VERSION 5.8 ;
BUSBITCHARS "[]" ;
DIVIDERCHAR "/" ;
UNITS
    DATABASE MICRONS 1000 ;
END UNITS

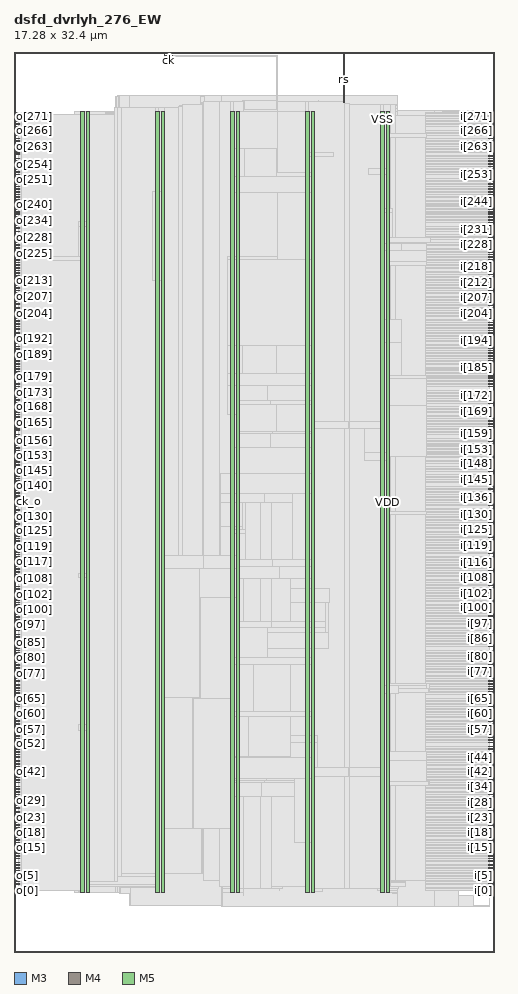
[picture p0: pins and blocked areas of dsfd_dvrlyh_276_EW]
MACRO dsfd_dvrlyh_276_EW
  FOREIGN dsfd_dvrlyh_276_EW 0 0 ;
  CLASS BLOCK ;
  SIZE 17.28 BY 32.4 ;
  PIN ck
    DIRECTION INPUT ;
    USE SIGNAL ;
    PORT
      LAYER M3 ;
        RECT  5.4 32.256 5.418 32.4 ;
    END
    PORT
      LAYER M3 ;
        RECT  5.4 32.155 5.706 32.268 ;
    END
  END ck
  PIN ck_o
    DIRECTION OUTPUT ;
    USE SIGNAL ;
    PORT
      LAYER M4 ;
        RECT  0 16.224 0.192 16.248 ;
    END
  END ck_o
  PIN i[0]
    DIRECTION INPUT ;
    USE SIGNAL ;
    PORT
      LAYER M4 ;
        RECT  17.088 2.208 17.28 2.232 ;
    END
  END i[0]
  PIN i[100]
    DIRECTION INPUT ;
    USE SIGNAL ;
    PORT
      LAYER M4 ;
        RECT  17.088 12.384 17.28 12.408 ;
    END
  END i[100]
  PIN i[101]
    DIRECTION INPUT ;
    USE SIGNAL ;
    PORT
      LAYER M4 ;
        RECT  17.088 12.48 17.28 12.504 ;
    END
  END i[101]
  PIN i[102]
    DIRECTION INPUT ;
    USE SIGNAL ;
    PORT
      LAYER M4 ;
        RECT  17.088 12.624 17.28 12.648 ;
    END
  END i[102]
  PIN i[103]
    DIRECTION INPUT ;
    USE SIGNAL ;
    PORT
      LAYER M4 ;
        RECT  17.088 12.72 17.28 12.744 ;
    END
  END i[103]
  PIN i[104]
    DIRECTION INPUT ;
    USE SIGNAL ;
    PORT
      LAYER M4 ;
        RECT  17.088 12.816 17.28 12.84 ;
    END
  END i[104]
  PIN i[105]
    DIRECTION INPUT ;
    USE SIGNAL ;
    PORT
      LAYER M4 ;
        RECT  17.088 12.912 17.28 12.936 ;
    END
  END i[105]
  PIN i[106]
    DIRECTION INPUT ;
    USE SIGNAL ;
    PORT
      LAYER M4 ;
        RECT  17.088 13.008 17.28 13.032 ;
    END
  END i[106]
  PIN i[107]
    DIRECTION INPUT ;
    USE SIGNAL ;
    PORT
      LAYER M4 ;
        RECT  17.088 13.104 17.28 13.128 ;
    END
  END i[107]
  PIN i[108]
    DIRECTION INPUT ;
    USE SIGNAL ;
    PORT
      LAYER M4 ;
        RECT  17.088 13.2 17.28 13.224 ;
    END
  END i[108]
  PIN i[109]
    DIRECTION INPUT ;
    USE SIGNAL ;
    PORT
      LAYER M4 ;
        RECT  17.088 13.296 17.28 13.32 ;
    END
  END i[109]
  PIN i[10]
    DIRECTION INPUT ;
    USE SIGNAL ;
    PORT
      LAYER M4 ;
        RECT  17.088 3.264 17.28 3.288 ;
    END
  END i[10]
  PIN i[110]
    DIRECTION INPUT ;
    USE SIGNAL ;
    PORT
      LAYER M4 ;
        RECT  17.088 13.392 17.28 13.416 ;
    END
  END i[110]
  PIN i[111]
    DIRECTION INPUT ;
    USE SIGNAL ;
    PORT
      LAYER M4 ;
        RECT  17.088 13.536 17.28 13.56 ;
    END
  END i[111]
  PIN i[112]
    DIRECTION INPUT ;
    USE SIGNAL ;
    PORT
      LAYER M4 ;
        RECT  17.088 13.632 17.28 13.656 ;
    END
  END i[112]
  PIN i[113]
    DIRECTION INPUT ;
    USE SIGNAL ;
    PORT
      LAYER M4 ;
        RECT  17.088 13.728 17.28 13.752 ;
    END
  END i[113]
  PIN i[114]
    DIRECTION INPUT ;
    USE SIGNAL ;
    PORT
      LAYER M4 ;
        RECT  17.088 13.824 17.28 13.848 ;
    END
  END i[114]
  PIN i[115]
    DIRECTION INPUT ;
    USE SIGNAL ;
    PORT
      LAYER M4 ;
        RECT  17.088 13.92 17.28 13.944 ;
    END
  END i[115]
  PIN i[116]
    DIRECTION INPUT ;
    USE SIGNAL ;
    PORT
      LAYER M4 ;
        RECT  17.088 14.016 17.28 14.04 ;
    END
  END i[116]
  PIN i[117]
    DIRECTION INPUT ;
    USE SIGNAL ;
    PORT
      LAYER M4 ;
        RECT  17.088 14.112 17.28 14.136 ;
    END
  END i[117]
  PIN i[118]
    DIRECTION INPUT ;
    USE SIGNAL ;
    PORT
      LAYER M4 ;
        RECT  17.088 14.208 17.28 14.232 ;
    END
  END i[118]
  PIN i[119]
    DIRECTION INPUT ;
    USE SIGNAL ;
    PORT
      LAYER M4 ;
        RECT  17.088 14.352 17.28 14.376 ;
    END
  END i[119]
  PIN i[11]
    DIRECTION INPUT ;
    USE SIGNAL ;
    PORT
      LAYER M4 ;
        RECT  17.088 3.36 17.28 3.384 ;
    END
  END i[11]
  PIN i[120]
    DIRECTION INPUT ;
    USE SIGNAL ;
    PORT
      LAYER M4 ;
        RECT  17.088 14.448 17.28 14.472 ;
    END
  END i[120]
  PIN i[121]
    DIRECTION INPUT ;
    USE SIGNAL ;
    PORT
      LAYER M4 ;
        RECT  17.088 14.544 17.28 14.568 ;
    END
  END i[121]
  PIN i[122]
    DIRECTION INPUT ;
    USE SIGNAL ;
    PORT
      LAYER M4 ;
        RECT  17.088 14.64 17.28 14.664 ;
    END
  END i[122]
  PIN i[123]
    DIRECTION INPUT ;
    USE SIGNAL ;
    PORT
      LAYER M4 ;
        RECT  17.088 14.736 17.28 14.76 ;
    END
  END i[123]
  PIN i[124]
    DIRECTION INPUT ;
    USE SIGNAL ;
    PORT
      LAYER M4 ;
        RECT  17.088 14.832 17.28 14.856 ;
    END
  END i[124]
  PIN i[125]
    DIRECTION INPUT ;
    USE SIGNAL ;
    PORT
      LAYER M4 ;
        RECT  17.088 14.928 17.28 14.952 ;
    END
  END i[125]
  PIN i[126]
    DIRECTION INPUT ;
    USE SIGNAL ;
    PORT
      LAYER M4 ;
        RECT  17.088 15.024 17.28 15.048 ;
    END
  END i[126]
  PIN i[127]
    DIRECTION INPUT ;
    USE SIGNAL ;
    PORT
      LAYER M4 ;
        RECT  17.088 15.12 17.28 15.144 ;
    END
  END i[127]
  PIN i[128]
    DIRECTION INPUT ;
    USE SIGNAL ;
    PORT
      LAYER M4 ;
        RECT  17.088 15.264 17.28 15.288 ;
    END
  END i[128]
  PIN i[129]
    DIRECTION INPUT ;
    USE SIGNAL ;
    PORT
      LAYER M4 ;
        RECT  17.088 15.36 17.28 15.384 ;
    END
  END i[129]
  PIN i[12]
    DIRECTION INPUT ;
    USE SIGNAL ;
    PORT
      LAYER M4 ;
        RECT  17.088 3.456 17.28 3.48 ;
    END
  END i[12]
  PIN i[130]
    DIRECTION INPUT ;
    USE SIGNAL ;
    PORT
      LAYER M4 ;
        RECT  17.088 15.456 17.28 15.48 ;
    END
  END i[130]
  PIN i[131]
    DIRECTION INPUT ;
    USE SIGNAL ;
    PORT
      LAYER M4 ;
        RECT  17.088 15.552 17.28 15.576 ;
    END
  END i[131]
  PIN i[132]
    DIRECTION INPUT ;
    USE SIGNAL ;
    PORT
      LAYER M4 ;
        RECT  17.088 15.648 17.28 15.672 ;
    END
  END i[132]
  PIN i[133]
    DIRECTION INPUT ;
    USE SIGNAL ;
    PORT
      LAYER M4 ;
        RECT  17.088 15.744 17.28 15.768 ;
    END
  END i[133]
  PIN i[134]
    DIRECTION INPUT ;
    USE SIGNAL ;
    PORT
      LAYER M4 ;
        RECT  17.088 15.84 17.28 15.864 ;
    END
  END i[134]
  PIN i[135]
    DIRECTION INPUT ;
    USE SIGNAL ;
    PORT
      LAYER M4 ;
        RECT  17.088 15.936 17.28 15.96 ;
    END
  END i[135]
  PIN i[136]
    DIRECTION INPUT ;
    USE SIGNAL ;
    PORT
      LAYER M4 ;
        RECT  17.088 16.08 17.28 16.104 ;
    END
  END i[136]
  PIN i[137]
    DIRECTION INPUT ;
    USE SIGNAL ;
    PORT
      LAYER M4 ;
        RECT  17.088 16.176 17.28 16.2 ;
    END
  END i[137]
  PIN i[138]
    DIRECTION INPUT ;
    USE SIGNAL ;
    PORT
      LAYER M4 ;
        RECT  17.088 16.272 17.28 16.296 ;
    END
  END i[138]
  PIN i[139]
    DIRECTION INPUT ;
    USE SIGNAL ;
    PORT
      LAYER M4 ;
        RECT  17.088 16.368 17.28 16.392 ;
    END
  END i[139]
  PIN i[13]
    DIRECTION INPUT ;
    USE SIGNAL ;
    PORT
      LAYER M4 ;
        RECT  17.088 3.552 17.28 3.576 ;
    END
  END i[13]
  PIN i[140]
    DIRECTION INPUT ;
    USE SIGNAL ;
    PORT
      LAYER M4 ;
        RECT  17.088 16.464 17.28 16.488 ;
    END
  END i[140]
  PIN i[141]
    DIRECTION INPUT ;
    USE SIGNAL ;
    PORT
      LAYER M4 ;
        RECT  17.088 16.56 17.28 16.584 ;
    END
  END i[141]
  PIN i[142]
    DIRECTION INPUT ;
    USE SIGNAL ;
    PORT
      LAYER M4 ;
        RECT  17.088 16.656 17.28 16.68 ;
    END
  END i[142]
  PIN i[143]
    DIRECTION INPUT ;
    USE SIGNAL ;
    PORT
      LAYER M4 ;
        RECT  17.088 16.752 17.28 16.776 ;
    END
  END i[143]
  PIN i[144]
    DIRECTION INPUT ;
    USE SIGNAL ;
    PORT
      LAYER M4 ;
        RECT  17.088 16.896 17.28 16.92 ;
    END
  END i[144]
  PIN i[145]
    DIRECTION INPUT ;
    USE SIGNAL ;
    PORT
      LAYER M4 ;
        RECT  17.088 16.992 17.28 17.016 ;
    END
  END i[145]
  PIN i[146]
    DIRECTION INPUT ;
    USE SIGNAL ;
    PORT
      LAYER M4 ;
        RECT  17.088 17.088 17.28 17.112 ;
    END
  END i[146]
  PIN i[147]
    DIRECTION INPUT ;
    USE SIGNAL ;
    PORT
      LAYER M4 ;
        RECT  17.088 17.184 17.28 17.208 ;
    END
  END i[147]
  PIN i[148]
    DIRECTION INPUT ;
    USE SIGNAL ;
    PORT
      LAYER M4 ;
        RECT  17.088 17.28 17.28 17.304 ;
    END
  END i[148]
  PIN i[149]
    DIRECTION INPUT ;
    USE SIGNAL ;
    PORT
      LAYER M4 ;
        RECT  17.088 17.376 17.28 17.4 ;
    END
  END i[149]
  PIN i[14]
    DIRECTION INPUT ;
    USE SIGNAL ;
    PORT
      LAYER M4 ;
        RECT  17.088 3.648 17.28 3.672 ;
    END
  END i[14]
  PIN i[150]
    DIRECTION INPUT ;
    USE SIGNAL ;
    PORT
      LAYER M4 ;
        RECT  17.088 17.472 17.28 17.496 ;
    END
  END i[150]
  PIN i[151]
    DIRECTION INPUT ;
    USE SIGNAL ;
    PORT
      LAYER M4 ;
        RECT  17.088 17.568 17.28 17.592 ;
    END
  END i[151]
  PIN i[152]
    DIRECTION INPUT ;
    USE SIGNAL ;
    PORT
      LAYER M4 ;
        RECT  17.088 17.664 17.28 17.688 ;
    END
  END i[152]
  PIN i[153]
    DIRECTION INPUT ;
    USE SIGNAL ;
    PORT
      LAYER M4 ;
        RECT  17.088 17.808 17.28 17.832 ;
    END
  END i[153]
  PIN i[154]
    DIRECTION INPUT ;
    USE SIGNAL ;
    PORT
      LAYER M4 ;
        RECT  17.088 17.904 17.28 17.928 ;
    END
  END i[154]
  PIN i[155]
    DIRECTION INPUT ;
    USE SIGNAL ;
    PORT
      LAYER M4 ;
        RECT  17.088 18 17.28 18.024 ;
    END
  END i[155]
  PIN i[156]
    DIRECTION INPUT ;
    USE SIGNAL ;
    PORT
      LAYER M4 ;
        RECT  17.088 18.096 17.28 18.12 ;
    END
  END i[156]
  PIN i[157]
    DIRECTION INPUT ;
    USE SIGNAL ;
    PORT
      LAYER M4 ;
        RECT  17.088 18.192 17.28 18.216 ;
    END
  END i[157]
  PIN i[158]
    DIRECTION INPUT ;
    USE SIGNAL ;
    PORT
      LAYER M4 ;
        RECT  17.088 18.288 17.28 18.312 ;
    END
  END i[158]
  PIN i[159]
    DIRECTION INPUT ;
    USE SIGNAL ;
    PORT
      LAYER M4 ;
        RECT  17.088 18.384 17.28 18.408 ;
    END
  END i[159]
  PIN i[15]
    DIRECTION INPUT ;
    USE SIGNAL ;
    PORT
      LAYER M4 ;
        RECT  17.088 3.744 17.28 3.768 ;
    END
  END i[15]
  PIN i[160]
    DIRECTION INPUT ;
    USE SIGNAL ;
    PORT
      LAYER M4 ;
        RECT  17.088 18.48 17.28 18.504 ;
    END
  END i[160]
  PIN i[161]
    DIRECTION INPUT ;
    USE SIGNAL ;
    PORT
      LAYER M4 ;
        RECT  17.088 18.624 17.28 18.648 ;
    END
  END i[161]
  PIN i[162]
    DIRECTION INPUT ;
    USE SIGNAL ;
    PORT
      LAYER M4 ;
        RECT  17.088 18.72 17.28 18.744 ;
    END
  END i[162]
  PIN i[163]
    DIRECTION INPUT ;
    USE SIGNAL ;
    PORT
      LAYER M4 ;
        RECT  17.088 18.816 17.28 18.84 ;
    END
  END i[163]
  PIN i[164]
    DIRECTION INPUT ;
    USE SIGNAL ;
    PORT
      LAYER M4 ;
        RECT  17.088 18.912 17.28 18.936 ;
    END
  END i[164]
  PIN i[165]
    DIRECTION INPUT ;
    USE SIGNAL ;
    PORT
      LAYER M4 ;
        RECT  17.088 19.008 17.28 19.032 ;
    END
  END i[165]
  PIN i[166]
    DIRECTION INPUT ;
    USE SIGNAL ;
    PORT
      LAYER M4 ;
        RECT  17.088 19.104 17.28 19.128 ;
    END
  END i[166]
  PIN i[167]
    DIRECTION INPUT ;
    USE SIGNAL ;
    PORT
      LAYER M4 ;
        RECT  17.088 19.2 17.28 19.224 ;
    END
  END i[167]
  PIN i[168]
    DIRECTION INPUT ;
    USE SIGNAL ;
    PORT
      LAYER M4 ;
        RECT  17.088 19.296 17.28 19.32 ;
    END
  END i[168]
  PIN i[169]
    DIRECTION INPUT ;
    USE SIGNAL ;
    PORT
      LAYER M4 ;
        RECT  17.088 19.44 17.28 19.464 ;
    END
  END i[169]
  PIN i[16]
    DIRECTION INPUT ;
    USE SIGNAL ;
    PORT
      LAYER M4 ;
        RECT  17.088 3.84 17.28 3.864 ;
    END
  END i[16]
  PIN i[170]
    DIRECTION INPUT ;
    USE SIGNAL ;
    PORT
      LAYER M4 ;
        RECT  17.088 19.536 17.28 19.56 ;
    END
  END i[170]
  PIN i[171]
    DIRECTION INPUT ;
    USE SIGNAL ;
    PORT
      LAYER M4 ;
        RECT  17.088 19.632 17.28 19.656 ;
    END
  END i[171]
  PIN i[172]
    DIRECTION INPUT ;
    USE SIGNAL ;
    PORT
      LAYER M4 ;
        RECT  17.088 19.728 17.28 19.752 ;
    END
  END i[172]
  PIN i[173]
    DIRECTION INPUT ;
    USE SIGNAL ;
    PORT
      LAYER M4 ;
        RECT  17.088 19.824 17.28 19.848 ;
    END
  END i[173]
  PIN i[174]
    DIRECTION INPUT ;
    USE SIGNAL ;
    PORT
      LAYER M4 ;
        RECT  17.088 19.92 17.28 19.944 ;
    END
  END i[174]
  PIN i[175]
    DIRECTION INPUT ;
    USE SIGNAL ;
    PORT
      LAYER M4 ;
        RECT  17.088 20.016 17.28 20.04 ;
    END
  END i[175]
  PIN i[176]
    DIRECTION INPUT ;
    USE SIGNAL ;
    PORT
      LAYER M4 ;
        RECT  17.088 20.112 17.28 20.136 ;
    END
  END i[176]
  PIN i[177]
    DIRECTION INPUT ;
    USE SIGNAL ;
    PORT
      LAYER M4 ;
        RECT  17.088 20.208 17.28 20.232 ;
    END
  END i[177]
  PIN i[178]
    DIRECTION INPUT ;
    USE SIGNAL ;
    PORT
      LAYER M4 ;
        RECT  17.088 20.352 17.28 20.376 ;
    END
  END i[178]
  PIN i[179]
    DIRECTION INPUT ;
    USE SIGNAL ;
    PORT
      LAYER M4 ;
        RECT  17.088 20.448 17.28 20.472 ;
    END
  END i[179]
  PIN i[17]
    DIRECTION INPUT ;
    USE SIGNAL ;
    PORT
      LAYER M4 ;
        RECT  17.088 3.936 17.28 3.96 ;
    END
  END i[17]
  PIN i[180]
    DIRECTION INPUT ;
    USE SIGNAL ;
    PORT
      LAYER M4 ;
        RECT  17.088 20.544 17.28 20.568 ;
    END
  END i[180]
  PIN i[181]
    DIRECTION INPUT ;
    USE SIGNAL ;
    PORT
      LAYER M4 ;
        RECT  17.088 20.64 17.28 20.664 ;
    END
  END i[181]
  PIN i[182]
    DIRECTION INPUT ;
    USE SIGNAL ;
    PORT
      LAYER M4 ;
        RECT  17.088 20.736 17.28 20.76 ;
    END
  END i[182]
  PIN i[183]
    DIRECTION INPUT ;
    USE SIGNAL ;
    PORT
      LAYER M4 ;
        RECT  17.088 20.832 17.28 20.856 ;
    END
  END i[183]
  PIN i[184]
    DIRECTION INPUT ;
    USE SIGNAL ;
    PORT
      LAYER M4 ;
        RECT  17.088 20.928 17.28 20.952 ;
    END
  END i[184]
  PIN i[185]
    DIRECTION INPUT ;
    USE SIGNAL ;
    PORT
      LAYER M4 ;
        RECT  17.088 21.024 17.28 21.048 ;
    END
  END i[185]
  PIN i[186]
    DIRECTION INPUT ;
    USE SIGNAL ;
    PORT
      LAYER M4 ;
        RECT  17.088 21.168 17.28 21.192 ;
    END
  END i[186]
  PIN i[187]
    DIRECTION INPUT ;
    USE SIGNAL ;
    PORT
      LAYER M4 ;
        RECT  17.088 21.264 17.28 21.288 ;
    END
  END i[187]
  PIN i[188]
    DIRECTION INPUT ;
    USE SIGNAL ;
    PORT
      LAYER M4 ;
        RECT  17.088 21.36 17.28 21.384 ;
    END
  END i[188]
  PIN i[189]
    DIRECTION INPUT ;
    USE SIGNAL ;
    PORT
      LAYER M4 ;
        RECT  17.088 21.456 17.28 21.48 ;
    END
  END i[189]
  PIN i[18]
    DIRECTION INPUT ;
    USE SIGNAL ;
    PORT
      LAYER M4 ;
        RECT  17.088 4.032 17.28 4.056 ;
    END
  END i[18]
  PIN i[190]
    DIRECTION INPUT ;
    USE SIGNAL ;
    PORT
      LAYER M4 ;
        RECT  17.088 21.552 17.28 21.576 ;
    END
  END i[190]
  PIN i[191]
    DIRECTION INPUT ;
    USE SIGNAL ;
    PORT
      LAYER M4 ;
        RECT  17.088 21.648 17.28 21.672 ;
    END
  END i[191]
  PIN i[192]
    DIRECTION INPUT ;
    USE SIGNAL ;
    PORT
      LAYER M4 ;
        RECT  17.088 21.744 17.28 21.768 ;
    END
  END i[192]
  PIN i[193]
    DIRECTION INPUT ;
    USE SIGNAL ;
    PORT
      LAYER M4 ;
        RECT  17.088 21.84 17.28 21.864 ;
    END
  END i[193]
  PIN i[194]
    DIRECTION INPUT ;
    USE SIGNAL ;
    PORT
      LAYER M4 ;
        RECT  17.088 21.984 17.28 22.008 ;
    END
  END i[194]
  PIN i[195]
    DIRECTION INPUT ;
    USE SIGNAL ;
    PORT
      LAYER M4 ;
        RECT  17.088 22.08 17.28 22.104 ;
    END
  END i[195]
  PIN i[196]
    DIRECTION INPUT ;
    USE SIGNAL ;
    PORT
      LAYER M4 ;
        RECT  17.088 22.176 17.28 22.2 ;
    END
  END i[196]
  PIN i[197]
    DIRECTION INPUT ;
    USE SIGNAL ;
    PORT
      LAYER M4 ;
        RECT  17.088 22.272 17.28 22.296 ;
    END
  END i[197]
  PIN i[198]
    DIRECTION INPUT ;
    USE SIGNAL ;
    PORT
      LAYER M4 ;
        RECT  17.088 22.368 17.28 22.392 ;
    END
  END i[198]
  PIN i[199]
    DIRECTION INPUT ;
    USE SIGNAL ;
    PORT
      LAYER M4 ;
        RECT  17.088 22.464 17.28 22.488 ;
    END
  END i[199]
  PIN i[19]
    DIRECTION INPUT ;
    USE SIGNAL ;
    PORT
      LAYER M4 ;
        RECT  17.088 4.176 17.28 4.2 ;
    END
  END i[19]
  PIN i[1]
    DIRECTION INPUT ;
    USE SIGNAL ;
    PORT
      LAYER M4 ;
        RECT  17.088 2.304 17.28 2.328 ;
    END
  END i[1]
  PIN i[200]
    DIRECTION INPUT ;
    USE SIGNAL ;
    PORT
      LAYER M4 ;
        RECT  17.088 22.56 17.28 22.584 ;
    END
  END i[200]
  PIN i[201]
    DIRECTION INPUT ;
    USE SIGNAL ;
    PORT
      LAYER M4 ;
        RECT  17.088 22.656 17.28 22.68 ;
    END
  END i[201]
  PIN i[202]
    DIRECTION INPUT ;
    USE SIGNAL ;
    PORT
      LAYER M4 ;
        RECT  17.088 22.752 17.28 22.776 ;
    END
  END i[202]
  PIN i[203]
    DIRECTION INPUT ;
    USE SIGNAL ;
    PORT
      LAYER M4 ;
        RECT  17.088 22.896 17.28 22.92 ;
    END
  END i[203]
  PIN i[204]
    DIRECTION INPUT ;
    USE SIGNAL ;
    PORT
      LAYER M4 ;
        RECT  17.088 22.992 17.28 23.016 ;
    END
  END i[204]
  PIN i[205]
    DIRECTION INPUT ;
    USE SIGNAL ;
    PORT
      LAYER M4 ;
        RECT  17.088 23.088 17.28 23.112 ;
    END
  END i[205]
  PIN i[206]
    DIRECTION INPUT ;
    USE SIGNAL ;
    PORT
      LAYER M4 ;
        RECT  17.088 23.184 17.28 23.208 ;
    END
  END i[206]
  PIN i[207]
    DIRECTION INPUT ;
    USE SIGNAL ;
    PORT
      LAYER M4 ;
        RECT  17.088 23.28 17.28 23.304 ;
    END
  END i[207]
  PIN i[208]
    DIRECTION INPUT ;
    USE SIGNAL ;
    PORT
      LAYER M4 ;
        RECT  17.088 23.376 17.28 23.4 ;
    END
  END i[208]
  PIN i[209]
    DIRECTION INPUT ;
    USE SIGNAL ;
    PORT
      LAYER M4 ;
        RECT  17.088 23.472 17.28 23.496 ;
    END
  END i[209]
  PIN i[20]
    DIRECTION INPUT ;
    USE SIGNAL ;
    PORT
      LAYER M4 ;
        RECT  17.088 4.272 17.28 4.296 ;
    END
  END i[20]
  PIN i[210]
    DIRECTION INPUT ;
    USE SIGNAL ;
    PORT
      LAYER M4 ;
        RECT  17.088 23.568 17.28 23.592 ;
    END
  END i[210]
  PIN i[211]
    DIRECTION INPUT ;
    USE SIGNAL ;
    PORT
      LAYER M4 ;
        RECT  17.088 23.712 17.28 23.736 ;
    END
  END i[211]
  PIN i[212]
    DIRECTION INPUT ;
    USE SIGNAL ;
    PORT
      LAYER M4 ;
        RECT  17.088 23.808 17.28 23.832 ;
    END
  END i[212]
  PIN i[213]
    DIRECTION INPUT ;
    USE SIGNAL ;
    PORT
      LAYER M4 ;
        RECT  17.088 23.904 17.28 23.928 ;
    END
  END i[213]
  PIN i[214]
    DIRECTION INPUT ;
    USE SIGNAL ;
    PORT
      LAYER M4 ;
        RECT  17.088 24 17.28 24.024 ;
    END
  END i[214]
  PIN i[215]
    DIRECTION INPUT ;
    USE SIGNAL ;
    PORT
      LAYER M4 ;
        RECT  17.088 24.096 17.28 24.12 ;
    END
  END i[215]
  PIN i[216]
    DIRECTION INPUT ;
    USE SIGNAL ;
    PORT
      LAYER M4 ;
        RECT  17.088 24.192 17.28 24.216 ;
    END
  END i[216]
  PIN i[217]
    DIRECTION INPUT ;
    USE SIGNAL ;
    PORT
      LAYER M4 ;
        RECT  17.088 24.288 17.28 24.312 ;
    END
  END i[217]
  PIN i[218]
    DIRECTION INPUT ;
    USE SIGNAL ;
    PORT
      LAYER M4 ;
        RECT  17.088 24.384 17.28 24.408 ;
    END
  END i[218]
  PIN i[219]
    DIRECTION INPUT ;
    USE SIGNAL ;
    PORT
      LAYER M4 ;
        RECT  17.088 24.48 17.28 24.504 ;
    END
  END i[219]
  PIN i[21]
    DIRECTION INPUT ;
    USE SIGNAL ;
    PORT
      LAYER M4 ;
        RECT  17.088 4.368 17.28 4.392 ;
    END
  END i[21]
  PIN i[220]
    DIRECTION INPUT ;
    USE SIGNAL ;
    PORT
      LAYER M4 ;
        RECT  17.088 24.624 17.28 24.648 ;
    END
  END i[220]
  PIN i[221]
    DIRECTION INPUT ;
    USE SIGNAL ;
    PORT
      LAYER M4 ;
        RECT  17.088 24.72 17.28 24.744 ;
    END
  END i[221]
  PIN i[222]
    DIRECTION INPUT ;
    USE SIGNAL ;
    PORT
      LAYER M4 ;
        RECT  17.088 24.816 17.28 24.84 ;
    END
  END i[222]
  PIN i[223]
    DIRECTION INPUT ;
    USE SIGNAL ;
    PORT
      LAYER M4 ;
        RECT  17.088 24.912 17.28 24.936 ;
    END
  END i[223]
  PIN i[224]
    DIRECTION INPUT ;
    USE SIGNAL ;
    PORT
      LAYER M4 ;
        RECT  17.088 25.008 17.28 25.032 ;
    END
  END i[224]
  PIN i[225]
    DIRECTION INPUT ;
    USE SIGNAL ;
    PORT
      LAYER M4 ;
        RECT  17.088 25.104 17.28 25.128 ;
    END
  END i[225]
  PIN i[226]
    DIRECTION INPUT ;
    USE SIGNAL ;
    PORT
      LAYER M4 ;
        RECT  17.088 25.2 17.28 25.224 ;
    END
  END i[226]
  PIN i[227]
    DIRECTION INPUT ;
    USE SIGNAL ;
    PORT
      LAYER M4 ;
        RECT  17.088 25.296 17.28 25.32 ;
    END
  END i[227]
  PIN i[228]
    DIRECTION INPUT ;
    USE SIGNAL ;
    PORT
      LAYER M4 ;
        RECT  17.088 25.44 17.28 25.464 ;
    END
  END i[228]
  PIN i[229]
    DIRECTION INPUT ;
    USE SIGNAL ;
    PORT
      LAYER M4 ;
        RECT  17.088 25.536 17.28 25.56 ;
    END
  END i[229]
  PIN i[22]
    DIRECTION INPUT ;
    USE SIGNAL ;
    PORT
      LAYER M4 ;
        RECT  17.088 4.464 17.28 4.488 ;
    END
  END i[22]
  PIN i[230]
    DIRECTION INPUT ;
    USE SIGNAL ;
    PORT
      LAYER M4 ;
        RECT  17.088 25.632 17.28 25.656 ;
    END
  END i[230]
  PIN i[231]
    DIRECTION INPUT ;
    USE SIGNAL ;
    PORT
      LAYER M4 ;
        RECT  17.088 25.728 17.28 25.752 ;
    END
  END i[231]
  PIN i[232]
    DIRECTION INPUT ;
    USE SIGNAL ;
    PORT
      LAYER M4 ;
        RECT  17.088 25.824 17.28 25.848 ;
    END
  END i[232]
  PIN i[233]
    DIRECTION INPUT ;
    USE SIGNAL ;
    PORT
      LAYER M4 ;
        RECT  17.088 25.92 17.28 25.944 ;
    END
  END i[233]
  PIN i[234]
    DIRECTION INPUT ;
    USE SIGNAL ;
    PORT
      LAYER M4 ;
        RECT  17.088 26.016 17.28 26.04 ;
    END
  END i[234]
  PIN i[235]
    DIRECTION INPUT ;
    USE SIGNAL ;
    PORT
      LAYER M4 ;
        RECT  17.088 26.112 17.28 26.136 ;
    END
  END i[235]
  PIN i[236]
    DIRECTION INPUT ;
    USE SIGNAL ;
    PORT
      LAYER M4 ;
        RECT  17.088 26.256 17.28 26.28 ;
    END
  END i[236]
  PIN i[237]
    DIRECTION INPUT ;
    USE SIGNAL ;
    PORT
      LAYER M4 ;
        RECT  17.088 26.352 17.28 26.376 ;
    END
  END i[237]
  PIN i[238]
    DIRECTION INPUT ;
    USE SIGNAL ;
    PORT
      LAYER M4 ;
        RECT  17.088 26.448 17.28 26.472 ;
    END
  END i[238]
  PIN i[239]
    DIRECTION INPUT ;
    USE SIGNAL ;
    PORT
      LAYER M4 ;
        RECT  17.088 26.544 17.28 26.568 ;
    END
  END i[239]
  PIN i[23]
    DIRECTION INPUT ;
    USE SIGNAL ;
    PORT
      LAYER M4 ;
        RECT  17.088 4.56 17.28 4.584 ;
    END
  END i[23]
  PIN i[240]
    DIRECTION INPUT ;
    USE SIGNAL ;
    PORT
      LAYER M4 ;
        RECT  17.088 26.64 17.28 26.664 ;
    END
  END i[240]
  PIN i[241]
    DIRECTION INPUT ;
    USE SIGNAL ;
    PORT
      LAYER M4 ;
        RECT  17.088 26.736 17.28 26.76 ;
    END
  END i[241]
  PIN i[242]
    DIRECTION INPUT ;
    USE SIGNAL ;
    PORT
      LAYER M4 ;
        RECT  17.088 26.832 17.28 26.856 ;
    END
  END i[242]
  PIN i[243]
    DIRECTION INPUT ;
    USE SIGNAL ;
    PORT
      LAYER M4 ;
        RECT  17.088 26.928 17.28 26.952 ;
    END
  END i[243]
  PIN i[244]
    DIRECTION INPUT ;
    USE SIGNAL ;
    PORT
      LAYER M4 ;
        RECT  17.088 27.024 17.28 27.048 ;
    END
  END i[244]
  PIN i[245]
    DIRECTION INPUT ;
    USE SIGNAL ;
    PORT
      LAYER M4 ;
        RECT  17.088 27.168 17.28 27.192 ;
    END
  END i[245]
  PIN i[246]
    DIRECTION INPUT ;
    USE SIGNAL ;
    PORT
      LAYER M4 ;
        RECT  17.088 27.264 17.28 27.288 ;
    END
  END i[246]
  PIN i[247]
    DIRECTION INPUT ;
    USE SIGNAL ;
    PORT
      LAYER M4 ;
        RECT  17.088 27.36 17.28 27.384 ;
    END
  END i[247]
  PIN i[248]
    DIRECTION INPUT ;
    USE SIGNAL ;
    PORT
      LAYER M4 ;
        RECT  17.088 27.456 17.28 27.48 ;
    END
  END i[248]
  PIN i[249]
    DIRECTION INPUT ;
    USE SIGNAL ;
    PORT
      LAYER M4 ;
        RECT  17.088 27.552 17.28 27.576 ;
    END
  END i[249]
  PIN i[24]
    DIRECTION INPUT ;
    USE SIGNAL ;
    PORT
      LAYER M4 ;
        RECT  17.088 4.656 17.28 4.68 ;
    END
  END i[24]
  PIN i[250]
    DIRECTION INPUT ;
    USE SIGNAL ;
    PORT
      LAYER M4 ;
        RECT  17.088 27.648 17.28 27.672 ;
    END
  END i[250]
  PIN i[251]
    DIRECTION INPUT ;
    USE SIGNAL ;
    PORT
      LAYER M4 ;
        RECT  17.088 27.744 17.28 27.768 ;
    END
  END i[251]
  PIN i[252]
    DIRECTION INPUT ;
    USE SIGNAL ;
    PORT
      LAYER M4 ;
        RECT  17.088 27.84 17.28 27.864 ;
    END
  END i[252]
  PIN i[253]
    DIRECTION INPUT ;
    USE SIGNAL ;
    PORT
      LAYER M4 ;
        RECT  17.088 27.984 17.28 28.008 ;
    END
  END i[253]
  PIN i[254]
    DIRECTION INPUT ;
    USE SIGNAL ;
    PORT
      LAYER M4 ;
        RECT  17.088 28.08 17.28 28.104 ;
    END
  END i[254]
  PIN i[255]
    DIRECTION INPUT ;
    USE SIGNAL ;
    PORT
      LAYER M4 ;
        RECT  17.088 28.176 17.28 28.2 ;
    END
  END i[255]
  PIN i[256]
    DIRECTION INPUT ;
    USE SIGNAL ;
    PORT
      LAYER M4 ;
        RECT  17.088 28.272 17.28 28.296 ;
    END
  END i[256]
  PIN i[257]
    DIRECTION INPUT ;
    USE SIGNAL ;
    PORT
      LAYER M4 ;
        RECT  17.088 28.368 17.28 28.392 ;
    END
  END i[257]
  PIN i[258]
    DIRECTION INPUT ;
    USE SIGNAL ;
    PORT
      LAYER M4 ;
        RECT  17.088 28.464 17.28 28.488 ;
    END
  END i[258]
  PIN i[259]
    DIRECTION INPUT ;
    USE SIGNAL ;
    PORT
      LAYER M4 ;
        RECT  17.088 28.56 17.28 28.584 ;
    END
  END i[259]
  PIN i[25]
    DIRECTION INPUT ;
    USE SIGNAL ;
    PORT
      LAYER M4 ;
        RECT  17.088 4.752 17.28 4.776 ;
    END
  END i[25]
  PIN i[260]
    DIRECTION INPUT ;
    USE SIGNAL ;
    PORT
      LAYER M4 ;
        RECT  17.088 28.656 17.28 28.68 ;
    END
  END i[260]
  PIN i[261]
    DIRECTION INPUT ;
    USE SIGNAL ;
    PORT
      LAYER M4 ;
        RECT  17.088 28.8 17.28 28.824 ;
    END
  END i[261]
  PIN i[262]
    DIRECTION INPUT ;
    USE SIGNAL ;
    PORT
      LAYER M4 ;
        RECT  17.088 28.896 17.28 28.92 ;
    END
  END i[262]
  PIN i[263]
    DIRECTION INPUT ;
    USE SIGNAL ;
    PORT
      LAYER M4 ;
        RECT  17.088 28.992 17.28 29.016 ;
    END
  END i[263]
  PIN i[264]
    DIRECTION INPUT ;
    USE SIGNAL ;
    PORT
      LAYER M4 ;
        RECT  17.088 29.088 17.28 29.112 ;
    END
  END i[264]
  PIN i[265]
    DIRECTION INPUT ;
    USE SIGNAL ;
    PORT
      LAYER M4 ;
        RECT  17.088 29.184 17.28 29.208 ;
    END
  END i[265]
  PIN i[266]
    DIRECTION INPUT ;
    USE SIGNAL ;
    PORT
      LAYER M4 ;
        RECT  17.088 29.28 17.28 29.304 ;
    END
  END i[266]
  PIN i[267]
    DIRECTION INPUT ;
    USE SIGNAL ;
    PORT
      LAYER M4 ;
        RECT  17.088 29.376 17.28 29.4 ;
    END
  END i[267]
  PIN i[268]
    DIRECTION INPUT ;
    USE SIGNAL ;
    PORT
      LAYER M4 ;
        RECT  17.088 29.472 17.28 29.496 ;
    END
  END i[268]
  PIN i[269]
    DIRECTION INPUT ;
    USE SIGNAL ;
    PORT
      LAYER M4 ;
        RECT  17.088 29.568 17.28 29.592 ;
    END
  END i[269]
  PIN i[26]
    DIRECTION INPUT ;
    USE SIGNAL ;
    PORT
      LAYER M4 ;
        RECT  17.088 4.848 17.28 4.872 ;
    END
  END i[26]
  PIN i[270]
    DIRECTION INPUT ;
    USE SIGNAL ;
    PORT
      LAYER M4 ;
        RECT  17.088 29.712 17.28 29.736 ;
    END
  END i[270]
  PIN i[271]
    DIRECTION INPUT ;
    USE SIGNAL ;
    PORT
      LAYER M4 ;
        RECT  17.088 29.808 17.28 29.832 ;
    END
  END i[271]
  PIN i[272]
    DIRECTION INPUT ;
    USE SIGNAL ;
    PORT
      LAYER M4 ;
        RECT  17.088 29.904 17.28 29.928 ;
    END
  END i[272]
  PIN i[273]
    DIRECTION INPUT ;
    USE SIGNAL ;
    PORT
      LAYER M4 ;
        RECT  17.088 30 17.28 30.024 ;
    END
  END i[273]
  PIN i[274]
    DIRECTION INPUT ;
    USE SIGNAL ;
    PORT
      LAYER M4 ;
        RECT  17.088 30.096 17.28 30.12 ;
    END
  END i[274]
  PIN i[275]
    DIRECTION INPUT ;
    USE SIGNAL ;
    PORT
      LAYER M4 ;
        RECT  17.088 30.192 17.28 30.216 ;
    END
  END i[275]
  PIN i[27]
    DIRECTION INPUT ;
    USE SIGNAL ;
    PORT
      LAYER M4 ;
        RECT  17.088 4.992 17.28 5.016 ;
    END
  END i[27]
  PIN i[28]
    DIRECTION INPUT ;
    USE SIGNAL ;
    PORT
      LAYER M4 ;
        RECT  17.088 5.088 17.28 5.112 ;
    END
  END i[28]
  PIN i[29]
    DIRECTION INPUT ;
    USE SIGNAL ;
    PORT
      LAYER M4 ;
        RECT  17.088 5.184 17.28 5.208 ;
    END
  END i[29]
  PIN i[2]
    DIRECTION INPUT ;
    USE SIGNAL ;
    PORT
      LAYER M4 ;
        RECT  17.088 2.448 17.28 2.472 ;
    END
  END i[2]
  PIN i[30]
    DIRECTION INPUT ;
    USE SIGNAL ;
    PORT
      LAYER M4 ;
        RECT  17.088 5.28 17.28 5.304 ;
    END
  END i[30]
  PIN i[31]
    DIRECTION INPUT ;
    USE SIGNAL ;
    PORT
      LAYER M4 ;
        RECT  17.088 5.376 17.28 5.4 ;
    END
  END i[31]
  PIN i[32]
    DIRECTION INPUT ;
    USE SIGNAL ;
    PORT
      LAYER M4 ;
        RECT  17.088 5.472 17.28 5.496 ;
    END
  END i[32]
  PIN i[33]
    DIRECTION INPUT ;
    USE SIGNAL ;
    PORT
      LAYER M4 ;
        RECT  17.088 5.568 17.28 5.592 ;
    END
  END i[33]
  PIN i[34]
    DIRECTION INPUT ;
    USE SIGNAL ;
    PORT
      LAYER M4 ;
        RECT  17.088 5.664 17.28 5.688 ;
    END
  END i[34]
  PIN i[35]
    DIRECTION INPUT ;
    USE SIGNAL ;
    PORT
      LAYER M4 ;
        RECT  17.088 5.76 17.28 5.784 ;
    END
  END i[35]
  PIN i[36]
    DIRECTION INPUT ;
    USE SIGNAL ;
    PORT
      LAYER M4 ;
        RECT  17.088 5.904 17.28 5.928 ;
    END
  END i[36]
  PIN i[37]
    DIRECTION INPUT ;
    USE SIGNAL ;
    PORT
      LAYER M4 ;
        RECT  17.088 6 17.28 6.024 ;
    END
  END i[37]
  PIN i[38]
    DIRECTION INPUT ;
    USE SIGNAL ;
    PORT
      LAYER M4 ;
        RECT  17.088 6.096 17.28 6.12 ;
    END
  END i[38]
  PIN i[39]
    DIRECTION INPUT ;
    USE SIGNAL ;
    PORT
      LAYER M4 ;
        RECT  17.088 6.192 17.28 6.216 ;
    END
  END i[39]
  PIN i[3]
    DIRECTION INPUT ;
    USE SIGNAL ;
    PORT
      LAYER M4 ;
        RECT  17.088 2.544 17.28 2.568 ;
    END
  END i[3]
  PIN i[40]
    DIRECTION INPUT ;
    USE SIGNAL ;
    PORT
      LAYER M4 ;
        RECT  17.088 6.288 17.28 6.312 ;
    END
  END i[40]
  PIN i[41]
    DIRECTION INPUT ;
    USE SIGNAL ;
    PORT
      LAYER M4 ;
        RECT  17.088 6.384 17.28 6.408 ;
    END
  END i[41]
  PIN i[42]
    DIRECTION INPUT ;
    USE SIGNAL ;
    PORT
      LAYER M4 ;
        RECT  17.088 6.48 17.28 6.504 ;
    END
  END i[42]
  PIN i[43]
    DIRECTION INPUT ;
    USE SIGNAL ;
    PORT
      LAYER M4 ;
        RECT  17.088 6.576 17.28 6.6 ;
    END
  END i[43]
  PIN i[44]
    DIRECTION INPUT ;
    USE SIGNAL ;
    PORT
      LAYER M4 ;
        RECT  17.088 6.72 17.28 6.744 ;
    END
  END i[44]
  PIN i[45]
    DIRECTION INPUT ;
    USE SIGNAL ;
    PORT
      LAYER M4 ;
        RECT  17.088 6.816 17.28 6.84 ;
    END
  END i[45]
  PIN i[46]
    DIRECTION INPUT ;
    USE SIGNAL ;
    PORT
      LAYER M4 ;
        RECT  17.088 6.912 17.28 6.936 ;
    END
  END i[46]
  PIN i[47]
    DIRECTION INPUT ;
    USE SIGNAL ;
    PORT
      LAYER M4 ;
        RECT  17.088 7.008 17.28 7.032 ;
    END
  END i[47]
  PIN i[48]
    DIRECTION INPUT ;
    USE SIGNAL ;
    PORT
      LAYER M4 ;
        RECT  17.088 7.104 17.28 7.128 ;
    END
  END i[48]
  PIN i[49]
    DIRECTION INPUT ;
    USE SIGNAL ;
    PORT
      LAYER M4 ;
        RECT  17.088 7.2 17.28 7.224 ;
    END
  END i[49]
  PIN i[4]
    DIRECTION INPUT ;
    USE SIGNAL ;
    PORT
      LAYER M4 ;
        RECT  17.088 2.64 17.28 2.664 ;
    END
  END i[4]
  PIN i[50]
    DIRECTION INPUT ;
    USE SIGNAL ;
    PORT
      LAYER M4 ;
        RECT  17.088 7.296 17.28 7.32 ;
    END
  END i[50]
  PIN i[51]
    DIRECTION INPUT ;
    USE SIGNAL ;
    PORT
      LAYER M4 ;
        RECT  17.088 7.392 17.28 7.416 ;
    END
  END i[51]
  PIN i[52]
    DIRECTION INPUT ;
    USE SIGNAL ;
    PORT
      LAYER M4 ;
        RECT  17.088 7.536 17.28 7.56 ;
    END
  END i[52]
  PIN i[53]
    DIRECTION INPUT ;
    USE SIGNAL ;
    PORT
      LAYER M4 ;
        RECT  17.088 7.632 17.28 7.656 ;
    END
  END i[53]
  PIN i[54]
    DIRECTION INPUT ;
    USE SIGNAL ;
    PORT
      LAYER M4 ;
        RECT  17.088 7.728 17.28 7.752 ;
    END
  END i[54]
  PIN i[55]
    DIRECTION INPUT ;
    USE SIGNAL ;
    PORT
      LAYER M4 ;
        RECT  17.088 7.824 17.28 7.848 ;
    END
  END i[55]
  PIN i[56]
    DIRECTION INPUT ;
    USE SIGNAL ;
    PORT
      LAYER M4 ;
        RECT  17.088 7.92 17.28 7.944 ;
    END
  END i[56]
  PIN i[57]
    DIRECTION INPUT ;
    USE SIGNAL ;
    PORT
      LAYER M4 ;
        RECT  17.088 8.016 17.28 8.04 ;
    END
  END i[57]
  PIN i[58]
    DIRECTION INPUT ;
    USE SIGNAL ;
    PORT
      LAYER M4 ;
        RECT  17.088 8.112 17.28 8.136 ;
    END
  END i[58]
  PIN i[59]
    DIRECTION INPUT ;
    USE SIGNAL ;
    PORT
      LAYER M4 ;
        RECT  17.088 8.208 17.28 8.232 ;
    END
  END i[59]
  PIN i[5]
    DIRECTION INPUT ;
    USE SIGNAL ;
    PORT
      LAYER M4 ;
        RECT  17.088 2.736 17.28 2.76 ;
    END
  END i[5]
  PIN i[60]
    DIRECTION INPUT ;
    USE SIGNAL ;
    PORT
      LAYER M4 ;
        RECT  17.088 8.304 17.28 8.328 ;
    END
  END i[60]
  PIN i[61]
    DIRECTION INPUT ;
    USE SIGNAL ;
    PORT
      LAYER M4 ;
        RECT  17.088 8.448 17.28 8.472 ;
    END
  END i[61]
  PIN i[62]
    DIRECTION INPUT ;
    USE SIGNAL ;
    PORT
      LAYER M4 ;
        RECT  17.088 8.544 17.28 8.568 ;
    END
  END i[62]
  PIN i[63]
    DIRECTION INPUT ;
    USE SIGNAL ;
    PORT
      LAYER M4 ;
        RECT  17.088 8.64 17.28 8.664 ;
    END
  END i[63]
  PIN i[64]
    DIRECTION INPUT ;
    USE SIGNAL ;
    PORT
      LAYER M4 ;
        RECT  17.088 8.736 17.28 8.76 ;
    END
  END i[64]
  PIN i[65]
    DIRECTION INPUT ;
    USE SIGNAL ;
    PORT
      LAYER M4 ;
        RECT  17.088 8.832 17.28 8.856 ;
    END
  END i[65]
  PIN i[66]
    DIRECTION INPUT ;
    USE SIGNAL ;
    PORT
      LAYER M4 ;
        RECT  17.088 8.928 17.28 8.952 ;
    END
  END i[66]
  PIN i[67]
    DIRECTION INPUT ;
    USE SIGNAL ;
    PORT
      LAYER M4 ;
        RECT  17.088 9.024 17.28 9.048 ;
    END
  END i[67]
  PIN i[68]
    DIRECTION INPUT ;
    USE SIGNAL ;
    PORT
      LAYER M4 ;
        RECT  17.088 9.12 17.28 9.144 ;
    END
  END i[68]
  PIN i[69]
    DIRECTION INPUT ;
    USE SIGNAL ;
    PORT
      LAYER M4 ;
        RECT  17.088 9.264 17.28 9.288 ;
    END
  END i[69]
  PIN i[6]
    DIRECTION INPUT ;
    USE SIGNAL ;
    PORT
      LAYER M4 ;
        RECT  17.088 2.832 17.28 2.856 ;
    END
  END i[6]
  PIN i[70]
    DIRECTION INPUT ;
    USE SIGNAL ;
    PORT
      LAYER M4 ;
        RECT  17.088 9.36 17.28 9.384 ;
    END
  END i[70]
  PIN i[71]
    DIRECTION INPUT ;
    USE SIGNAL ;
    PORT
      LAYER M4 ;
        RECT  17.088 9.456 17.28 9.48 ;
    END
  END i[71]
  PIN i[72]
    DIRECTION INPUT ;
    USE SIGNAL ;
    PORT
      LAYER M4 ;
        RECT  17.088 9.552 17.28 9.576 ;
    END
  END i[72]
  PIN i[73]
    DIRECTION INPUT ;
    USE SIGNAL ;
    PORT
      LAYER M4 ;
        RECT  17.088 9.648 17.28 9.672 ;
    END
  END i[73]
  PIN i[74]
    DIRECTION INPUT ;
    USE SIGNAL ;
    PORT
      LAYER M4 ;
        RECT  17.088 9.744 17.28 9.768 ;
    END
  END i[74]
  PIN i[75]
    DIRECTION INPUT ;
    USE SIGNAL ;
    PORT
      LAYER M4 ;
        RECT  17.088 9.84 17.28 9.864 ;
    END
  END i[75]
  PIN i[76]
    DIRECTION INPUT ;
    USE SIGNAL ;
    PORT
      LAYER M4 ;
        RECT  17.088 9.936 17.28 9.96 ;
    END
  END i[76]
  PIN i[77]
    DIRECTION INPUT ;
    USE SIGNAL ;
    PORT
      LAYER M4 ;
        RECT  17.088 10.08 17.28 10.104 ;
    END
  END i[77]
  PIN i[78]
    DIRECTION INPUT ;
    USE SIGNAL ;
    PORT
      LAYER M4 ;
        RECT  17.088 10.176 17.28 10.2 ;
    END
  END i[78]
  PIN i[79]
    DIRECTION INPUT ;
    USE SIGNAL ;
    PORT
      LAYER M4 ;
        RECT  17.088 10.272 17.28 10.296 ;
    END
  END i[79]
  PIN i[7]
    DIRECTION INPUT ;
    USE SIGNAL ;
    PORT
      LAYER M4 ;
        RECT  17.088 2.928 17.28 2.952 ;
    END
  END i[7]
  PIN i[80]
    DIRECTION INPUT ;
    USE SIGNAL ;
    PORT
      LAYER M4 ;
        RECT  17.088 10.368 17.28 10.392 ;
    END
  END i[80]
  PIN i[81]
    DIRECTION INPUT ;
    USE SIGNAL ;
    PORT
      LAYER M4 ;
        RECT  17.088 10.464 17.28 10.488 ;
    END
  END i[81]
  PIN i[82]
    DIRECTION INPUT ;
    USE SIGNAL ;
    PORT
      LAYER M4 ;
        RECT  17.088 10.56 17.28 10.584 ;
    END
  END i[82]
  PIN i[83]
    DIRECTION INPUT ;
    USE SIGNAL ;
    PORT
      LAYER M4 ;
        RECT  17.088 10.656 17.28 10.68 ;
    END
  END i[83]
  PIN i[84]
    DIRECTION INPUT ;
    USE SIGNAL ;
    PORT
      LAYER M4 ;
        RECT  17.088 10.752 17.28 10.776 ;
    END
  END i[84]
  PIN i[85]
    DIRECTION INPUT ;
    USE SIGNAL ;
    PORT
      LAYER M4 ;
        RECT  17.088 10.848 17.28 10.872 ;
    END
  END i[85]
  PIN i[86]
    DIRECTION INPUT ;
    USE SIGNAL ;
    PORT
      LAYER M4 ;
        RECT  17.088 10.992 17.28 11.016 ;
    END
  END i[86]
  PIN i[87]
    DIRECTION INPUT ;
    USE SIGNAL ;
    PORT
      LAYER M4 ;
        RECT  17.088 11.088 17.28 11.112 ;
    END
  END i[87]
  PIN i[88]
    DIRECTION INPUT ;
    USE SIGNAL ;
    PORT
      LAYER M4 ;
        RECT  17.088 11.184 17.28 11.208 ;
    END
  END i[88]
  PIN i[89]
    DIRECTION INPUT ;
    USE SIGNAL ;
    PORT
      LAYER M4 ;
        RECT  17.088 11.28 17.28 11.304 ;
    END
  END i[89]
  PIN i[8]
    DIRECTION INPUT ;
    USE SIGNAL ;
    PORT
      LAYER M4 ;
        RECT  17.088 3.024 17.28 3.048 ;
    END
  END i[8]
  PIN i[90]
    DIRECTION INPUT ;
    USE SIGNAL ;
    PORT
      LAYER M4 ;
        RECT  17.088 11.376 17.28 11.4 ;
    END
  END i[90]
  PIN i[91]
    DIRECTION INPUT ;
    USE SIGNAL ;
    PORT
      LAYER M4 ;
        RECT  17.088 11.472 17.28 11.496 ;
    END
  END i[91]
  PIN i[92]
    DIRECTION INPUT ;
    USE SIGNAL ;
    PORT
      LAYER M4 ;
        RECT  17.088 11.568 17.28 11.592 ;
    END
  END i[92]
  PIN i[93]
    DIRECTION INPUT ;
    USE SIGNAL ;
    PORT
      LAYER M4 ;
        RECT  17.088 11.664 17.28 11.688 ;
    END
  END i[93]
  PIN i[94]
    DIRECTION INPUT ;
    USE SIGNAL ;
    PORT
      LAYER M4 ;
        RECT  17.088 11.808 17.28 11.832 ;
    END
  END i[94]
  PIN i[95]
    DIRECTION INPUT ;
    USE SIGNAL ;
    PORT
      LAYER M4 ;
        RECT  17.088 11.904 17.28 11.928 ;
    END
  END i[95]
  PIN i[96]
    DIRECTION INPUT ;
    USE SIGNAL ;
    PORT
      LAYER M4 ;
        RECT  17.088 12 17.28 12.024 ;
    END
  END i[96]
  PIN i[97]
    DIRECTION INPUT ;
    USE SIGNAL ;
    PORT
      LAYER M4 ;
        RECT  17.088 12.096 17.28 12.12 ;
    END
  END i[97]
  PIN i[98]
    DIRECTION INPUT ;
    USE SIGNAL ;
    PORT
      LAYER M4 ;
        RECT  17.088 12.192 17.28 12.216 ;
    END
  END i[98]
  PIN i[99]
    DIRECTION INPUT ;
    USE SIGNAL ;
    PORT
      LAYER M4 ;
        RECT  17.088 12.288 17.28 12.312 ;
    END
  END i[99]
  PIN i[9]
    DIRECTION INPUT ;
    USE SIGNAL ;
    PORT
      LAYER M4 ;
        RECT  17.088 3.12 17.28 3.144 ;
    END
  END i[9]
  PIN o[0]
    DIRECTION OUTPUT ;
    USE SIGNAL ;
    PORT
      LAYER M4 ;
        RECT  0 2.208 0.192 2.232 ;
    END
  END o[0]
  PIN o[100]
    DIRECTION OUTPUT ;
    USE SIGNAL ;
    PORT
      LAYER M4 ;
        RECT  0 12.336 0.192 12.36 ;
    END
  END o[100]
  PIN o[101]
    DIRECTION OUTPUT ;
    USE SIGNAL ;
    PORT
      LAYER M4 ;
        RECT  0 12.48 0.192 12.504 ;
    END
  END o[101]
  PIN o[102]
    DIRECTION OUTPUT ;
    USE SIGNAL ;
    PORT
      LAYER M4 ;
        RECT  0 12.576 0.192 12.6 ;
    END
  END o[102]
  PIN o[103]
    DIRECTION OUTPUT ;
    USE SIGNAL ;
    PORT
      LAYER M4 ;
        RECT  0 12.672 0.192 12.696 ;
    END
  END o[103]
  PIN o[104]
    DIRECTION OUTPUT ;
    USE SIGNAL ;
    PORT
      LAYER M4 ;
        RECT  0 12.768 0.192 12.792 ;
    END
  END o[104]
  PIN o[105]
    DIRECTION OUTPUT ;
    USE SIGNAL ;
    PORT
      LAYER M4 ;
        RECT  0 12.864 0.192 12.888 ;
    END
  END o[105]
  PIN o[106]
    DIRECTION OUTPUT ;
    USE SIGNAL ;
    PORT
      LAYER M4 ;
        RECT  0 12.96 0.192 12.984 ;
    END
  END o[106]
  PIN o[107]
    DIRECTION OUTPUT ;
    USE SIGNAL ;
    PORT
      LAYER M4 ;
        RECT  0 13.056 0.192 13.08 ;
    END
  END o[107]
  PIN o[108]
    DIRECTION OUTPUT ;
    USE SIGNAL ;
    PORT
      LAYER M4 ;
        RECT  0 13.152 0.192 13.176 ;
    END
  END o[108]
  PIN o[109]
    DIRECTION OUTPUT ;
    USE SIGNAL ;
    PORT
      LAYER M4 ;
        RECT  0 13.296 0.192 13.32 ;
    END
  END o[109]
  PIN o[10]
    DIRECTION OUTPUT ;
    USE SIGNAL ;
    PORT
      LAYER M4 ;
        RECT  0 3.216 0.192 3.24 ;
    END
  END o[10]
  PIN o[110]
    DIRECTION OUTPUT ;
    USE SIGNAL ;
    PORT
      LAYER M4 ;
        RECT  0 13.392 0.192 13.416 ;
    END
  END o[110]
  PIN o[111]
    DIRECTION OUTPUT ;
    USE SIGNAL ;
    PORT
      LAYER M4 ;
        RECT  0 13.488 0.192 13.512 ;
    END
  END o[111]
  PIN o[112]
    DIRECTION OUTPUT ;
    USE SIGNAL ;
    PORT
      LAYER M4 ;
        RECT  0 13.584 0.192 13.608 ;
    END
  END o[112]
  PIN o[113]
    DIRECTION OUTPUT ;
    USE SIGNAL ;
    PORT
      LAYER M4 ;
        RECT  0 13.68 0.192 13.704 ;
    END
  END o[113]
  PIN o[114]
    DIRECTION OUTPUT ;
    USE SIGNAL ;
    PORT
      LAYER M4 ;
        RECT  0 13.776 0.192 13.8 ;
    END
  END o[114]
  PIN o[115]
    DIRECTION OUTPUT ;
    USE SIGNAL ;
    PORT
      LAYER M4 ;
        RECT  0 13.872 0.192 13.896 ;
    END
  END o[115]
  PIN o[116]
    DIRECTION OUTPUT ;
    USE SIGNAL ;
    PORT
      LAYER M4 ;
        RECT  0 13.968 0.192 13.992 ;
    END
  END o[116]
  PIN o[117]
    DIRECTION OUTPUT ;
    USE SIGNAL ;
    PORT
      LAYER M4 ;
        RECT  0 14.064 0.192 14.088 ;
    END
  END o[117]
  PIN o[118]
    DIRECTION OUTPUT ;
    USE SIGNAL ;
    PORT
      LAYER M4 ;
        RECT  0 14.208 0.192 14.232 ;
    END
  END o[118]
  PIN o[119]
    DIRECTION OUTPUT ;
    USE SIGNAL ;
    PORT
      LAYER M4 ;
        RECT  0 14.304 0.192 14.328 ;
    END
  END o[119]
  PIN o[11]
    DIRECTION OUTPUT ;
    USE SIGNAL ;
    PORT
      LAYER M4 ;
        RECT  0 3.36 0.192 3.384 ;
    END
  END o[11]
  PIN o[120]
    DIRECTION OUTPUT ;
    USE SIGNAL ;
    PORT
      LAYER M4 ;
        RECT  0 14.4 0.192 14.424 ;
    END
  END o[120]
  PIN o[121]
    DIRECTION OUTPUT ;
    USE SIGNAL ;
    PORT
      LAYER M4 ;
        RECT  0 14.496 0.192 14.52 ;
    END
  END o[121]
  PIN o[122]
    DIRECTION OUTPUT ;
    USE SIGNAL ;
    PORT
      LAYER M4 ;
        RECT  0 14.592 0.192 14.616 ;
    END
  END o[122]
  PIN o[123]
    DIRECTION OUTPUT ;
    USE SIGNAL ;
    PORT
      LAYER M4 ;
        RECT  0 14.688 0.192 14.712 ;
    END
  END o[123]
  PIN o[124]
    DIRECTION OUTPUT ;
    USE SIGNAL ;
    PORT
      LAYER M4 ;
        RECT  0 14.784 0.192 14.808 ;
    END
  END o[124]
  PIN o[125]
    DIRECTION OUTPUT ;
    USE SIGNAL ;
    PORT
      LAYER M4 ;
        RECT  0 14.88 0.192 14.904 ;
    END
  END o[125]
  PIN o[126]
    DIRECTION OUTPUT ;
    USE SIGNAL ;
    PORT
      LAYER M4 ;
        RECT  0 14.976 0.192 15 ;
    END
  END o[126]
  PIN o[127]
    DIRECTION OUTPUT ;
    USE SIGNAL ;
    PORT
      LAYER M4 ;
        RECT  0 15.12 0.192 15.144 ;
    END
  END o[127]
  PIN o[128]
    DIRECTION OUTPUT ;
    USE SIGNAL ;
    PORT
      LAYER M4 ;
        RECT  0 15.216 0.192 15.24 ;
    END
  END o[128]
  PIN o[129]
    DIRECTION OUTPUT ;
    USE SIGNAL ;
    PORT
      LAYER M4 ;
        RECT  0 15.312 0.192 15.336 ;
    END
  END o[129]
  PIN o[12]
    DIRECTION OUTPUT ;
    USE SIGNAL ;
    PORT
      LAYER M4 ;
        RECT  0 3.456 0.192 3.48 ;
    END
  END o[12]
  PIN o[130]
    DIRECTION OUTPUT ;
    USE SIGNAL ;
    PORT
      LAYER M4 ;
        RECT  0 15.408 0.192 15.432 ;
    END
  END o[130]
  PIN o[131]
    DIRECTION OUTPUT ;
    USE SIGNAL ;
    PORT
      LAYER M4 ;
        RECT  0 15.504 0.192 15.528 ;
    END
  END o[131]
  PIN o[132]
    DIRECTION OUTPUT ;
    USE SIGNAL ;
    PORT
      LAYER M4 ;
        RECT  0 15.6 0.192 15.624 ;
    END
  END o[132]
  PIN o[133]
    DIRECTION OUTPUT ;
    USE SIGNAL ;
    PORT
      LAYER M4 ;
        RECT  0 15.696 0.192 15.72 ;
    END
  END o[133]
  PIN o[134]
    DIRECTION OUTPUT ;
    USE SIGNAL ;
    PORT
      LAYER M4 ;
        RECT  0 15.792 0.192 15.816 ;
    END
  END o[134]
  PIN o[135]
    DIRECTION OUTPUT ;
    USE SIGNAL ;
    PORT
      LAYER M4 ;
        RECT  0 15.888 0.192 15.912 ;
    END
  END o[135]
  PIN o[136]
    DIRECTION OUTPUT ;
    USE SIGNAL ;
    PORT
      LAYER M4 ;
        RECT  0 16.032 0.192 16.056 ;
    END
  END o[136]
  PIN o[137]
    DIRECTION OUTPUT ;
    USE SIGNAL ;
    PORT
      LAYER M4 ;
        RECT  0 16.128 0.192 16.152 ;
    END
  END o[137]
  PIN o[138]
    DIRECTION OUTPUT ;
    USE SIGNAL ;
    PORT
      LAYER M4 ;
        RECT  0 16.32 0.192 16.344 ;
    END
  END o[138]
  PIN o[139]
    DIRECTION OUTPUT ;
    USE SIGNAL ;
    PORT
      LAYER M4 ;
        RECT  0 16.416 0.192 16.44 ;
    END
  END o[139]
  PIN o[13]
    DIRECTION OUTPUT ;
    USE SIGNAL ;
    PORT
      LAYER M4 ;
        RECT  0 3.552 0.192 3.576 ;
    END
  END o[13]
  PIN o[140]
    DIRECTION OUTPUT ;
    USE SIGNAL ;
    PORT
      LAYER M4 ;
        RECT  0 16.512 0.192 16.536 ;
    END
  END o[140]
  PIN o[141]
    DIRECTION OUTPUT ;
    USE SIGNAL ;
    PORT
      LAYER M4 ;
        RECT  0 16.608 0.192 16.632 ;
    END
  END o[141]
  PIN o[142]
    DIRECTION OUTPUT ;
    USE SIGNAL ;
    PORT
      LAYER M4 ;
        RECT  0 16.704 0.192 16.728 ;
    END
  END o[142]
  PIN o[143]
    DIRECTION OUTPUT ;
    USE SIGNAL ;
    PORT
      LAYER M4 ;
        RECT  0 16.8 0.192 16.824 ;
    END
  END o[143]
  PIN o[144]
    DIRECTION OUTPUT ;
    USE SIGNAL ;
    PORT
      LAYER M4 ;
        RECT  0 16.944 0.192 16.968 ;
    END
  END o[144]
  PIN o[145]
    DIRECTION OUTPUT ;
    USE SIGNAL ;
    PORT
      LAYER M4 ;
        RECT  0 17.04 0.192 17.064 ;
    END
  END o[145]
  PIN o[146]
    DIRECTION OUTPUT ;
    USE SIGNAL ;
    PORT
      LAYER M4 ;
        RECT  0 17.136 0.192 17.16 ;
    END
  END o[146]
  PIN o[147]
    DIRECTION OUTPUT ;
    USE SIGNAL ;
    PORT
      LAYER M4 ;
        RECT  0 17.232 0.192 17.256 ;
    END
  END o[147]
  PIN o[148]
    DIRECTION OUTPUT ;
    USE SIGNAL ;
    PORT
      LAYER M4 ;
        RECT  0 17.328 0.192 17.352 ;
    END
  END o[148]
  PIN o[149]
    DIRECTION OUTPUT ;
    USE SIGNAL ;
    PORT
      LAYER M4 ;
        RECT  0 17.424 0.192 17.448 ;
    END
  END o[149]
  PIN o[14]
    DIRECTION OUTPUT ;
    USE SIGNAL ;
    PORT
      LAYER M4 ;
        RECT  0 3.648 0.192 3.672 ;
    END
  END o[14]
  PIN o[150]
    DIRECTION OUTPUT ;
    USE SIGNAL ;
    PORT
      LAYER M4 ;
        RECT  0 17.52 0.192 17.544 ;
    END
  END o[150]
  PIN o[151]
    DIRECTION OUTPUT ;
    USE SIGNAL ;
    PORT
      LAYER M4 ;
        RECT  0 17.616 0.192 17.64 ;
    END
  END o[151]
  PIN o[152]
    DIRECTION OUTPUT ;
    USE SIGNAL ;
    PORT
      LAYER M4 ;
        RECT  0 17.712 0.192 17.736 ;
    END
  END o[152]
  PIN o[153]
    DIRECTION OUTPUT ;
    USE SIGNAL ;
    PORT
      LAYER M4 ;
        RECT  0 17.856 0.192 17.88 ;
    END
  END o[153]
  PIN o[154]
    DIRECTION OUTPUT ;
    USE SIGNAL ;
    PORT
      LAYER M4 ;
        RECT  0 17.952 0.192 17.976 ;
    END
  END o[154]
  PIN o[155]
    DIRECTION OUTPUT ;
    USE SIGNAL ;
    PORT
      LAYER M4 ;
        RECT  0 18.048 0.192 18.072 ;
    END
  END o[155]
  PIN o[156]
    DIRECTION OUTPUT ;
    USE SIGNAL ;
    PORT
      LAYER M4 ;
        RECT  0 18.144 0.192 18.168 ;
    END
  END o[156]
  PIN o[157]
    DIRECTION OUTPUT ;
    USE SIGNAL ;
    PORT
      LAYER M4 ;
        RECT  0 18.24 0.192 18.264 ;
    END
  END o[157]
  PIN o[158]
    DIRECTION OUTPUT ;
    USE SIGNAL ;
    PORT
      LAYER M4 ;
        RECT  0 18.336 0.192 18.36 ;
    END
  END o[158]
  PIN o[159]
    DIRECTION OUTPUT ;
    USE SIGNAL ;
    PORT
      LAYER M4 ;
        RECT  0 18.432 0.192 18.456 ;
    END
  END o[159]
  PIN o[15]
    DIRECTION OUTPUT ;
    USE SIGNAL ;
    PORT
      LAYER M4 ;
        RECT  0 3.744 0.192 3.768 ;
    END
  END o[15]
  PIN o[160]
    DIRECTION OUTPUT ;
    USE SIGNAL ;
    PORT
      LAYER M4 ;
        RECT  0 18.528 0.192 18.552 ;
    END
  END o[160]
  PIN o[161]
    DIRECTION OUTPUT ;
    USE SIGNAL ;
    PORT
      LAYER M4 ;
        RECT  0 18.624 0.192 18.648 ;
    END
  END o[161]
  PIN o[162]
    DIRECTION OUTPUT ;
    USE SIGNAL ;
    PORT
      LAYER M4 ;
        RECT  0 18.768 0.192 18.792 ;
    END
  END o[162]
  PIN o[163]
    DIRECTION OUTPUT ;
    USE SIGNAL ;
    PORT
      LAYER M4 ;
        RECT  0 18.864 0.192 18.888 ;
    END
  END o[163]
  PIN o[164]
    DIRECTION OUTPUT ;
    USE SIGNAL ;
    PORT
      LAYER M4 ;
        RECT  0 18.96 0.192 18.984 ;
    END
  END o[164]
  PIN o[165]
    DIRECTION OUTPUT ;
    USE SIGNAL ;
    PORT
      LAYER M4 ;
        RECT  0 19.056 0.192 19.08 ;
    END
  END o[165]
  PIN o[166]
    DIRECTION OUTPUT ;
    USE SIGNAL ;
    PORT
      LAYER M4 ;
        RECT  0 19.152 0.192 19.176 ;
    END
  END o[166]
  PIN o[167]
    DIRECTION OUTPUT ;
    USE SIGNAL ;
    PORT
      LAYER M4 ;
        RECT  0 19.248 0.192 19.272 ;
    END
  END o[167]
  PIN o[168]
    DIRECTION OUTPUT ;
    USE SIGNAL ;
    PORT
      LAYER M4 ;
        RECT  0 19.344 0.192 19.368 ;
    END
  END o[168]
  PIN o[169]
    DIRECTION OUTPUT ;
    USE SIGNAL ;
    PORT
      LAYER M4 ;
        RECT  0 19.44 0.192 19.464 ;
    END
  END o[169]
  PIN o[16]
    DIRECTION OUTPUT ;
    USE SIGNAL ;
    PORT
      LAYER M4 ;
        RECT  0 3.84 0.192 3.864 ;
    END
  END o[16]
  PIN o[170]
    DIRECTION OUTPUT ;
    USE SIGNAL ;
    PORT
      LAYER M4 ;
        RECT  0 19.536 0.192 19.56 ;
    END
  END o[170]
  PIN o[171]
    DIRECTION OUTPUT ;
    USE SIGNAL ;
    PORT
      LAYER M4 ;
        RECT  0 19.68 0.192 19.704 ;
    END
  END o[171]
  PIN o[172]
    DIRECTION OUTPUT ;
    USE SIGNAL ;
    PORT
      LAYER M4 ;
        RECT  0 19.776 0.192 19.8 ;
    END
  END o[172]
  PIN o[173]
    DIRECTION OUTPUT ;
    USE SIGNAL ;
    PORT
      LAYER M4 ;
        RECT  0 19.872 0.192 19.896 ;
    END
  END o[173]
  PIN o[174]
    DIRECTION OUTPUT ;
    USE SIGNAL ;
    PORT
      LAYER M4 ;
        RECT  0 19.968 0.192 19.992 ;
    END
  END o[174]
  PIN o[175]
    DIRECTION OUTPUT ;
    USE SIGNAL ;
    PORT
      LAYER M4 ;
        RECT  0 20.064 0.192 20.088 ;
    END
  END o[175]
  PIN o[176]
    DIRECTION OUTPUT ;
    USE SIGNAL ;
    PORT
      LAYER M4 ;
        RECT  0 20.16 0.192 20.184 ;
    END
  END o[176]
  PIN o[177]
    DIRECTION OUTPUT ;
    USE SIGNAL ;
    PORT
      LAYER M4 ;
        RECT  0 20.256 0.192 20.28 ;
    END
  END o[177]
  PIN o[178]
    DIRECTION OUTPUT ;
    USE SIGNAL ;
    PORT
      LAYER M4 ;
        RECT  0 20.352 0.192 20.376 ;
    END
  END o[178]
  PIN o[179]
    DIRECTION OUTPUT ;
    USE SIGNAL ;
    PORT
      LAYER M4 ;
        RECT  0 20.448 0.192 20.472 ;
    END
  END o[179]
  PIN o[17]
    DIRECTION OUTPUT ;
    USE SIGNAL ;
    PORT
      LAYER M4 ;
        RECT  0 3.936 0.192 3.96 ;
    END
  END o[17]
  PIN o[180]
    DIRECTION OUTPUT ;
    USE SIGNAL ;
    PORT
      LAYER M4 ;
        RECT  0 20.592 0.192 20.616 ;
    END
  END o[180]
  PIN o[181]
    DIRECTION OUTPUT ;
    USE SIGNAL ;
    PORT
      LAYER M4 ;
        RECT  0 20.688 0.192 20.712 ;
    END
  END o[181]
  PIN o[182]
    DIRECTION OUTPUT ;
    USE SIGNAL ;
    PORT
      LAYER M4 ;
        RECT  0 20.784 0.192 20.808 ;
    END
  END o[182]
  PIN o[183]
    DIRECTION OUTPUT ;
    USE SIGNAL ;
    PORT
      LAYER M4 ;
        RECT  0 20.88 0.192 20.904 ;
    END
  END o[183]
  PIN o[184]
    DIRECTION OUTPUT ;
    USE SIGNAL ;
    PORT
      LAYER M4 ;
        RECT  0 20.976 0.192 21 ;
    END
  END o[184]
  PIN o[185]
    DIRECTION OUTPUT ;
    USE SIGNAL ;
    PORT
      LAYER M4 ;
        RECT  0 21.072 0.192 21.096 ;
    END
  END o[185]
  PIN o[186]
    DIRECTION OUTPUT ;
    USE SIGNAL ;
    PORT
      LAYER M4 ;
        RECT  0 21.168 0.192 21.192 ;
    END
  END o[186]
  PIN o[187]
    DIRECTION OUTPUT ;
    USE SIGNAL ;
    PORT
      LAYER M4 ;
        RECT  0 21.264 0.192 21.288 ;
    END
  END o[187]
  PIN o[188]
    DIRECTION OUTPUT ;
    USE SIGNAL ;
    PORT
      LAYER M4 ;
        RECT  0 21.36 0.192 21.384 ;
    END
  END o[188]
  PIN o[189]
    DIRECTION OUTPUT ;
    USE SIGNAL ;
    PORT
      LAYER M4 ;
        RECT  0 21.504 0.192 21.528 ;
    END
  END o[189]
  PIN o[18]
    DIRECTION OUTPUT ;
    USE SIGNAL ;
    PORT
      LAYER M4 ;
        RECT  0 4.032 0.192 4.056 ;
    END
  END o[18]
  PIN o[190]
    DIRECTION OUTPUT ;
    USE SIGNAL ;
    PORT
      LAYER M4 ;
        RECT  0 21.6 0.192 21.624 ;
    END
  END o[190]
  PIN o[191]
    DIRECTION OUTPUT ;
    USE SIGNAL ;
    PORT
      LAYER M4 ;
        RECT  0 21.696 0.192 21.72 ;
    END
  END o[191]
  PIN o[192]
    DIRECTION OUTPUT ;
    USE SIGNAL ;
    PORT
      LAYER M4 ;
        RECT  0 21.792 0.192 21.816 ;
    END
  END o[192]
  PIN o[193]
    DIRECTION OUTPUT ;
    USE SIGNAL ;
    PORT
      LAYER M4 ;
        RECT  0 21.888 0.192 21.912 ;
    END
  END o[193]
  PIN o[194]
    DIRECTION OUTPUT ;
    USE SIGNAL ;
    PORT
      LAYER M4 ;
        RECT  0 21.984 0.192 22.008 ;
    END
  END o[194]
  PIN o[195]
    DIRECTION OUTPUT ;
    USE SIGNAL ;
    PORT
      LAYER M4 ;
        RECT  0 22.08 0.192 22.104 ;
    END
  END o[195]
  PIN o[196]
    DIRECTION OUTPUT ;
    USE SIGNAL ;
    PORT
      LAYER M4 ;
        RECT  0 22.176 0.192 22.2 ;
    END
  END o[196]
  PIN o[197]
    DIRECTION OUTPUT ;
    USE SIGNAL ;
    PORT
      LAYER M4 ;
        RECT  0 22.272 0.192 22.296 ;
    END
  END o[197]
  PIN o[198]
    DIRECTION OUTPUT ;
    USE SIGNAL ;
    PORT
      LAYER M4 ;
        RECT  0 22.416 0.192 22.44 ;
    END
  END o[198]
  PIN o[199]
    DIRECTION OUTPUT ;
    USE SIGNAL ;
    PORT
      LAYER M4 ;
        RECT  0 22.512 0.192 22.536 ;
    END
  END o[199]
  PIN o[19]
    DIRECTION OUTPUT ;
    USE SIGNAL ;
    PORT
      LAYER M4 ;
        RECT  0 4.128 0.192 4.152 ;
    END
  END o[19]
  PIN o[1]
    DIRECTION OUTPUT ;
    USE SIGNAL ;
    PORT
      LAYER M4 ;
        RECT  0 2.304 0.192 2.328 ;
    END
  END o[1]
  PIN o[200]
    DIRECTION OUTPUT ;
    USE SIGNAL ;
    PORT
      LAYER M4 ;
        RECT  0 22.608 0.192 22.632 ;
    END
  END o[200]
  PIN o[201]
    DIRECTION OUTPUT ;
    USE SIGNAL ;
    PORT
      LAYER M4 ;
        RECT  0 22.704 0.192 22.728 ;
    END
  END o[201]
  PIN o[202]
    DIRECTION OUTPUT ;
    USE SIGNAL ;
    PORT
      LAYER M4 ;
        RECT  0 22.8 0.192 22.824 ;
    END
  END o[202]
  PIN o[203]
    DIRECTION OUTPUT ;
    USE SIGNAL ;
    PORT
      LAYER M4 ;
        RECT  0 22.896 0.192 22.92 ;
    END
  END o[203]
  PIN o[204]
    DIRECTION OUTPUT ;
    USE SIGNAL ;
    PORT
      LAYER M4 ;
        RECT  0 22.992 0.192 23.016 ;
    END
  END o[204]
  PIN o[205]
    DIRECTION OUTPUT ;
    USE SIGNAL ;
    PORT
      LAYER M4 ;
        RECT  0 23.088 0.192 23.112 ;
    END
  END o[205]
  PIN o[206]
    DIRECTION OUTPUT ;
    USE SIGNAL ;
    PORT
      LAYER M4 ;
        RECT  0 23.184 0.192 23.208 ;
    END
  END o[206]
  PIN o[207]
    DIRECTION OUTPUT ;
    USE SIGNAL ;
    PORT
      LAYER M4 ;
        RECT  0 23.328 0.192 23.352 ;
    END
  END o[207]
  PIN o[208]
    DIRECTION OUTPUT ;
    USE SIGNAL ;
    PORT
      LAYER M4 ;
        RECT  0 23.424 0.192 23.448 ;
    END
  END o[208]
  PIN o[209]
    DIRECTION OUTPUT ;
    USE SIGNAL ;
    PORT
      LAYER M4 ;
        RECT  0 23.52 0.192 23.544 ;
    END
  END o[209]
  PIN o[20]
    DIRECTION OUTPUT ;
    USE SIGNAL ;
    PORT
      LAYER M4 ;
        RECT  0 4.272 0.192 4.296 ;
    END
  END o[20]
  PIN o[210]
    DIRECTION OUTPUT ;
    USE SIGNAL ;
    PORT
      LAYER M4 ;
        RECT  0 23.616 0.192 23.64 ;
    END
  END o[210]
  PIN o[211]
    DIRECTION OUTPUT ;
    USE SIGNAL ;
    PORT
      LAYER M4 ;
        RECT  0 23.712 0.192 23.736 ;
    END
  END o[211]
  PIN o[212]
    DIRECTION OUTPUT ;
    USE SIGNAL ;
    PORT
      LAYER M4 ;
        RECT  0 23.808 0.192 23.832 ;
    END
  END o[212]
  PIN o[213]
    DIRECTION OUTPUT ;
    USE SIGNAL ;
    PORT
      LAYER M4 ;
        RECT  0 23.904 0.192 23.928 ;
    END
  END o[213]
  PIN o[214]
    DIRECTION OUTPUT ;
    USE SIGNAL ;
    PORT
      LAYER M4 ;
        RECT  0 24 0.192 24.024 ;
    END
  END o[214]
  PIN o[215]
    DIRECTION OUTPUT ;
    USE SIGNAL ;
    PORT
      LAYER M4 ;
        RECT  0 24.096 0.192 24.12 ;
    END
  END o[215]
  PIN o[216]
    DIRECTION OUTPUT ;
    USE SIGNAL ;
    PORT
      LAYER M4 ;
        RECT  0 24.24 0.192 24.264 ;
    END
  END o[216]
  PIN o[217]
    DIRECTION OUTPUT ;
    USE SIGNAL ;
    PORT
      LAYER M4 ;
        RECT  0 24.336 0.192 24.36 ;
    END
  END o[217]
  PIN o[218]
    DIRECTION OUTPUT ;
    USE SIGNAL ;
    PORT
      LAYER M4 ;
        RECT  0 24.432 0.192 24.456 ;
    END
  END o[218]
  PIN o[219]
    DIRECTION OUTPUT ;
    USE SIGNAL ;
    PORT
      LAYER M4 ;
        RECT  0 24.528 0.192 24.552 ;
    END
  END o[219]
  PIN o[21]
    DIRECTION OUTPUT ;
    USE SIGNAL ;
    PORT
      LAYER M4 ;
        RECT  0 4.368 0.192 4.392 ;
    END
  END o[21]
  PIN o[220]
    DIRECTION OUTPUT ;
    USE SIGNAL ;
    PORT
      LAYER M4 ;
        RECT  0 24.624 0.192 24.648 ;
    END
  END o[220]
  PIN o[221]
    DIRECTION OUTPUT ;
    USE SIGNAL ;
    PORT
      LAYER M4 ;
        RECT  0 24.72 0.192 24.744 ;
    END
  END o[221]
  PIN o[222]
    DIRECTION OUTPUT ;
    USE SIGNAL ;
    PORT
      LAYER M4 ;
        RECT  0 24.816 0.192 24.84 ;
    END
  END o[222]
  PIN o[223]
    DIRECTION OUTPUT ;
    USE SIGNAL ;
    PORT
      LAYER M4 ;
        RECT  0 24.912 0.192 24.936 ;
    END
  END o[223]
  PIN o[224]
    DIRECTION OUTPUT ;
    USE SIGNAL ;
    PORT
      LAYER M4 ;
        RECT  0 25.008 0.192 25.032 ;
    END
  END o[224]
  PIN o[225]
    DIRECTION OUTPUT ;
    USE SIGNAL ;
    PORT
      LAYER M4 ;
        RECT  0 25.152 0.192 25.176 ;
    END
  END o[225]
  PIN o[226]
    DIRECTION OUTPUT ;
    USE SIGNAL ;
    PORT
      LAYER M4 ;
        RECT  0 25.248 0.192 25.272 ;
    END
  END o[226]
  PIN o[227]
    DIRECTION OUTPUT ;
    USE SIGNAL ;
    PORT
      LAYER M4 ;
        RECT  0 25.344 0.192 25.368 ;
    END
  END o[227]
  PIN o[228]
    DIRECTION OUTPUT ;
    USE SIGNAL ;
    PORT
      LAYER M4 ;
        RECT  0 25.44 0.192 25.464 ;
    END
  END o[228]
  PIN o[229]
    DIRECTION OUTPUT ;
    USE SIGNAL ;
    PORT
      LAYER M4 ;
        RECT  0 25.536 0.192 25.56 ;
    END
  END o[229]
  PIN o[22]
    DIRECTION OUTPUT ;
    USE SIGNAL ;
    PORT
      LAYER M4 ;
        RECT  0 4.464 0.192 4.488 ;
    END
  END o[22]
  PIN o[230]
    DIRECTION OUTPUT ;
    USE SIGNAL ;
    PORT
      LAYER M4 ;
        RECT  0 25.632 0.192 25.656 ;
    END
  END o[230]
  PIN o[231]
    DIRECTION OUTPUT ;
    USE SIGNAL ;
    PORT
      LAYER M4 ;
        RECT  0 25.728 0.192 25.752 ;
    END
  END o[231]
  PIN o[232]
    DIRECTION OUTPUT ;
    USE SIGNAL ;
    PORT
      LAYER M4 ;
        RECT  0 25.824 0.192 25.848 ;
    END
  END o[232]
  PIN o[233]
    DIRECTION OUTPUT ;
    USE SIGNAL ;
    PORT
      LAYER M4 ;
        RECT  0 25.92 0.192 25.944 ;
    END
  END o[233]
  PIN o[234]
    DIRECTION OUTPUT ;
    USE SIGNAL ;
    PORT
      LAYER M4 ;
        RECT  0 26.064 0.192 26.088 ;
    END
  END o[234]
  PIN o[235]
    DIRECTION OUTPUT ;
    USE SIGNAL ;
    PORT
      LAYER M4 ;
        RECT  0 26.16 0.192 26.184 ;
    END
  END o[235]
  PIN o[236]
    DIRECTION OUTPUT ;
    USE SIGNAL ;
    PORT
      LAYER M4 ;
        RECT  0 26.256 0.192 26.28 ;
    END
  END o[236]
  PIN o[237]
    DIRECTION OUTPUT ;
    USE SIGNAL ;
    PORT
      LAYER M4 ;
        RECT  0 26.352 0.192 26.376 ;
    END
  END o[237]
  PIN o[238]
    DIRECTION OUTPUT ;
    USE SIGNAL ;
    PORT
      LAYER M4 ;
        RECT  0 26.448 0.192 26.472 ;
    END
  END o[238]
  PIN o[239]
    DIRECTION OUTPUT ;
    USE SIGNAL ;
    PORT
      LAYER M4 ;
        RECT  0 26.544 0.192 26.568 ;
    END
  END o[239]
  PIN o[23]
    DIRECTION OUTPUT ;
    USE SIGNAL ;
    PORT
      LAYER M4 ;
        RECT  0 4.56 0.192 4.584 ;
    END
  END o[23]
  PIN o[240]
    DIRECTION OUTPUT ;
    USE SIGNAL ;
    PORT
      LAYER M4 ;
        RECT  0 26.64 0.192 26.664 ;
    END
  END o[240]
  PIN o[241]
    DIRECTION OUTPUT ;
    USE SIGNAL ;
    PORT
      LAYER M4 ;
        RECT  0 26.736 0.192 26.76 ;
    END
  END o[241]
  PIN o[242]
    DIRECTION OUTPUT ;
    USE SIGNAL ;
    PORT
      LAYER M4 ;
        RECT  0 26.88 0.192 26.904 ;
    END
  END o[242]
  PIN o[243]
    DIRECTION OUTPUT ;
    USE SIGNAL ;
    PORT
      LAYER M4 ;
        RECT  0 26.976 0.192 27 ;
    END
  END o[243]
  PIN o[244]
    DIRECTION OUTPUT ;
    USE SIGNAL ;
    PORT
      LAYER M4 ;
        RECT  0 27.072 0.192 27.096 ;
    END
  END o[244]
  PIN o[245]
    DIRECTION OUTPUT ;
    USE SIGNAL ;
    PORT
      LAYER M4 ;
        RECT  0 27.168 0.192 27.192 ;
    END
  END o[245]
  PIN o[246]
    DIRECTION OUTPUT ;
    USE SIGNAL ;
    PORT
      LAYER M4 ;
        RECT  0 27.264 0.192 27.288 ;
    END
  END o[246]
  PIN o[247]
    DIRECTION OUTPUT ;
    USE SIGNAL ;
    PORT
      LAYER M4 ;
        RECT  0 27.36 0.192 27.384 ;
    END
  END o[247]
  PIN o[248]
    DIRECTION OUTPUT ;
    USE SIGNAL ;
    PORT
      LAYER M4 ;
        RECT  0 27.456 0.192 27.48 ;
    END
  END o[248]
  PIN o[249]
    DIRECTION OUTPUT ;
    USE SIGNAL ;
    PORT
      LAYER M4 ;
        RECT  0 27.552 0.192 27.576 ;
    END
  END o[249]
  PIN o[24]
    DIRECTION OUTPUT ;
    USE SIGNAL ;
    PORT
      LAYER M4 ;
        RECT  0 4.656 0.192 4.68 ;
    END
  END o[24]
  PIN o[250]
    DIRECTION OUTPUT ;
    USE SIGNAL ;
    PORT
      LAYER M4 ;
        RECT  0 27.648 0.192 27.672 ;
    END
  END o[250]
  PIN o[251]
    DIRECTION OUTPUT ;
    USE SIGNAL ;
    PORT
      LAYER M4 ;
        RECT  0 27.792 0.192 27.816 ;
    END
  END o[251]
  PIN o[252]
    DIRECTION OUTPUT ;
    USE SIGNAL ;
    PORT
      LAYER M4 ;
        RECT  0 27.888 0.192 27.912 ;
    END
  END o[252]
  PIN o[253]
    DIRECTION OUTPUT ;
    USE SIGNAL ;
    PORT
      LAYER M4 ;
        RECT  0 27.984 0.192 28.008 ;
    END
  END o[253]
  PIN o[254]
    DIRECTION OUTPUT ;
    USE SIGNAL ;
    PORT
      LAYER M4 ;
        RECT  0 28.08 0.192 28.104 ;
    END
  END o[254]
  PIN o[255]
    DIRECTION OUTPUT ;
    USE SIGNAL ;
    PORT
      LAYER M4 ;
        RECT  0 28.176 0.192 28.2 ;
    END
  END o[255]
  PIN o[256]
    DIRECTION OUTPUT ;
    USE SIGNAL ;
    PORT
      LAYER M4 ;
        RECT  0 28.272 0.192 28.296 ;
    END
  END o[256]
  PIN o[257]
    DIRECTION OUTPUT ;
    USE SIGNAL ;
    PORT
      LAYER M4 ;
        RECT  0 28.368 0.192 28.392 ;
    END
  END o[257]
  PIN o[258]
    DIRECTION OUTPUT ;
    USE SIGNAL ;
    PORT
      LAYER M4 ;
        RECT  0 28.464 0.192 28.488 ;
    END
  END o[258]
  PIN o[259]
    DIRECTION OUTPUT ;
    USE SIGNAL ;
    PORT
      LAYER M4 ;
        RECT  0 28.56 0.192 28.584 ;
    END
  END o[259]
  PIN o[25]
    DIRECTION OUTPUT ;
    USE SIGNAL ;
    PORT
      LAYER M4 ;
        RECT  0 4.752 0.192 4.776 ;
    END
  END o[25]
  PIN o[260]
    DIRECTION OUTPUT ;
    USE SIGNAL ;
    PORT
      LAYER M4 ;
        RECT  0 28.704 0.192 28.728 ;
    END
  END o[260]
  PIN o[261]
    DIRECTION OUTPUT ;
    USE SIGNAL ;
    PORT
      LAYER M4 ;
        RECT  0 28.8 0.192 28.824 ;
    END
  END o[261]
  PIN o[262]
    DIRECTION OUTPUT ;
    USE SIGNAL ;
    PORT
      LAYER M4 ;
        RECT  0 28.896 0.192 28.92 ;
    END
  END o[262]
  PIN o[263]
    DIRECTION OUTPUT ;
    USE SIGNAL ;
    PORT
      LAYER M4 ;
        RECT  0 28.992 0.192 29.016 ;
    END
  END o[263]
  PIN o[264]
    DIRECTION OUTPUT ;
    USE SIGNAL ;
    PORT
      LAYER M4 ;
        RECT  0 29.088 0.192 29.112 ;
    END
  END o[264]
  PIN o[265]
    DIRECTION OUTPUT ;
    USE SIGNAL ;
    PORT
      LAYER M4 ;
        RECT  0 29.184 0.192 29.208 ;
    END
  END o[265]
  PIN o[266]
    DIRECTION OUTPUT ;
    USE SIGNAL ;
    PORT
      LAYER M4 ;
        RECT  0 29.28 0.192 29.304 ;
    END
  END o[266]
  PIN o[267]
    DIRECTION OUTPUT ;
    USE SIGNAL ;
    PORT
      LAYER M4 ;
        RECT  0 29.376 0.192 29.4 ;
    END
  END o[267]
  PIN o[268]
    DIRECTION OUTPUT ;
    USE SIGNAL ;
    PORT
      LAYER M4 ;
        RECT  0 29.472 0.192 29.496 ;
    END
  END o[268]
  PIN o[269]
    DIRECTION OUTPUT ;
    USE SIGNAL ;
    PORT
      LAYER M4 ;
        RECT  0 29.616 0.192 29.64 ;
    END
  END o[269]
  PIN o[26]
    DIRECTION OUTPUT ;
    USE SIGNAL ;
    PORT
      LAYER M4 ;
        RECT  0 4.848 0.192 4.872 ;
    END
  END o[26]
  PIN o[270]
    DIRECTION OUTPUT ;
    USE SIGNAL ;
    PORT
      LAYER M4 ;
        RECT  0 29.712 0.192 29.736 ;
    END
  END o[270]
  PIN o[271]
    DIRECTION OUTPUT ;
    USE SIGNAL ;
    PORT
      LAYER M4 ;
        RECT  0 29.808 0.192 29.832 ;
    END
  END o[271]
  PIN o[272]
    DIRECTION OUTPUT ;
    USE SIGNAL ;
    PORT
      LAYER M4 ;
        RECT  0 29.904 0.192 29.928 ;
    END
  END o[272]
  PIN o[273]
    DIRECTION OUTPUT ;
    USE SIGNAL ;
    PORT
      LAYER M4 ;
        RECT  0 30 0.192 30.024 ;
    END
  END o[273]
  PIN o[274]
    DIRECTION OUTPUT ;
    USE SIGNAL ;
    PORT
      LAYER M4 ;
        RECT  0 30.096 0.192 30.12 ;
    END
  END o[274]
  PIN o[275]
    DIRECTION OUTPUT ;
    USE SIGNAL ;
    PORT
      LAYER M4 ;
        RECT  0 30.192 0.192 30.216 ;
    END
  END o[275]
  PIN o[27]
    DIRECTION OUTPUT ;
    USE SIGNAL ;
    PORT
      LAYER M4 ;
        RECT  0 4.944 0.192 4.968 ;
    END
  END o[27]
  PIN o[28]
    DIRECTION OUTPUT ;
    USE SIGNAL ;
    PORT
      LAYER M4 ;
        RECT  0 5.04 0.192 5.064 ;
    END
  END o[28]
  PIN o[29]
    DIRECTION OUTPUT ;
    USE SIGNAL ;
    PORT
      LAYER M4 ;
        RECT  0 5.184 0.192 5.208 ;
    END
  END o[29]
  PIN o[2]
    DIRECTION OUTPUT ;
    USE SIGNAL ;
    PORT
      LAYER M4 ;
        RECT  0 2.448 0.192 2.472 ;
    END
  END o[2]
  PIN o[30]
    DIRECTION OUTPUT ;
    USE SIGNAL ;
    PORT
      LAYER M4 ;
        RECT  0 5.28 0.192 5.304 ;
    END
  END o[30]
  PIN o[31]
    DIRECTION OUTPUT ;
    USE SIGNAL ;
    PORT
      LAYER M4 ;
        RECT  0 5.376 0.192 5.4 ;
    END
  END o[31]
  PIN o[32]
    DIRECTION OUTPUT ;
    USE SIGNAL ;
    PORT
      LAYER M4 ;
        RECT  0 5.472 0.192 5.496 ;
    END
  END o[32]
  PIN o[33]
    DIRECTION OUTPUT ;
    USE SIGNAL ;
    PORT
      LAYER M4 ;
        RECT  0 5.568 0.192 5.592 ;
    END
  END o[33]
  PIN o[34]
    DIRECTION OUTPUT ;
    USE SIGNAL ;
    PORT
      LAYER M4 ;
        RECT  0 5.664 0.192 5.688 ;
    END
  END o[34]
  PIN o[35]
    DIRECTION OUTPUT ;
    USE SIGNAL ;
    PORT
      LAYER M4 ;
        RECT  0 5.76 0.192 5.784 ;
    END
  END o[35]
  PIN o[36]
    DIRECTION OUTPUT ;
    USE SIGNAL ;
    PORT
      LAYER M4 ;
        RECT  0 5.856 0.192 5.88 ;
    END
  END o[36]
  PIN o[37]
    DIRECTION OUTPUT ;
    USE SIGNAL ;
    PORT
      LAYER M4 ;
        RECT  0 5.952 0.192 5.976 ;
    END
  END o[37]
  PIN o[38]
    DIRECTION OUTPUT ;
    USE SIGNAL ;
    PORT
      LAYER M4 ;
        RECT  0 6.096 0.192 6.12 ;
    END
  END o[38]
  PIN o[39]
    DIRECTION OUTPUT ;
    USE SIGNAL ;
    PORT
      LAYER M4 ;
        RECT  0 6.192 0.192 6.216 ;
    END
  END o[39]
  PIN o[3]
    DIRECTION OUTPUT ;
    USE SIGNAL ;
    PORT
      LAYER M4 ;
        RECT  0 2.544 0.192 2.568 ;
    END
  END o[3]
  PIN o[40]
    DIRECTION OUTPUT ;
    USE SIGNAL ;
    PORT
      LAYER M4 ;
        RECT  0 6.288 0.192 6.312 ;
    END
  END o[40]
  PIN o[41]
    DIRECTION OUTPUT ;
    USE SIGNAL ;
    PORT
      LAYER M4 ;
        RECT  0 6.384 0.192 6.408 ;
    END
  END o[41]
  PIN o[42]
    DIRECTION OUTPUT ;
    USE SIGNAL ;
    PORT
      LAYER M4 ;
        RECT  0 6.48 0.192 6.504 ;
    END
  END o[42]
  PIN o[43]
    DIRECTION OUTPUT ;
    USE SIGNAL ;
    PORT
      LAYER M4 ;
        RECT  0 6.576 0.192 6.6 ;
    END
  END o[43]
  PIN o[44]
    DIRECTION OUTPUT ;
    USE SIGNAL ;
    PORT
      LAYER M4 ;
        RECT  0 6.672 0.192 6.696 ;
    END
  END o[44]
  PIN o[45]
    DIRECTION OUTPUT ;
    USE SIGNAL ;
    PORT
      LAYER M4 ;
        RECT  0 6.768 0.192 6.792 ;
    END
  END o[45]
  PIN o[46]
    DIRECTION OUTPUT ;
    USE SIGNAL ;
    PORT
      LAYER M4 ;
        RECT  0 6.864 0.192 6.888 ;
    END
  END o[46]
  PIN o[47]
    DIRECTION OUTPUT ;
    USE SIGNAL ;
    PORT
      LAYER M4 ;
        RECT  0 7.008 0.192 7.032 ;
    END
  END o[47]
  PIN o[48]
    DIRECTION OUTPUT ;
    USE SIGNAL ;
    PORT
      LAYER M4 ;
        RECT  0 7.104 0.192 7.128 ;
    END
  END o[48]
  PIN o[49]
    DIRECTION OUTPUT ;
    USE SIGNAL ;
    PORT
      LAYER M4 ;
        RECT  0 7.2 0.192 7.224 ;
    END
  END o[49]
  PIN o[4]
    DIRECTION OUTPUT ;
    USE SIGNAL ;
    PORT
      LAYER M4 ;
        RECT  0 2.64 0.192 2.664 ;
    END
  END o[4]
  PIN o[50]
    DIRECTION OUTPUT ;
    USE SIGNAL ;
    PORT
      LAYER M4 ;
        RECT  0 7.296 0.192 7.32 ;
    END
  END o[50]
  PIN o[51]
    DIRECTION OUTPUT ;
    USE SIGNAL ;
    PORT
      LAYER M4 ;
        RECT  0 7.392 0.192 7.416 ;
    END
  END o[51]
  PIN o[52]
    DIRECTION OUTPUT ;
    USE SIGNAL ;
    PORT
      LAYER M4 ;
        RECT  0 7.488 0.192 7.512 ;
    END
  END o[52]
  PIN o[53]
    DIRECTION OUTPUT ;
    USE SIGNAL ;
    PORT
      LAYER M4 ;
        RECT  0 7.584 0.192 7.608 ;
    END
  END o[53]
  PIN o[54]
    DIRECTION OUTPUT ;
    USE SIGNAL ;
    PORT
      LAYER M4 ;
        RECT  0 7.68 0.192 7.704 ;
    END
  END o[54]
  PIN o[55]
    DIRECTION OUTPUT ;
    USE SIGNAL ;
    PORT
      LAYER M4 ;
        RECT  0 7.776 0.192 7.8 ;
    END
  END o[55]
  PIN o[56]
    DIRECTION OUTPUT ;
    USE SIGNAL ;
    PORT
      LAYER M4 ;
        RECT  0 7.92 0.192 7.944 ;
    END
  END o[56]
  PIN o[57]
    DIRECTION OUTPUT ;
    USE SIGNAL ;
    PORT
      LAYER M4 ;
        RECT  0 8.016 0.192 8.04 ;
    END
  END o[57]
  PIN o[58]
    DIRECTION OUTPUT ;
    USE SIGNAL ;
    PORT
      LAYER M4 ;
        RECT  0 8.112 0.192 8.136 ;
    END
  END o[58]
  PIN o[59]
    DIRECTION OUTPUT ;
    USE SIGNAL ;
    PORT
      LAYER M4 ;
        RECT  0 8.208 0.192 8.232 ;
    END
  END o[59]
  PIN o[5]
    DIRECTION OUTPUT ;
    USE SIGNAL ;
    PORT
      LAYER M4 ;
        RECT  0 2.736 0.192 2.76 ;
    END
  END o[5]
  PIN o[60]
    DIRECTION OUTPUT ;
    USE SIGNAL ;
    PORT
      LAYER M4 ;
        RECT  0 8.304 0.192 8.328 ;
    END
  END o[60]
  PIN o[61]
    DIRECTION OUTPUT ;
    USE SIGNAL ;
    PORT
      LAYER M4 ;
        RECT  0 8.4 0.192 8.424 ;
    END
  END o[61]
  PIN o[62]
    DIRECTION OUTPUT ;
    USE SIGNAL ;
    PORT
      LAYER M4 ;
        RECT  0 8.496 0.192 8.52 ;
    END
  END o[62]
  PIN o[63]
    DIRECTION OUTPUT ;
    USE SIGNAL ;
    PORT
      LAYER M4 ;
        RECT  0 8.592 0.192 8.616 ;
    END
  END o[63]
  PIN o[64]
    DIRECTION OUTPUT ;
    USE SIGNAL ;
    PORT
      LAYER M4 ;
        RECT  0 8.688 0.192 8.712 ;
    END
  END o[64]
  PIN o[65]
    DIRECTION OUTPUT ;
    USE SIGNAL ;
    PORT
      LAYER M4 ;
        RECT  0 8.832 0.192 8.856 ;
    END
  END o[65]
  PIN o[66]
    DIRECTION OUTPUT ;
    USE SIGNAL ;
    PORT
      LAYER M4 ;
        RECT  0 8.928 0.192 8.952 ;
    END
  END o[66]
  PIN o[67]
    DIRECTION OUTPUT ;
    USE SIGNAL ;
    PORT
      LAYER M4 ;
        RECT  0 9.024 0.192 9.048 ;
    END
  END o[67]
  PIN o[68]
    DIRECTION OUTPUT ;
    USE SIGNAL ;
    PORT
      LAYER M4 ;
        RECT  0 9.12 0.192 9.144 ;
    END
  END o[68]
  PIN o[69]
    DIRECTION OUTPUT ;
    USE SIGNAL ;
    PORT
      LAYER M4 ;
        RECT  0 9.216 0.192 9.24 ;
    END
  END o[69]
  PIN o[6]
    DIRECTION OUTPUT ;
    USE SIGNAL ;
    PORT
      LAYER M4 ;
        RECT  0 2.832 0.192 2.856 ;
    END
  END o[6]
  PIN o[70]
    DIRECTION OUTPUT ;
    USE SIGNAL ;
    PORT
      LAYER M4 ;
        RECT  0 9.312 0.192 9.336 ;
    END
  END o[70]
  PIN o[71]
    DIRECTION OUTPUT ;
    USE SIGNAL ;
    PORT
      LAYER M4 ;
        RECT  0 9.408 0.192 9.432 ;
    END
  END o[71]
  PIN o[72]
    DIRECTION OUTPUT ;
    USE SIGNAL ;
    PORT
      LAYER M4 ;
        RECT  0 9.504 0.192 9.528 ;
    END
  END o[72]
  PIN o[73]
    DIRECTION OUTPUT ;
    USE SIGNAL ;
    PORT
      LAYER M4 ;
        RECT  0 9.6 0.192 9.624 ;
    END
  END o[73]
  PIN o[74]
    DIRECTION OUTPUT ;
    USE SIGNAL ;
    PORT
      LAYER M4 ;
        RECT  0 9.744 0.192 9.768 ;
    END
  END o[74]
  PIN o[75]
    DIRECTION OUTPUT ;
    USE SIGNAL ;
    PORT
      LAYER M4 ;
        RECT  0 9.84 0.192 9.864 ;
    END
  END o[75]
  PIN o[76]
    DIRECTION OUTPUT ;
    USE SIGNAL ;
    PORT
      LAYER M4 ;
        RECT  0 9.936 0.192 9.96 ;
    END
  END o[76]
  PIN o[77]
    DIRECTION OUTPUT ;
    USE SIGNAL ;
    PORT
      LAYER M4 ;
        RECT  0 10.032 0.192 10.056 ;
    END
  END o[77]
  PIN o[78]
    DIRECTION OUTPUT ;
    USE SIGNAL ;
    PORT
      LAYER M4 ;
        RECT  0 10.128 0.192 10.152 ;
    END
  END o[78]
  PIN o[79]
    DIRECTION OUTPUT ;
    USE SIGNAL ;
    PORT
      LAYER M4 ;
        RECT  0 10.224 0.192 10.248 ;
    END
  END o[79]
  PIN o[7]
    DIRECTION OUTPUT ;
    USE SIGNAL ;
    PORT
      LAYER M4 ;
        RECT  0 2.928 0.192 2.952 ;
    END
  END o[7]
  PIN o[80]
    DIRECTION OUTPUT ;
    USE SIGNAL ;
    PORT
      LAYER M4 ;
        RECT  0 10.32 0.192 10.344 ;
    END
  END o[80]
  PIN o[81]
    DIRECTION OUTPUT ;
    USE SIGNAL ;
    PORT
      LAYER M4 ;
        RECT  0 10.416 0.192 10.44 ;
    END
  END o[81]
  PIN o[82]
    DIRECTION OUTPUT ;
    USE SIGNAL ;
    PORT
      LAYER M4 ;
        RECT  0 10.512 0.192 10.536 ;
    END
  END o[82]
  PIN o[83]
    DIRECTION OUTPUT ;
    USE SIGNAL ;
    PORT
      LAYER M4 ;
        RECT  0 10.656 0.192 10.68 ;
    END
  END o[83]
  PIN o[84]
    DIRECTION OUTPUT ;
    USE SIGNAL ;
    PORT
      LAYER M4 ;
        RECT  0 10.752 0.192 10.776 ;
    END
  END o[84]
  PIN o[85]
    DIRECTION OUTPUT ;
    USE SIGNAL ;
    PORT
      LAYER M4 ;
        RECT  0 10.848 0.192 10.872 ;
    END
  END o[85]
  PIN o[86]
    DIRECTION OUTPUT ;
    USE SIGNAL ;
    PORT
      LAYER M4 ;
        RECT  0 10.944 0.192 10.968 ;
    END
  END o[86]
  PIN o[87]
    DIRECTION OUTPUT ;
    USE SIGNAL ;
    PORT
      LAYER M4 ;
        RECT  0 11.04 0.192 11.064 ;
    END
  END o[87]
  PIN o[88]
    DIRECTION OUTPUT ;
    USE SIGNAL ;
    PORT
      LAYER M4 ;
        RECT  0 11.136 0.192 11.16 ;
    END
  END o[88]
  PIN o[89]
    DIRECTION OUTPUT ;
    USE SIGNAL ;
    PORT
      LAYER M4 ;
        RECT  0 11.232 0.192 11.256 ;
    END
  END o[89]
  PIN o[8]
    DIRECTION OUTPUT ;
    USE SIGNAL ;
    PORT
      LAYER M4 ;
        RECT  0 3.024 0.192 3.048 ;
    END
  END o[8]
  PIN o[90]
    DIRECTION OUTPUT ;
    USE SIGNAL ;
    PORT
      LAYER M4 ;
        RECT  0 11.328 0.192 11.352 ;
    END
  END o[90]
  PIN o[91]
    DIRECTION OUTPUT ;
    USE SIGNAL ;
    PORT
      LAYER M4 ;
        RECT  0 11.424 0.192 11.448 ;
    END
  END o[91]
  PIN o[92]
    DIRECTION OUTPUT ;
    USE SIGNAL ;
    PORT
      LAYER M4 ;
        RECT  0 11.568 0.192 11.592 ;
    END
  END o[92]
  PIN o[93]
    DIRECTION OUTPUT ;
    USE SIGNAL ;
    PORT
      LAYER M4 ;
        RECT  0 11.664 0.192 11.688 ;
    END
  END o[93]
  PIN o[94]
    DIRECTION OUTPUT ;
    USE SIGNAL ;
    PORT
      LAYER M4 ;
        RECT  0 11.76 0.192 11.784 ;
    END
  END o[94]
  PIN o[95]
    DIRECTION OUTPUT ;
    USE SIGNAL ;
    PORT
      LAYER M4 ;
        RECT  0 11.856 0.192 11.88 ;
    END
  END o[95]
  PIN o[96]
    DIRECTION OUTPUT ;
    USE SIGNAL ;
    PORT
      LAYER M4 ;
        RECT  0 11.952 0.192 11.976 ;
    END
  END o[96]
  PIN o[97]
    DIRECTION OUTPUT ;
    USE SIGNAL ;
    PORT
      LAYER M4 ;
        RECT  0 12.048 0.192 12.072 ;
    END
  END o[97]
  PIN o[98]
    DIRECTION OUTPUT ;
    USE SIGNAL ;
    PORT
      LAYER M4 ;
        RECT  0 12.144 0.192 12.168 ;
    END
  END o[98]
  PIN o[99]
    DIRECTION OUTPUT ;
    USE SIGNAL ;
    PORT
      LAYER M4 ;
        RECT  0 12.24 0.192 12.264 ;
    END
  END o[99]
  PIN o[9]
    DIRECTION OUTPUT ;
    USE SIGNAL ;
    PORT
      LAYER M4 ;
        RECT  0 3.12 0.192 3.144 ;
    END
  END o[9]
  PIN rs
    DIRECTION INPUT ;
    USE SIGNAL ;
    PORT
      LAYER M5 ;
        RECT  11.856 32.208 11.88 32.4 ;
    END
    PORT
      LAYER M5 ;
        RECT  11.856 30.565 11.88 32.272 ;
    END
  END rs
  PIN VDD
    DIRECTION INOUT ;
    USE POWER ;
    PORT
      LAYER M5 ;
        RECT  13.392 2.151 13.512 30.249 ;
        RECT  10.692 2.151 10.812 30.249 ;
        RECT  7.992 2.151 8.112 30.249 ;
        RECT  5.292 2.151 5.412 30.249 ;
        RECT  2.592 2.151 2.712 30.249 ;
    END
  END VDD
  PIN VSS
    DIRECTION INOUT ;
    USE GROUND ;
    PORT
      LAYER M5 ;
        RECT  13.2 2.137 13.32 30.263 ;
        RECT  10.5 2.137 10.62 30.263 ;
        RECT  7.8 2.137 7.92 30.263 ;
        RECT  5.1 2.137 5.22 30.263 ;
        RECT  2.4 2.137 2.52 30.263 ;
    END
  END VSS
  # OT_OBS_CLOSED layer=M5 d_um=1.536 added=56
  OBS
    LAYER RVTN ;
     RECT  2.16 2.16 15.12 2.295 ;
     RECT  2.16 2.565 15.12 2.835 ;
     RECT  2.16 3.105 15.12 3.375 ;
     RECT  2.16 3.645 15.12 3.915 ;
     RECT  2.16 4.185 15.12 4.455 ;
     RECT  2.16 4.725 15.12 4.995 ;
     RECT  2.16 5.265 15.12 5.535 ;
     RECT  2.16 5.805 15.12 6.075 ;
     RECT  2.16 6.345 15.12 6.615 ;
     RECT  2.16 6.885 15.12 7.155 ;
     RECT  2.16 7.425 15.12 7.695 ;
     RECT  2.16 7.965 15.12 8.235 ;
     RECT  2.16 8.505 15.12 8.775 ;
     RECT  2.16 9.045 15.12 9.315 ;
     RECT  2.16 9.585 15.12 9.855 ;
     RECT  2.16 10.125 15.12 10.395 ;
     RECT  2.16 10.665 15.12 10.935 ;
     RECT  2.16 11.205 15.12 11.475 ;
     RECT  2.16 11.745 15.12 12.015 ;
     RECT  2.16 12.285 15.12 12.555 ;
     RECT  2.16 12.825 15.12 13.095 ;
     RECT  2.16 13.365 15.12 13.635 ;
     RECT  2.16 13.905 15.12 14.175 ;
     RECT  2.16 14.445 15.12 14.715 ;
     RECT  2.16 14.985 15.12 15.255 ;
     RECT  2.16 15.525 15.12 15.795 ;
     RECT  2.16 16.065 15.12 16.335 ;
     RECT  2.16 16.605 15.12 16.875 ;
     RECT  2.16 17.145 15.12 17.415 ;
     RECT  2.16 17.685 15.12 17.955 ;
     RECT  2.16 18.225 15.12 18.495 ;
     RECT  2.16 18.765 15.12 19.035 ;
     RECT  2.16 19.305 15.12 19.575 ;
     RECT  2.16 19.845 15.12 20.115 ;
     RECT  2.16 20.385 15.12 20.655 ;
     RECT  2.16 20.925 15.12 21.195 ;
     RECT  2.16 21.465 15.12 21.735 ;
     RECT  2.16 22.005 15.12 22.275 ;
     RECT  2.16 22.545 15.12 22.815 ;
     RECT  2.16 23.085 15.12 23.355 ;
     RECT  2.16 23.625 15.12 23.895 ;
     RECT  2.16 24.165 15.12 24.435 ;
     RECT  2.16 24.705 15.12 24.975 ;
     RECT  2.16 25.245 15.12 25.515 ;
     RECT  2.16 25.785 15.12 26.055 ;
     RECT  2.16 26.325 15.12 26.595 ;
     RECT  2.16 26.865 15.12 27.135 ;
     RECT  2.16 27.405 15.12 27.675 ;
     RECT  2.16 27.945 15.12 28.215 ;
     RECT  2.16 28.485 15.12 28.755 ;
     RECT  2.16 29.025 15.12 29.295 ;
     RECT  2.16 29.565 15.12 29.835 ;
     RECT  2.16 30.105 15.12 30.24 ;
    LAYER RVTP ;
     RECT  2.16 2.295 15.12 2.565 ;
     RECT  2.16 2.835 15.12 3.105 ;
     RECT  2.16 3.375 15.12 3.645 ;
     RECT  2.16 3.915 15.12 4.185 ;
     RECT  2.16 4.455 15.12 4.725 ;
     RECT  2.16 4.995 15.12 5.265 ;
     RECT  2.16 5.535 15.12 5.805 ;
     RECT  2.16 6.075 15.12 6.345 ;
     RECT  2.16 6.615 15.12 6.885 ;
     RECT  2.16 7.155 15.12 7.425 ;
     RECT  2.16 7.695 15.12 7.965 ;
     RECT  2.16 8.235 15.12 8.505 ;
     RECT  2.16 8.775 15.12 9.045 ;
     RECT  2.16 9.315 15.12 9.585 ;
     RECT  2.16 9.855 15.12 10.125 ;
     RECT  2.16 10.395 15.12 10.665 ;
     RECT  2.16 10.935 15.12 11.205 ;
     RECT  2.16 11.475 15.12 11.745 ;
     RECT  2.16 12.015 15.12 12.285 ;
     RECT  2.16 12.555 15.12 12.825 ;
     RECT  2.16 13.095 15.12 13.365 ;
     RECT  2.16 13.635 15.12 13.905 ;
     RECT  2.16 14.175 15.12 14.445 ;
     RECT  2.16 14.715 15.12 14.985 ;
     RECT  2.16 15.255 15.12 15.525 ;
     RECT  2.16 15.795 15.12 16.065 ;
     RECT  2.16 16.335 15.12 16.605 ;
     RECT  2.16 16.875 15.12 17.145 ;
     RECT  2.16 17.415 15.12 17.685 ;
     RECT  2.16 17.955 15.12 18.225 ;
     RECT  2.16 18.495 15.12 18.765 ;
     RECT  2.16 19.035 15.12 19.305 ;
     RECT  2.16 19.575 15.12 19.845 ;
     RECT  2.16 20.115 15.12 20.385 ;
     RECT  2.16 20.655 15.12 20.925 ;
     RECT  2.16 21.195 15.12 21.465 ;
     RECT  2.16 21.735 15.12 22.005 ;
     RECT  2.16 22.275 15.12 22.545 ;
     RECT  2.16 22.815 15.12 23.085 ;
     RECT  2.16 23.355 15.12 23.625 ;
     RECT  2.16 23.895 15.12 24.165 ;
     RECT  2.16 24.435 15.12 24.705 ;
     RECT  2.16 24.975 15.12 25.245 ;
     RECT  2.16 25.515 15.12 25.785 ;
     RECT  2.16 26.055 15.12 26.325 ;
     RECT  2.16 26.595 15.12 26.865 ;
     RECT  2.16 27.135 15.12 27.405 ;
     RECT  2.16 27.675 15.12 27.945 ;
     RECT  2.16 28.215 15.12 28.485 ;
     RECT  2.16 28.755 15.12 29.025 ;
     RECT  2.16 29.295 15.12 29.565 ;
     RECT  2.16 29.835 15.12 30.105 ;
    LAYER M1 ;
     RECT  2.16 2.151 15.12 30.249 ;
    LAYER M2 ;
     RECT  0.211 30.078 0.283 30.096 ;
     RECT  0.283 29.808 0.311 30.096 ;
     RECT  0.311 29.808 0.491 29.826 ;
     RECT  0.463 6.156 0.499 6.174 ;
     RECT  0.463 12.294 0.499 12.312 ;
     RECT  0.463 13.068 0.499 13.086 ;
     RECT  0.499 6.156 0.535 6.264 ;
     RECT  0.211 8.586 0.535 8.604 ;
     RECT  0.499 12.294 0.535 13.086 ;
     RECT  0.211 18.846 0.535 18.864 ;
     RECT  0.499 21.78 0.535 21.798 ;
     RECT  0.211 23.976 0.535 23.994 ;
     RECT  0.499 25.956 0.535 25.974 ;
     RECT  0.535 11.376 0.563 13.086 ;
     RECT  0.535 16.38 0.635 17.244 ;
     RECT  0.535 21.636 0.635 24.354 ;
     RECT  0.535 3.078 1.975 3.096 ;
     RECT  0.535 14.076 1.975 14.094 ;
     RECT  1.975 3.078 2.16 3.834 ;
     RECT  0.535 6.12 2.16 6.264 ;
     RECT  0.535 8.586 2.16 9.036 ;
     RECT  0.563 11.376 2.16 12.852 ;
     RECT  1.975 13.644 2.16 14.094 ;
     RECT  0.635 16.38 2.16 16.938 ;
     RECT  0.535 18.126 2.16 18.864 ;
     RECT  0.635 21.636 2.16 22.5 ;
     RECT  0.635 23.256 2.16 24.354 ;
     RECT  0.535 25.488 2.16 27.864 ;
     RECT  2.16 2.151 3.667 30.249 ;
     RECT  3.667 2.151 3.739 30.789 ;
     RECT  3.739 2.151 3.811 30.834 ;
     RECT  3.811 2.106 4.171 30.834 ;
     RECT  4.171 1.692 7.483 30.834 ;
     RECT  7.483 1.656 13.811 30.834 ;
     RECT  13.811 1.656 15.12 30.294 ;
     RECT  15.12 23.868 15.395 27.936 ;
     RECT  15.12 3.15 15.431 4.518 ;
     RECT  15.12 5.274 15.431 7.956 ;
     RECT  15.12 8.748 15.431 22.806 ;
     RECT  15.395 23.904 15.431 27.936 ;
     RECT  15.12 28.728 15.431 28.746 ;
     RECT  15.12 29.61 15.431 30.294 ;
     RECT  15.431 3.42 15.467 3.438 ;
     RECT  15.431 5.31 15.467 7.38 ;
     RECT  15.431 11.682 15.467 14.742 ;
     RECT  15.431 17.388 15.467 17.64 ;
     RECT  15.431 18.468 15.467 18.486 ;
     RECT  15.467 5.31 15.503 5.76 ;
     RECT  15.12 1.656 16.007 2.286 ;
     RECT  16.007 1.656 16.547 2.052 ;
     RECT  15.503 5.616 16.547 5.76 ;
     RECT  15.467 6.624 16.547 7.38 ;
     RECT  15.431 9.054 16.547 9.072 ;
     RECT  15.431 9.828 16.547 9.846 ;
     RECT  15.431 10.836 16.547 10.926 ;
     RECT  15.467 12.798 16.547 14.742 ;
     RECT  15.431 15.57 16.547 16.128 ;
     RECT  15.431 20.16 16.547 21.186 ;
     RECT  15.431 25.02 16.547 27.36 ;
     RECT  15.431 30.276 16.547 30.294 ;
     RECT  16.547 10.836 16.583 10.854 ;
     RECT  15.467 11.682 16.583 11.7 ;
     RECT  16.547 14.724 16.583 14.742 ;
     RECT  15.467 17.496 16.583 17.64 ;
     RECT  16.547 25.29 16.583 26.118 ;
     RECT  16.583 25.758 16.619 25.776 ;
     RECT  16.547 21.006 17.059 21.186 ;
     RECT  16.547 27.306 17.059 27.36 ;
     RECT  16.547 1.656 17.123 1.674 ;
     RECT  16.547 6.858 17.123 6.876 ;
     RECT  17.059 3.924 17.159 3.942 ;
     RECT  17.059 8.136 17.159 8.964 ;
     RECT  17.059 10.098 17.159 10.116 ;
     RECT  17.059 14.958 17.159 14.976 ;
     RECT  17.059 16.578 17.159 16.974 ;
     RECT  17.059 18.162 17.159 18.18 ;
     RECT  17.059 21.006 17.159 22.032 ;
     RECT  17.059 27.306 17.159 28.404 ;
     RECT  17.059 29.538 17.159 30.06 ;
    LAYER M3 ;
     RECT  17.1 1.651 17.118 2.029 ;
     RECT  4.176 1.687 4.194 2.101 ;
     RECT  13.788 1.687 13.806 2.101 ;
     RECT  7.488 1.651 7.506 2.143 ;
     RECT  8.244 2.029 8.262 2.143 ;
     RECT  13.608 2.101 13.806 2.143 ;
     RECT  2.415 2.143 2.505 2.191 ;
     RECT  10.515 2.143 10.605 2.191 ;
     RECT  13.215 2.143 13.806 2.227 ;
     RECT  16.524 2.029 17.118 2.263 ;
     RECT  5.115 2.143 5.205 2.299 ;
     RECT  7.488 2.143 8.262 2.299 ;
     RECT  9.54 2.227 9.558 2.299 ;
     RECT  12.276 2.293 12.294 2.299 ;
     RECT  13.068 2.227 13.806 2.299 ;
     RECT  15.984 2.263 17.118 2.333 ;
     RECT  3.816 2.101 4.194 2.335 ;
     RECT  5.115 2.299 5.238 2.335 ;
     RECT  10.515 2.191 11.106 2.335 ;
     RECT  12.204 2.299 12.294 2.335 ;
     RECT  7.488 2.299 9.666 2.347 ;
     RECT  2.304 2.191 2.505 2.371 ;
     RECT  3.816 2.335 5.238 2.371 ;
     RECT  10.515 2.335 12.294 2.371 ;
     RECT  13.068 2.299 13.842 2.371 ;
     RECT  2.304 2.371 5.238 2.413 ;
     RECT  15.984 2.333 16.002 2.477 ;
     RECT  7.416 2.347 9.666 2.497 ;
     RECT  10.515 2.371 14.094 2.497 ;
     RECT  7.416 2.497 14.094 2.531 ;
     RECT  14.832 2.203 14.85 2.533 ;
     RECT  7.416 2.531 11.79 2.587 ;
     RECT  2.304 2.413 5.397 2.731 ;
     RECT  6.84 2.587 11.79 2.759 ;
     RECT  2.196 2.731 5.397 2.861 ;
     RECT  6.84 2.759 11.43 2.875 ;
     RECT  2.304 2.861 5.397 2.957 ;
     RECT  14.832 2.533 14.886 3.019 ;
     RECT  6.12 2.875 11.43 3.029 ;
     RECT  0.252 2.635 0.27 3.073 ;
     RECT  12.564 2.531 14.094 3.181 ;
     RECT  14.832 3.019 15.426 3.181 ;
     RECT  0.252 3.073 0.558 3.245 ;
     RECT  6.192 3.029 11.43 3.341 ;
     RECT  12.564 3.181 15.426 3.371 ;
     RECT  14.832 3.371 15.426 3.415 ;
     RECT  0.54 3.245 0.558 3.485 ;
     RECT  6.516 3.341 11.43 3.577 ;
     RECT  12.564 3.371 13.914 3.577 ;
     RECT  14.832 3.415 15.462 3.581 ;
     RECT  6.516 3.577 13.914 3.725 ;
     RECT  2.415 2.957 5.397 3.739 ;
     RECT  1.98 3.739 5.397 3.839 ;
     RECT  17.1 2.333 17.118 3.883 ;
     RECT  17.1 3.883 17.154 3.919 ;
     RECT  17.064 3.919 17.154 3.947 ;
     RECT  17.064 3.947 17.118 3.965 ;
     RECT  7.416 3.725 13.914 3.983 ;
     RECT  2.268 3.839 5.397 3.991 ;
     RECT  6.516 3.725 6.534 4.219 ;
     RECT  2.268 3.991 5.454 4.261 ;
     RECT  6.228 4.219 6.534 4.261 ;
     RECT  2.268 4.261 6.534 4.451 ;
     RECT  2.304 4.451 6.534 4.459 ;
     RECT  2.304 4.459 6.678 4.495 ;
     RECT  7.416 3.983 13.842 4.495 ;
     RECT  2.304 4.495 13.842 4.523 ;
     RECT  0.252 4.555 0.27 4.733 ;
     RECT  3.924 4.523 13.842 4.801 ;
     RECT  17.1 3.965 17.118 4.939 ;
     RECT  3.924 4.801 14.058 5.071 ;
     RECT  14.832 3.581 15.426 5.071 ;
     RECT  3.924 5.071 15.426 5.083 ;
     RECT  3.924 5.083 15.498 5.213 ;
     RECT  2.304 4.523 3.006 5.333 ;
     RECT  14.688 5.213 15.498 5.333 ;
     RECT  2.304 5.333 2.934 5.369 ;
     RECT  3.924 5.213 13.914 5.567 ;
     RECT  3.924 5.567 5.994 5.603 ;
     RECT  5.115 5.603 5.994 5.639 ;
     RECT  16.524 4.939 17.118 5.789 ;
     RECT  3.924 5.603 4.194 6.043 ;
     RECT  2.304 5.369 2.862 6.115 ;
     RECT  3.708 6.043 4.194 6.115 ;
     RECT  0.54 6.115 0.558 6.151 ;
     RECT  14.688 5.333 15.066 6.187 ;
     RECT  5.115 5.639 5.706 6.269 ;
     RECT  14.688 6.187 15.426 6.269 ;
     RECT  14.832 6.269 15.426 6.283 ;
     RECT  0.468 6.151 0.558 6.317 ;
     RECT  0.468 6.317 0.522 6.413 ;
     RECT  14.832 6.283 15.462 6.413 ;
     RECT  2.304 6.115 4.194 6.421 ;
     RECT  5.115 6.269 5.562 6.421 ;
     RECT  17.1 5.789 17.118 6.619 ;
     RECT  6.768 5.567 13.914 6.691 ;
     RECT  0.504 6.413 0.522 6.701 ;
     RECT  6.768 6.691 13.986 6.808 ;
     RECT  2.304 6.421 5.562 6.809 ;
     RECT  6.624 6.808 13.986 6.811 ;
     RECT  6.408 6.811 13.986 6.851 ;
     RECT  16.524 6.619 17.118 6.881 ;
     RECT  14.832 6.413 14.958 7.181 ;
     RECT  6.804 6.851 13.986 7.231 ;
     RECT  14.832 7.181 14.922 7.231 ;
     RECT  6.804 7.231 14.922 7.373 ;
     RECT  2.304 6.809 2.697 7.591 ;
     RECT  3.42 6.809 5.397 7.591 ;
     RECT  6.228 7.699 6.246 7.889 ;
     RECT  7.128 7.373 14.922 7.915 ;
     RECT  7.128 7.915 15.426 7.961 ;
     RECT  7.128 7.961 14.922 8.045 ;
     RECT  16.524 6.881 17.046 8.045 ;
     RECT  17.028 8.045 17.046 8.107 ;
     RECT  2.304 7.591 5.397 8.131 ;
     RECT  17.028 8.107 17.082 8.131 ;
     RECT  2.304 8.131 5.562 8.159 ;
     RECT  7.128 8.045 13.842 8.167 ;
     RECT  7.02 8.167 13.842 8.401 ;
     RECT  0.216 8.581 0.234 8.621 ;
     RECT  3.96 8.159 5.562 8.707 ;
     RECT  6.804 8.401 13.842 8.707 ;
     RECT  14.832 8.045 14.922 8.731 ;
     RECT  3.96 8.707 13.842 8.851 ;
     RECT  14.832 8.731 15.426 8.851 ;
     RECT  2.304 8.159 3.006 8.941 ;
     RECT  17.028 8.131 17.154 9.005 ;
     RECT  3.96 8.851 15.426 9.053 ;
     RECT  2.304 8.941 3.186 9.067 ;
     RECT  3.96 9.053 13.842 9.067 ;
     RECT  2.304 9.067 13.842 9.113 ;
     RECT  14.616 9.053 15.426 9.239 ;
     RECT  6.444 9.113 13.842 9.275 ;
     RECT  6.66 9.275 13.842 9.311 ;
     RECT  0.54 9.013 0.558 9.533 ;
     RECT  16.524 9.019 16.614 9.869 ;
     RECT  2.304 9.113 5.397 9.931 ;
     RECT  16.596 9.869 16.614 10.075 ;
     RECT  7.236 9.311 13.842 10.093 ;
     RECT  16.596 10.075 17.082 10.093 ;
     RECT  16.596 10.093 17.154 10.157 ;
     RECT  2.304 9.931 5.706 10.219 ;
     RECT  1.98 10.219 5.706 10.291 ;
     RECT  1.98 10.291 5.778 10.397 ;
     RECT  2.304 10.397 5.778 10.471 ;
     RECT  7.02 10.093 13.842 10.471 ;
     RECT  14.832 9.239 15.426 10.471 ;
     RECT  16.596 10.157 16.614 10.651 ;
     RECT  7.02 10.471 15.426 10.661 ;
     RECT  2.304 10.471 6.282 10.741 ;
     RECT  7.02 10.661 13.914 10.741 ;
     RECT  2.304 10.741 13.914 10.877 ;
     RECT  2.412 10.877 13.914 10.925 ;
     RECT  2.412 10.925 6.174 10.931 ;
     RECT  16.524 10.651 16.614 11.021 ;
     RECT  14.832 10.661 15.426 11.309 ;
     RECT  0.252 11.179 0.27 11.357 ;
     RECT  7.236 10.925 13.914 11.467 ;
     RECT  16.524 11.021 16.578 11.705 ;
     RECT  7.236 11.467 14.598 11.707 ;
     RECT  2.412 10.931 5.994 11.755 ;
     RECT  16.524 11.705 16.542 11.789 ;
     RECT  15.408 11.309 15.426 11.821 ;
     RECT  2.304 11.755 5.994 11.849 ;
     RECT  0.288 11.371 0.558 11.981 ;
     RECT  6.804 11.707 14.598 12.043 ;
     RECT  15.408 11.821 15.462 12.043 ;
     RECT  2.412 11.849 5.994 12.181 ;
     RECT  6.804 12.043 15.462 12.353 ;
     RECT  7.236 12.353 15.462 12.389 ;
     RECT  7.236 12.389 15.426 12.509 ;
     RECT  14.508 12.509 15.426 12.515 ;
     RECT  16.524 12.619 16.542 12.811 ;
     RECT  16.488 12.811 16.542 12.857 ;
     RECT  2.412 12.181 6.066 12.859 ;
     RECT  2.304 12.859 6.066 12.901 ;
     RECT  0.468 11.981 0.558 13.102 ;
     RECT  2.268 12.901 6.282 13.171 ;
     RECT  7.236 12.509 13.698 13.171 ;
     RECT  0.504 13.102 0.558 13.181 ;
     RECT  14.832 12.515 15.426 13.195 ;
     RECT  0.504 13.181 0.522 13.325 ;
     RECT  2.268 13.171 13.698 13.361 ;
     RECT  14.832 13.195 15.462 13.433 ;
     RECT  2.268 13.361 2.697 13.441 ;
     RECT  3.528 13.361 13.698 13.531 ;
     RECT  14.832 13.433 15.426 13.531 ;
     RECT  3.528 13.531 15.426 13.559 ;
     RECT  3.636 13.559 15.426 13.631 ;
     RECT  2.196 13.441 2.697 13.639 ;
     RECT  3.636 13.631 14.958 13.667 ;
     RECT  1.98 13.639 2.697 13.805 ;
     RECT  3.636 13.667 5.958 13.973 ;
     RECT  3.672 13.973 5.958 14.099 ;
     RECT  6.768 13.667 14.958 14.099 ;
     RECT  6.768 14.099 13.842 14.141 ;
     RECT  5.115 14.099 5.958 14.171 ;
     RECT  0.54 14.071 0.558 14.429 ;
     RECT  14.76 14.099 14.958 14.443 ;
     RECT  16.524 12.857 16.542 14.513 ;
     RECT  6.768 14.141 13.734 14.549 ;
     RECT  0.288 14.443 0.414 14.717 ;
     RECT  3.672 14.099 4.374 14.731 ;
     RECT  2.304 13.805 2.697 14.881 ;
     RECT  16.56 14.539 16.578 14.923 ;
     RECT  16.56 14.923 17.082 14.953 ;
     RECT  5.115 14.171 5.454 14.981 ;
     RECT  16.56 14.953 17.154 15.005 ;
     RECT  2.304 14.881 2.826 15.025 ;
     RECT  3.6 14.731 4.374 15.025 ;
     RECT  14.76 14.443 15.426 15.061 ;
     RECT  2.304 15.025 4.374 15.151 ;
     RECT  5.115 14.981 5.397 15.151 ;
     RECT  16.56 15.005 16.578 15.259 ;
     RECT  14.4 15.061 15.426 15.287 ;
     RECT  6.768 14.549 13.662 15.295 ;
     RECT  16.524 15.259 16.578 15.389 ;
     RECT  6.516 15.295 13.662 15.529 ;
     RECT  0.252 15.739 0.27 15.917 ;
     RECT  6.264 15.529 13.662 15.961 ;
     RECT  2.304 15.151 5.397 15.979 ;
     RECT  6.264 15.961 13.77 16.069 ;
     RECT  14.724 15.287 15.426 16.069 ;
     RECT  2.304 15.979 5.454 16.123 ;
     RECT  16.524 15.389 16.542 16.133 ;
     RECT  2.232 16.123 5.454 16.231 ;
     RECT  6.264 16.069 15.426 16.231 ;
     RECT  2.232 16.231 15.426 16.259 ;
     RECT  2.232 16.259 13.878 16.403 ;
     RECT  2.232 16.403 5.706 16.501 ;
     RECT  2.196 16.501 5.706 16.541 ;
     RECT  2.304 16.541 5.706 16.565 ;
     RECT  17.064 16.555 17.082 16.573 ;
     RECT  6.516 16.403 13.878 16.589 ;
     RECT  0.54 16.375 0.558 16.651 ;
     RECT  0.54 16.651 0.63 16.843 ;
     RECT  2.304 16.565 5.562 16.907 ;
     RECT  17.064 16.573 17.154 16.979 ;
     RECT  17.064 16.979 17.082 17.021 ;
     RECT  2.304 16.907 5.49 17.069 ;
     RECT  14.832 16.259 15.426 17.221 ;
     RECT  0.54 16.843 1.17 17.261 ;
     RECT  14.796 17.221 15.426 17.275 ;
     RECT  1.152 17.261 1.17 17.323 ;
     RECT  14.796 17.275 15.462 17.411 ;
     RECT  6.516 16.589 13.698 17.483 ;
     RECT  12.276 17.483 13.698 17.491 ;
     RECT  14.796 17.411 15.426 17.491 ;
     RECT  16.56 17.491 16.578 17.563 ;
     RECT  12.276 17.491 15.426 17.645 ;
     RECT  16.524 17.563 16.578 17.645 ;
     RECT  16.56 17.645 16.578 17.693 ;
     RECT  6.516 17.483 11.394 17.761 ;
     RECT  12.348 17.645 15.426 17.789 ;
     RECT  2.304 17.069 5.454 17.923 ;
     RECT  6.264 17.761 11.394 17.923 ;
     RECT  2.304 17.923 11.394 17.933 ;
     RECT  1.152 17.323 1.278 18.121 ;
     RECT  0.54 18.121 1.278 18.173 ;
     RECT  17.064 18.139 17.154 18.185 ;
     RECT  17.064 18.185 17.082 18.221 ;
     RECT  0.54 18.173 0.558 18.269 ;
     RECT  12.528 17.789 15.426 18.269 ;
     RECT  2.304 17.933 5.778 18.365 ;
     RECT  6.516 17.933 11.394 18.391 ;
     RECT  2.412 18.365 5.778 18.419 ;
     RECT  14.58 18.269 15.426 18.463 ;
     RECT  14.58 18.463 15.462 18.509 ;
     RECT  12.528 18.269 13.59 18.535 ;
     RECT  6.516 18.391 11.718 18.571 ;
     RECT  12.492 18.535 13.59 18.571 ;
     RECT  2.412 18.419 5.397 18.599 ;
     RECT  6.516 18.571 13.59 18.733 ;
     RECT  6.264 18.733 13.59 18.797 ;
     RECT  0.216 18.841 0.234 18.893 ;
     RECT  14.58 18.509 15.426 19.051 ;
     RECT  6.696 18.797 13.59 19.111 ;
     RECT  14.472 19.051 15.426 19.111 ;
     RECT  2.412 18.599 2.97 19.147 ;
     RECT  6.696 19.111 15.426 19.229 ;
     RECT  3.96 18.599 5.397 19.277 ;
     RECT  14.724 19.229 15.426 19.325 ;
     RECT  2.304 19.147 2.97 19.471 ;
     RECT  3.96 19.277 4.014 19.471 ;
     RECT  6.696 19.229 13.986 19.543 ;
     RECT  6.264 19.543 13.986 19.661 ;
     RECT  0.252 19.579 0.27 19.723 ;
     RECT  0.252 19.723 0.342 19.901 ;
     RECT  6.696 19.661 13.986 19.949 ;
     RECT  2.304 19.471 4.014 20.011 ;
     RECT  4.824 19.277 5.397 20.011 ;
     RECT  2.304 20.011 5.397 20.039 ;
     RECT  2.415 20.039 5.397 20.059 ;
     RECT  2.415 20.059 5.742 20.111 ;
     RECT  14.832 19.325 15.426 20.111 ;
     RECT  6.696 19.949 13.914 20.183 ;
     RECT  6.696 20.183 11.682 20.731 ;
     RECT  12.564 20.183 13.914 20.731 ;
     RECT  14.832 20.111 14.958 20.731 ;
     RECT  2.415 20.111 5.397 20.779 ;
     RECT  6.228 20.731 11.682 20.923 ;
     RECT  12.564 20.731 14.958 20.923 ;
     RECT  16.524 20.107 16.542 20.923 ;
     RECT  16.524 20.923 16.578 20.971 ;
     RECT  2.304 20.779 5.397 21.091 ;
     RECT  0.252 19.901 0.27 21.101 ;
     RECT  6.228 20.923 14.958 21.259 ;
     RECT  2.304 21.091 5.454 21.271 ;
     RECT  6.228 21.259 15.426 21.271 ;
     RECT  2.304 21.271 15.426 21.542 ;
     RECT  6.228 21.542 15.426 21.569 ;
     RECT  2.304 21.542 5.49 21.659 ;
     RECT  16.524 20.971 17.154 21.725 ;
     RECT  0.504 21.631 0.558 21.931 ;
     RECT  0.504 21.931 1.17 22.009 ;
     RECT  17.064 21.725 17.154 22.037 ;
     RECT  17.136 22.037 17.154 22.061 ;
     RECT  0.504 22.009 1.206 22.199 ;
     RECT  0.504 22.199 0.63 22.301 ;
     RECT  6.696 21.569 15.426 22.507 ;
     RECT  2.304 21.659 5.397 22.621 ;
     RECT  2.268 22.621 5.397 22.733 ;
     RECT  6.552 22.507 15.426 22.739 ;
     RECT  6.552 22.739 14.022 22.811 ;
     RECT  14.832 22.739 15.426 22.811 ;
     RECT  2.304 22.733 5.397 22.987 ;
     RECT  2.304 22.987 5.49 23.045 ;
     RECT  3.78 23.045 5.49 23.161 ;
     RECT  0.54 22.301 0.63 23.179 ;
     RECT  3.78 23.161 5.598 23.279 ;
     RECT  6.696 22.811 14.022 23.593 ;
     RECT  14.832 22.811 14.994 23.593 ;
     RECT  3.816 23.279 5.598 23.659 ;
     RECT  3.816 23.659 5.85 23.701 ;
     RECT  6.696 23.593 14.994 23.707 ;
     RECT  0.54 23.179 1.17 23.803 ;
     RECT  3.816 23.701 5.922 23.899 ;
     RECT  6.696 23.707 15.426 23.899 ;
     RECT  0.54 23.803 1.278 23.933 ;
     RECT  3.816 23.899 15.426 23.963 ;
     RECT  0.54 23.933 1.17 23.971 ;
     RECT  0.216 23.971 1.17 24.029 ;
     RECT  2.304 23.045 3.006 24.133 ;
     RECT  3.816 23.963 13.95 24.133 ;
     RECT  2.304 24.133 13.95 24.359 ;
     RECT  2.304 24.359 5.742 24.395 ;
     RECT  14.868 23.963 15.426 24.509 ;
     RECT  0.252 24.029 1.17 24.653 ;
     RECT  0.252 24.653 0.27 24.701 ;
     RECT  2.304 24.395 3.042 24.737 ;
     RECT  2.304 24.737 2.934 24.749 ;
     RECT  14.868 24.509 15.066 24.773 ;
     RECT  6.624 24.359 13.95 24.781 ;
     RECT  2.304 24.749 2.862 24.809 ;
     RECT  1.152 24.653 1.17 24.811 ;
     RECT  1.152 24.811 1.386 24.941 ;
     RECT  3.78 24.395 5.742 24.971 ;
     RECT  16.524 24.907 16.542 25.003 ;
     RECT  6.624 24.781 14.166 25.007 ;
     RECT  1.152 24.941 1.17 25.037 ;
     RECT  3.78 24.971 5.67 25.141 ;
     RECT  2.304 24.809 2.826 25.195 ;
     RECT  3.672 25.141 5.67 25.241 ;
     RECT  3.744 25.241 5.67 25.277 ;
     RECT  1.98 25.195 2.826 25.373 ;
     RECT  14.976 24.773 15.066 25.435 ;
     RECT  14.976 25.435 15.426 25.583 ;
     RECT  6.624 25.007 14.058 25.681 ;
     RECT  14.976 25.583 14.994 25.709 ;
     RECT  16.524 25.003 16.578 25.753 ;
     RECT  2.268 25.373 2.826 25.825 ;
     RECT  6.588 25.681 14.058 25.861 ;
     RECT  6.516 25.861 14.058 25.901 ;
     RECT  16.524 25.753 16.614 25.949 ;
     RECT  0.54 25.483 0.558 25.951 ;
     RECT  2.268 25.825 2.862 26.095 ;
     RECT  16.524 25.949 16.578 26.123 ;
     RECT  3.816 25.277 5.67 26.159 ;
     RECT  6.624 25.901 14.058 26.221 ;
     RECT  2.268 26.095 3.006 26.293 ;
     RECT  3.816 26.159 5.418 26.293 ;
     RECT  6.624 26.221 14.094 26.333 ;
     RECT  14.832 26.251 14.85 26.401 ;
     RECT  2.268 26.293 5.418 26.477 ;
     RECT  14.364 26.401 14.85 26.627 ;
     RECT  0.504 25.951 0.558 26.669 ;
     RECT  2.304 26.477 5.418 26.923 ;
     RECT  14.832 26.627 14.85 26.923 ;
     RECT  14.832 26.923 15.426 27.019 ;
     RECT  2.304 26.923 5.886 27.031 ;
     RECT  6.624 26.333 13.626 27.031 ;
     RECT  14.832 27.019 15.498 27.131 ;
     RECT  2.304 27.031 13.626 27.163 ;
     RECT  16.524 26.123 16.542 27.259 ;
     RECT  16.524 27.259 17.082 27.301 ;
     RECT  2.304 27.163 13.914 27.409 ;
     RECT  14.832 27.131 15.426 27.409 ;
     RECT  0.54 26.669 0.558 28.013 ;
     RECT  16.524 27.301 17.154 28.013 ;
     RECT  0.252 28.075 0.27 28.253 ;
     RECT  17.064 28.013 17.154 28.409 ;
     RECT  17.136 28.409 17.154 28.445 ;
     RECT  2.304 27.409 15.426 28.493 ;
     RECT  2.304 28.493 2.862 29.179 ;
     RECT  2.268 29.179 2.862 29.327 ;
     RECT  2.304 29.327 2.862 29.399 ;
     RECT  2.34 29.399 2.862 29.489 ;
     RECT  17.136 29.515 17.154 29.533 ;
     RECT  17.064 29.533 17.154 29.707 ;
     RECT  2.415 29.489 2.862 29.731 ;
     RECT  3.636 28.493 15.426 29.731 ;
     RECT  0.396 29.707 0.414 29.755 ;
     RECT  0.396 29.755 0.486 29.803 ;
     RECT  0.288 29.803 0.486 29.831 ;
     RECT  0.288 29.831 0.414 29.837 ;
     RECT  0.288 29.837 0.306 29.899 ;
     RECT  2.415 29.731 15.426 29.987 ;
     RECT  2.415 29.987 2.538 30.029 ;
     RECT  5.94 29.987 15.426 30.029 ;
     RECT  0.252 29.899 0.306 30.073 ;
     RECT  16.524 29.707 17.154 30.077 ;
     RECT  13.104 30.029 13.806 30.101 ;
     RECT  14.832 30.029 15.426 30.101 ;
     RECT  0.216 30.073 0.306 30.173 ;
     RECT  3.276 29.987 5.205 30.173 ;
     RECT  3.276 30.173 4.194 30.209 ;
     RECT  0.216 30.173 0.234 30.221 ;
     RECT  14.832 30.101 14.85 30.221 ;
     RECT  2.415 30.029 2.505 30.257 ;
     RECT  5.115 30.173 5.205 30.257 ;
     RECT  5.94 30.029 12.078 30.257 ;
     RECT  13.215 30.101 13.806 30.257 ;
     RECT  5.94 30.257 9.846 30.269 ;
     RECT  16.524 30.077 16.542 30.299 ;
     RECT  13.536 30.257 13.806 30.365 ;
     RECT  3.636 30.209 3.762 30.413 ;
     RECT  10.944 30.257 12.078 30.413 ;
     RECT  5.94 30.269 9.234 30.461 ;
     RECT  13.572 30.365 13.806 30.461 ;
     RECT  6.084 30.461 9.234 30.479 ;
     RECT  6.084 30.479 8.874 30.509 ;
     RECT  13.716 30.461 13.806 30.509 ;
     RECT  6.696 30.509 8.874 30.557 ;
     RECT  12.06 30.413 12.078 30.557 ;
     RECT  6.696 30.557 7.362 30.569 ;
     RECT  8.208 30.557 8.874 30.641 ;
     RECT  10.944 30.413 10.962 30.641 ;
     RECT  8.856 30.641 8.874 30.653 ;
     RECT  3.672 30.413 3.762 30.794 ;
     RECT  6.696 30.569 6.858 30.794 ;
     RECT  3.744 30.794 3.762 30.839 ;
     RECT  6.768 30.794 6.858 30.839 ;
     RECT  13.788 30.509 13.806 30.839 ;
     RECT  5.688 32.268 5.706 32.285 ;
    LAYER M4 ;
     RECT  0.192 2.208 0.278 2.232 ;
     RECT  0.156 2.232 0.278 2.304 ;
     RECT  0.192 2.304 0.278 2.328 ;
     RECT  0.156 2.328 0.278 2.448 ;
     RECT  0.192 2.448 0.278 2.472 ;
     RECT  0.156 2.472 0.278 2.544 ;
     RECT  0.192 2.544 0.278 2.568 ;
     RECT  0.156 2.568 0.278 2.64 ;
     RECT  0.192 2.64 0.278 2.664 ;
     RECT  0.156 2.664 0.278 2.736 ;
     RECT  0.192 2.736 0.278 2.76 ;
     RECT  0.156 2.76 0.278 2.832 ;
     RECT  0.192 2.832 0.278 2.856 ;
     RECT  0.156 2.856 0.278 2.928 ;
     RECT  0.192 2.928 0.278 2.952 ;
     RECT  0.156 2.952 0.278 3.024 ;
     RECT  0.192 3.024 0.278 3.048 ;
     RECT  0.156 3.048 0.278 3.12 ;
     RECT  0.192 3.12 0.278 3.144 ;
     RECT  0.156 3.144 0.278 3.216 ;
     RECT  0.192 3.216 0.278 3.24 ;
     RECT  0.156 3.24 0.278 3.36 ;
     RECT  0.192 3.36 0.278 3.384 ;
     RECT  0.156 3.384 0.278 3.456 ;
     RECT  0.192 3.456 0.278 3.48 ;
     RECT  0.156 3.48 0.278 3.552 ;
     RECT  0.192 3.552 0.278 3.576 ;
     RECT  0.156 3.576 0.278 3.648 ;
     RECT  0.192 3.648 0.278 3.672 ;
     RECT  0.156 3.672 0.278 3.744 ;
     RECT  0.192 3.744 0.278 3.768 ;
     RECT  0.156 3.768 0.278 3.84 ;
     RECT  0.192 3.84 0.278 3.864 ;
     RECT  0.156 3.864 0.278 3.936 ;
     RECT  0.192 3.936 0.278 3.96 ;
     RECT  0.156 3.96 0.278 4.032 ;
     RECT  0.192 4.032 0.278 4.056 ;
     RECT  0.156 4.056 0.278 4.128 ;
     RECT  0.192 4.128 0.278 4.152 ;
     RECT  0.156 4.152 0.278 4.272 ;
     RECT  0.192 4.272 0.278 4.296 ;
     RECT  0.156 4.296 0.278 4.368 ;
     RECT  0.192 4.368 0.278 4.392 ;
     RECT  0.156 4.392 0.278 4.464 ;
     RECT  0.192 4.464 0.278 4.488 ;
     RECT  0.156 4.488 0.278 4.56 ;
     RECT  0.192 4.56 0.278 4.584 ;
     RECT  0.156 4.584 0.278 4.656 ;
     RECT  0.192 4.656 0.278 4.68 ;
     RECT  0.156 4.68 0.278 4.752 ;
     RECT  0.192 4.752 0.278 4.776 ;
     RECT  0.156 4.776 0.278 4.848 ;
     RECT  0.192 4.848 0.278 4.872 ;
     RECT  0.156 4.872 0.278 4.944 ;
     RECT  0.192 4.944 0.278 4.968 ;
     RECT  0.156 4.968 0.278 5.04 ;
     RECT  0.192 5.04 0.278 5.064 ;
     RECT  0.156 5.064 0.278 5.184 ;
     RECT  0.192 5.184 0.278 5.208 ;
     RECT  0.156 5.208 0.278 5.28 ;
     RECT  0.192 5.28 0.278 5.304 ;
     RECT  0.156 5.304 0.278 5.376 ;
     RECT  0.192 5.376 0.278 5.4 ;
     RECT  0.156 5.4 0.278 5.472 ;
     RECT  0.192 5.472 0.278 5.496 ;
     RECT  0.156 5.496 0.278 5.568 ;
     RECT  0.192 5.568 0.278 5.592 ;
     RECT  0.156 5.592 0.278 5.664 ;
     RECT  0.192 5.664 0.278 5.688 ;
     RECT  0.156 5.688 0.278 5.76 ;
     RECT  0.192 5.76 0.278 5.784 ;
     RECT  0.156 5.784 0.278 5.856 ;
     RECT  0.192 5.856 0.278 5.88 ;
     RECT  0.156 5.88 0.278 5.952 ;
     RECT  0.192 5.952 0.278 5.976 ;
     RECT  0.156 5.976 0.278 6.096 ;
     RECT  0.192 6.096 0.278 6.12 ;
     RECT  0.156 6.12 0.278 6.192 ;
     RECT  0.192 6.192 0.278 6.216 ;
     RECT  0.156 6.216 0.278 6.288 ;
     RECT  0.192 6.288 0.278 6.312 ;
     RECT  0.156 6.312 0.278 6.384 ;
     RECT  0.192 6.384 0.278 6.408 ;
     RECT  0.156 6.408 0.278 6.48 ;
     RECT  0.192 6.48 0.278 6.504 ;
     RECT  0.156 6.504 0.278 6.576 ;
     RECT  0.192 6.576 0.278 6.6 ;
     RECT  0.156 6.6 0.278 6.672 ;
     RECT  0.192 6.672 0.278 6.696 ;
     RECT  0.156 6.696 0.278 6.768 ;
     RECT  0.192 6.768 0.278 6.792 ;
     RECT  0.156 6.792 0.278 6.864 ;
     RECT  0.192 6.864 0.278 6.888 ;
     RECT  0.156 6.888 0.278 7.008 ;
     RECT  0.192 7.008 0.278 7.032 ;
     RECT  0.156 7.032 0.278 7.104 ;
     RECT  0.192 7.104 0.278 7.128 ;
     RECT  0.156 7.128 0.278 7.2 ;
     RECT  0.192 7.2 0.278 7.224 ;
     RECT  0.156 7.224 0.278 7.296 ;
     RECT  0.192 7.296 0.278 7.32 ;
     RECT  0.156 7.32 0.278 7.392 ;
     RECT  0.192 7.392 0.278 7.416 ;
     RECT  0.156 7.416 0.278 7.488 ;
     RECT  0.192 7.488 0.278 7.512 ;
     RECT  0.156 7.512 0.278 7.584 ;
     RECT  0.192 7.584 0.278 7.608 ;
     RECT  0.156 7.608 0.278 7.68 ;
     RECT  0.192 7.68 0.278 7.704 ;
     RECT  0.156 7.704 0.278 7.776 ;
     RECT  0.192 7.776 0.278 7.8 ;
     RECT  0.156 7.8 0.278 7.92 ;
     RECT  0.192 7.92 0.278 7.944 ;
     RECT  0.156 7.944 0.278 8.016 ;
     RECT  0.192 8.016 0.278 8.04 ;
     RECT  0.156 8.04 0.278 8.112 ;
     RECT  0.192 8.112 0.278 8.136 ;
     RECT  0.156 8.136 0.278 8.208 ;
     RECT  0.192 8.208 0.278 8.232 ;
     RECT  0.156 8.232 0.278 8.304 ;
     RECT  0.192 8.304 0.278 8.328 ;
     RECT  0.156 8.328 0.278 8.4 ;
     RECT  0.192 8.4 0.278 8.424 ;
     RECT  0.156 8.424 0.278 8.496 ;
     RECT  0.192 8.496 0.278 8.52 ;
     RECT  0.156 8.52 0.278 8.592 ;
     RECT  0.192 8.592 0.278 8.616 ;
     RECT  0.156 8.616 0.278 8.688 ;
     RECT  0.192 8.688 0.278 8.712 ;
     RECT  0.156 8.712 0.278 8.832 ;
     RECT  0.192 8.832 0.278 8.856 ;
     RECT  0.156 8.856 0.278 8.928 ;
     RECT  0.192 8.928 0.278 8.952 ;
     RECT  0.156 8.952 0.278 9.024 ;
     RECT  0.192 9.024 0.278 9.048 ;
     RECT  0.156 9.048 0.278 9.12 ;
     RECT  0.192 9.12 0.278 9.144 ;
     RECT  0.156 9.144 0.278 9.216 ;
     RECT  0.192 9.216 0.278 9.24 ;
     RECT  0.156 9.24 0.278 9.312 ;
     RECT  0.192 9.312 0.278 9.336 ;
     RECT  0.156 9.336 0.278 9.408 ;
     RECT  0.192 9.408 0.278 9.432 ;
     RECT  0.156 9.432 0.278 9.504 ;
     RECT  0.192 9.504 0.278 9.528 ;
     RECT  0.156 9.528 0.278 9.6 ;
     RECT  0.192 9.6 0.278 9.624 ;
     RECT  0.156 9.624 0.278 9.744 ;
     RECT  0.192 9.744 0.278 9.768 ;
     RECT  0.156 9.768 0.278 9.84 ;
     RECT  0.192 9.84 0.278 9.864 ;
     RECT  0.156 9.864 0.278 9.936 ;
     RECT  0.192 9.936 0.278 9.96 ;
     RECT  0.156 9.96 0.278 10.032 ;
     RECT  0.192 10.032 0.278 10.056 ;
     RECT  0.156 10.056 0.278 10.128 ;
     RECT  0.192 10.128 0.278 10.152 ;
     RECT  0.156 10.152 0.278 10.224 ;
     RECT  0.192 10.224 0.278 10.248 ;
     RECT  0.156 10.248 0.278 10.32 ;
     RECT  0.192 10.32 0.278 10.344 ;
     RECT  0.156 10.344 0.278 10.416 ;
     RECT  0.192 10.416 0.278 10.44 ;
     RECT  0.156 10.44 0.278 10.512 ;
     RECT  0.192 10.512 0.278 10.536 ;
     RECT  0.156 10.536 0.278 10.656 ;
     RECT  0.192 10.656 0.278 10.68 ;
     RECT  0.156 10.68 0.278 10.752 ;
     RECT  0.192 10.752 0.278 10.776 ;
     RECT  0.156 10.776 0.278 10.848 ;
     RECT  0.192 10.848 0.278 10.872 ;
     RECT  0.156 10.872 0.278 10.944 ;
     RECT  0.192 10.944 0.278 10.968 ;
     RECT  0.156 10.968 0.278 11.04 ;
     RECT  0.192 11.04 0.278 11.064 ;
     RECT  0.156 11.064 0.278 11.136 ;
     RECT  0.192 11.136 0.278 11.16 ;
     RECT  0.156 11.16 0.278 11.232 ;
     RECT  0.192 11.232 0.278 11.256 ;
     RECT  0.156 11.256 0.278 11.328 ;
     RECT  0.192 11.328 0.278 11.352 ;
     RECT  0.156 11.352 0.278 11.424 ;
     RECT  0.192 11.424 0.278 11.448 ;
     RECT  0.156 11.448 0.278 11.568 ;
     RECT  0.192 11.568 0.278 11.592 ;
     RECT  0.156 11.592 0.278 11.664 ;
     RECT  0.192 11.664 0.278 11.688 ;
     RECT  0.156 11.688 0.278 11.76 ;
     RECT  0.192 11.76 0.278 11.784 ;
     RECT  0.156 11.784 0.278 11.856 ;
     RECT  0.192 11.856 0.278 11.88 ;
     RECT  0.156 11.88 0.278 11.952 ;
     RECT  0.192 11.952 0.278 11.976 ;
     RECT  0.156 11.976 0.278 12.048 ;
     RECT  0.192 12.048 0.278 12.072 ;
     RECT  0.156 12.072 0.278 12.144 ;
     RECT  0.192 12.144 0.278 12.168 ;
     RECT  0.156 12.168 0.278 12.24 ;
     RECT  0.192 12.24 0.278 12.264 ;
     RECT  0.156 12.264 0.278 12.336 ;
     RECT  0.192 12.336 0.278 12.36 ;
     RECT  0.156 12.36 0.278 12.48 ;
     RECT  0.192 12.48 0.278 12.504 ;
     RECT  0.156 12.504 0.278 12.576 ;
     RECT  0.192 12.576 0.278 12.6 ;
     RECT  0.156 12.6 0.278 12.672 ;
     RECT  0.192 12.672 0.278 12.696 ;
     RECT  0.156 12.696 0.278 12.768 ;
     RECT  0.192 12.768 0.278 12.792 ;
     RECT  0.156 12.792 0.278 12.864 ;
     RECT  0.192 12.864 0.278 12.888 ;
     RECT  0.156 12.888 0.278 12.96 ;
     RECT  0.192 12.96 0.278 12.984 ;
     RECT  0.156 12.984 0.278 13.056 ;
     RECT  0.192 13.056 0.278 13.08 ;
     RECT  0.156 13.08 0.278 13.152 ;
     RECT  0.192 13.152 0.278 13.176 ;
     RECT  0.156 13.176 0.278 13.296 ;
     RECT  0.192 13.296 0.278 13.32 ;
     RECT  0.156 13.32 0.278 13.392 ;
     RECT  0.192 13.392 0.278 13.416 ;
     RECT  0.156 13.416 0.278 13.488 ;
     RECT  0.192 13.488 0.278 13.512 ;
     RECT  0.156 13.512 0.278 13.584 ;
     RECT  0.192 13.584 0.278 13.608 ;
     RECT  0.156 13.608 0.278 13.68 ;
     RECT  0.192 13.68 0.278 13.704 ;
     RECT  0.156 13.704 0.278 13.776 ;
     RECT  0.192 13.776 0.278 13.8 ;
     RECT  0.156 13.8 0.278 13.872 ;
     RECT  0.192 13.872 0.278 13.896 ;
     RECT  0.156 13.896 0.278 13.968 ;
     RECT  0.192 13.968 0.278 13.992 ;
     RECT  0.156 13.992 0.278 14.064 ;
     RECT  0.192 14.064 0.278 14.088 ;
     RECT  0.156 14.088 0.278 14.208 ;
     RECT  0.192 14.208 0.278 14.232 ;
     RECT  0.156 14.232 0.278 14.304 ;
     RECT  0.192 14.304 0.278 14.328 ;
     RECT  0.156 14.328 0.278 14.4 ;
     RECT  0.192 14.4 0.278 14.424 ;
     RECT  0.156 14.424 0.278 14.496 ;
     RECT  0.192 14.496 0.278 14.52 ;
     RECT  0.156 14.52 0.278 14.592 ;
     RECT  0.192 14.592 0.278 14.616 ;
     RECT  0.156 14.616 0.278 14.688 ;
     RECT  0.192 14.688 0.278 14.712 ;
     RECT  0.156 14.712 0.278 14.784 ;
     RECT  0.192 14.784 0.278 14.808 ;
     RECT  0.156 14.808 0.278 14.88 ;
     RECT  0.192 14.88 0.278 14.904 ;
     RECT  0.156 14.904 0.278 14.976 ;
     RECT  0.192 14.976 0.278 15 ;
     RECT  0.156 15 0.278 15.12 ;
     RECT  0.192 15.12 0.278 15.144 ;
     RECT  0.156 15.144 0.278 15.216 ;
     RECT  0.192 15.216 0.278 15.24 ;
     RECT  0.156 15.24 0.278 15.312 ;
     RECT  0.192 15.312 0.278 15.336 ;
     RECT  0.156 15.336 0.278 15.408 ;
     RECT  0.192 15.408 0.278 15.432 ;
     RECT  0.156 15.432 0.278 15.504 ;
     RECT  0.192 15.504 0.278 15.528 ;
     RECT  0.156 15.528 0.278 15.6 ;
     RECT  0.192 15.6 0.278 15.624 ;
     RECT  0.156 15.624 0.278 15.696 ;
     RECT  0.192 15.696 0.278 15.72 ;
     RECT  0.156 15.72 0.278 15.792 ;
     RECT  0.192 15.792 0.278 15.816 ;
     RECT  0.156 15.816 0.278 15.888 ;
     RECT  0.192 15.888 0.278 15.912 ;
     RECT  0.156 15.912 0.278 16.032 ;
     RECT  0.192 16.032 0.278 16.056 ;
     RECT  0.156 16.056 0.278 16.128 ;
     RECT  0.192 16.128 0.278 16.152 ;
     RECT  0.156 16.152 0.278 16.224 ;
     RECT  0.192 16.224 0.278 16.248 ;
     RECT  0.156 16.248 0.278 16.32 ;
     RECT  0.192 16.32 0.278 16.344 ;
     RECT  0.156 16.344 0.278 16.416 ;
     RECT  0.192 16.416 0.278 16.44 ;
     RECT  0.156 16.44 0.278 16.512 ;
     RECT  0.192 16.512 0.278 16.536 ;
     RECT  0.156 16.536 0.278 16.608 ;
     RECT  0.192 16.608 0.278 16.632 ;
     RECT  0.156 16.632 0.278 16.704 ;
     RECT  0.192 16.704 0.278 16.728 ;
     RECT  0.156 16.728 0.278 16.8 ;
     RECT  0.192 16.8 0.278 16.824 ;
     RECT  0.156 16.824 0.278 16.944 ;
     RECT  0.192 16.944 0.278 16.968 ;
     RECT  0.156 16.968 0.278 17.04 ;
     RECT  0.192 17.04 0.278 17.064 ;
     RECT  0.156 17.064 0.278 17.136 ;
     RECT  0.192 17.136 0.278 17.16 ;
     RECT  0.156 17.16 0.278 17.232 ;
     RECT  0.192 17.232 0.278 17.256 ;
     RECT  0.156 17.256 0.278 17.328 ;
     RECT  0.192 17.328 0.278 17.352 ;
     RECT  0.156 17.352 0.278 17.424 ;
     RECT  0.192 17.424 0.278 17.448 ;
     RECT  0.156 17.448 0.278 17.52 ;
     RECT  0.192 17.52 0.278 17.544 ;
     RECT  0.156 17.544 0.278 17.616 ;
     RECT  0.192 17.616 0.278 17.64 ;
     RECT  0.156 17.64 0.278 17.712 ;
     RECT  0.192 17.712 0.278 17.736 ;
     RECT  0.156 17.736 0.278 17.856 ;
     RECT  0.192 17.856 0.278 17.88 ;
     RECT  0.156 17.88 0.278 17.952 ;
     RECT  0.192 17.952 0.278 17.976 ;
     RECT  0.156 17.976 0.278 18.048 ;
     RECT  0.192 18.048 0.278 18.072 ;
     RECT  0.156 18.072 0.278 18.144 ;
     RECT  0.192 18.144 0.278 18.168 ;
     RECT  0.156 18.168 0.278 18.24 ;
     RECT  0.192 18.24 0.278 18.264 ;
     RECT  0.156 18.264 0.278 18.336 ;
     RECT  0.192 18.336 0.278 18.36 ;
     RECT  0.156 18.36 0.278 18.432 ;
     RECT  0.192 18.432 0.278 18.456 ;
     RECT  0.156 18.456 0.278 18.528 ;
     RECT  0.192 18.528 0.278 18.552 ;
     RECT  0.156 18.552 0.278 18.624 ;
     RECT  0.192 18.624 0.278 18.648 ;
     RECT  0.156 18.648 0.278 18.768 ;
     RECT  0.192 18.768 0.278 18.792 ;
     RECT  0.156 18.792 0.278 18.864 ;
     RECT  0.192 18.864 0.278 18.888 ;
     RECT  0.156 18.888 0.278 18.96 ;
     RECT  0.192 18.96 0.278 18.984 ;
     RECT  0.156 18.984 0.278 19.056 ;
     RECT  0.192 19.056 0.278 19.08 ;
     RECT  0.156 19.08 0.278 19.152 ;
     RECT  0.192 19.152 0.278 19.176 ;
     RECT  0.156 19.176 0.278 19.248 ;
     RECT  0.192 19.248 0.278 19.272 ;
     RECT  0.156 19.272 0.278 19.344 ;
     RECT  0.192 19.344 0.278 19.368 ;
     RECT  0.156 19.368 0.278 19.44 ;
     RECT  0.192 19.44 0.278 19.464 ;
     RECT  0.156 19.464 0.278 19.536 ;
     RECT  0.192 19.536 0.278 19.56 ;
     RECT  0.156 19.56 0.278 19.68 ;
     RECT  0.192 19.68 0.278 19.704 ;
     RECT  0.156 19.704 0.278 19.776 ;
     RECT  0.192 19.776 0.278 19.8 ;
     RECT  0.156 19.8 0.278 19.872 ;
     RECT  0.192 19.872 0.278 19.896 ;
     RECT  0.156 19.896 0.278 19.968 ;
     RECT  0.192 19.968 0.278 19.992 ;
     RECT  0.156 19.992 0.278 20.064 ;
     RECT  0.192 20.064 0.278 20.088 ;
     RECT  0.156 20.088 0.278 20.16 ;
     RECT  0.192 20.16 0.278 20.184 ;
     RECT  0.156 20.184 0.278 20.256 ;
     RECT  0.192 20.256 0.278 20.28 ;
     RECT  0.156 20.28 0.278 20.352 ;
     RECT  0.192 20.352 0.278 20.376 ;
     RECT  0.156 20.376 0.278 20.448 ;
     RECT  0.192 20.448 0.278 20.472 ;
     RECT  0.156 20.472 0.278 20.592 ;
     RECT  0.192 20.592 0.278 20.616 ;
     RECT  0.156 20.616 0.278 20.688 ;
     RECT  0.192 20.688 0.278 20.712 ;
     RECT  0.156 20.712 0.278 20.784 ;
     RECT  0.192 20.784 0.278 20.808 ;
     RECT  0.156 20.808 0.278 20.88 ;
     RECT  0.192 20.88 0.278 20.904 ;
     RECT  0.156 20.904 0.278 20.976 ;
     RECT  0.192 20.976 0.278 21 ;
     RECT  0.156 21 0.278 21.072 ;
     RECT  0.192 21.072 0.278 21.096 ;
     RECT  0.156 21.096 0.278 21.168 ;
     RECT  0.192 21.168 0.278 21.192 ;
     RECT  0.156 21.192 0.278 21.264 ;
     RECT  0.192 21.264 0.278 21.288 ;
     RECT  0.156 21.288 0.278 21.36 ;
     RECT  0.192 21.36 0.278 21.384 ;
     RECT  0.156 21.384 0.278 21.504 ;
     RECT  0.192 21.504 0.278 21.528 ;
     RECT  0.156 21.528 0.278 21.6 ;
     RECT  0.192 21.6 0.278 21.624 ;
     RECT  0.156 21.624 0.278 21.696 ;
     RECT  0.192 21.696 0.278 21.72 ;
     RECT  0.156 21.72 0.278 21.792 ;
     RECT  0.192 21.792 0.278 21.816 ;
     RECT  0.156 21.816 0.278 21.888 ;
     RECT  0.192 21.888 0.278 21.912 ;
     RECT  0.156 21.912 0.278 21.984 ;
     RECT  0.192 21.984 0.278 22.008 ;
     RECT  0.156 22.008 0.278 22.08 ;
     RECT  0.192 22.08 0.278 22.104 ;
     RECT  0.156 22.104 0.278 22.176 ;
     RECT  0.192 22.176 0.278 22.2 ;
     RECT  0.156 22.2 0.278 22.272 ;
     RECT  0.192 22.272 0.278 22.296 ;
     RECT  0.156 22.296 0.278 22.416 ;
     RECT  0.192 22.416 0.278 22.44 ;
     RECT  0.156 22.44 0.278 22.512 ;
     RECT  0.192 22.512 0.278 22.536 ;
     RECT  0.156 22.536 0.278 22.608 ;
     RECT  0.192 22.608 0.278 22.632 ;
     RECT  0.156 22.632 0.278 22.704 ;
     RECT  0.192 22.704 0.278 22.728 ;
     RECT  0.156 22.728 0.278 22.8 ;
     RECT  0.192 22.8 0.278 22.824 ;
     RECT  0.156 22.824 0.278 22.896 ;
     RECT  0.192 22.896 0.278 22.92 ;
     RECT  0.156 22.92 0.278 22.992 ;
     RECT  0.192 22.992 0.278 23.016 ;
     RECT  0.156 23.016 0.278 23.088 ;
     RECT  0.192 23.088 0.278 23.112 ;
     RECT  0.156 23.112 0.278 23.184 ;
     RECT  0.192 23.184 0.278 23.208 ;
     RECT  0.156 23.208 0.278 23.328 ;
     RECT  0.192 23.328 0.278 23.352 ;
     RECT  0.156 23.352 0.278 23.424 ;
     RECT  0.192 23.424 0.278 23.448 ;
     RECT  0.156 23.448 0.278 23.52 ;
     RECT  0.192 23.52 0.278 23.544 ;
     RECT  0.156 23.544 0.278 23.616 ;
     RECT  0.192 23.616 0.278 23.64 ;
     RECT  0.156 23.64 0.278 23.712 ;
     RECT  0.192 23.712 0.278 23.736 ;
     RECT  0.156 23.736 0.278 23.808 ;
     RECT  0.192 23.808 0.278 23.832 ;
     RECT  0.156 23.832 0.278 23.904 ;
     RECT  0.192 23.904 0.278 23.928 ;
     RECT  0.156 23.928 0.278 24 ;
     RECT  0.192 24 0.278 24.024 ;
     RECT  0.156 24.024 0.278 24.096 ;
     RECT  0.192 24.096 0.278 24.12 ;
     RECT  0.156 24.12 0.278 24.24 ;
     RECT  0.192 24.24 0.278 24.264 ;
     RECT  0.156 24.264 0.278 24.336 ;
     RECT  0.192 24.336 0.278 24.36 ;
     RECT  0.156 24.36 0.278 24.432 ;
     RECT  0.192 24.432 0.278 24.456 ;
     RECT  0.156 24.456 0.278 24.528 ;
     RECT  0.192 24.528 0.278 24.552 ;
     RECT  0.156 24.552 0.278 24.624 ;
     RECT  0.192 24.624 0.278 24.648 ;
     RECT  0.156 24.648 0.278 24.72 ;
     RECT  0.192 24.72 0.278 24.744 ;
     RECT  0.156 24.744 0.278 24.816 ;
     RECT  0.192 24.816 0.278 24.84 ;
     RECT  0.156 24.84 0.278 24.912 ;
     RECT  0.192 24.912 0.278 24.936 ;
     RECT  0.156 24.936 0.278 25.008 ;
     RECT  0.192 25.008 0.278 25.032 ;
     RECT  0.156 25.032 0.278 25.152 ;
     RECT  0.192 25.152 0.278 25.176 ;
     RECT  0.156 25.176 0.278 25.248 ;
     RECT  0.192 25.248 0.278 25.272 ;
     RECT  0.156 25.272 0.278 25.344 ;
     RECT  0.192 25.344 0.278 25.368 ;
     RECT  0.156 25.368 0.278 25.44 ;
     RECT  0.192 25.44 0.278 25.464 ;
     RECT  0.156 25.464 0.278 25.536 ;
     RECT  0.192 25.536 0.278 25.56 ;
     RECT  0.156 25.56 0.278 25.632 ;
     RECT  0.192 25.632 0.278 25.656 ;
     RECT  0.156 25.656 0.278 25.728 ;
     RECT  0.192 25.728 0.278 25.752 ;
     RECT  0.156 25.752 0.278 25.824 ;
     RECT  0.192 25.824 0.278 25.848 ;
     RECT  0.156 25.848 0.278 25.92 ;
     RECT  0.192 25.92 0.278 25.944 ;
     RECT  0.156 25.944 0.278 26.064 ;
     RECT  0.192 26.064 0.278 26.088 ;
     RECT  0.156 26.088 0.278 26.16 ;
     RECT  0.192 26.16 0.278 26.184 ;
     RECT  0.156 26.184 0.278 26.256 ;
     RECT  0.192 26.256 0.278 26.28 ;
     RECT  0.156 26.28 0.278 26.352 ;
     RECT  0.192 26.352 0.278 26.376 ;
     RECT  0.156 26.376 0.278 26.448 ;
     RECT  0.192 26.448 0.278 26.472 ;
     RECT  0.156 26.472 0.278 26.544 ;
     RECT  0.192 26.544 0.278 26.568 ;
     RECT  0.156 26.568 0.278 26.64 ;
     RECT  0.192 26.64 0.278 26.664 ;
     RECT  0.156 26.664 0.278 26.736 ;
     RECT  0.192 26.736 0.278 26.76 ;
     RECT  0.156 26.76 0.278 26.88 ;
     RECT  0.192 26.88 0.278 26.904 ;
     RECT  0.156 26.904 0.278 26.976 ;
     RECT  0.192 26.976 0.278 27 ;
     RECT  0.156 27 0.278 27.072 ;
     RECT  0.192 27.072 0.278 27.096 ;
     RECT  0.156 27.096 0.278 27.168 ;
     RECT  0.192 27.168 0.278 27.192 ;
     RECT  0.156 27.192 0.278 27.264 ;
     RECT  0.192 27.264 0.278 27.288 ;
     RECT  0.156 27.288 0.278 27.36 ;
     RECT  0.192 27.36 0.278 27.384 ;
     RECT  0.156 27.384 0.278 27.456 ;
     RECT  0.192 27.456 0.278 27.48 ;
     RECT  0.156 27.48 0.278 27.552 ;
     RECT  0.192 27.552 0.278 27.576 ;
     RECT  0.156 27.576 0.278 27.648 ;
     RECT  0.192 27.648 0.278 27.672 ;
     RECT  0.156 27.672 0.278 27.792 ;
     RECT  0.192 27.792 0.278 27.816 ;
     RECT  0.156 27.816 0.278 27.888 ;
     RECT  0.192 27.888 0.278 27.912 ;
     RECT  0.156 27.912 0.278 27.984 ;
     RECT  0.192 27.984 0.278 28.008 ;
     RECT  0.156 28.008 0.278 28.08 ;
     RECT  0.192 28.08 0.278 28.104 ;
     RECT  0.156 28.104 0.278 28.176 ;
     RECT  0.192 28.176 0.278 28.2 ;
     RECT  0.156 28.2 0.278 28.272 ;
     RECT  0.192 28.272 0.278 28.296 ;
     RECT  0.156 28.296 0.278 28.368 ;
     RECT  0.192 28.368 0.278 28.392 ;
     RECT  0.156 28.392 0.278 28.464 ;
     RECT  0.192 28.464 0.278 28.488 ;
     RECT  0.156 28.488 0.278 28.56 ;
     RECT  0.192 28.56 0.278 28.584 ;
     RECT  0.156 28.584 0.278 28.704 ;
     RECT  0.192 28.704 0.278 28.728 ;
     RECT  0.156 28.728 0.278 28.8 ;
     RECT  0.192 28.8 0.278 28.824 ;
     RECT  0.156 28.824 0.278 28.896 ;
     RECT  0.192 28.896 0.278 28.92 ;
     RECT  0.156 28.92 0.278 28.992 ;
     RECT  0.192 28.992 0.278 29.016 ;
     RECT  0.156 29.016 0.278 29.088 ;
     RECT  0.192 29.088 0.278 29.112 ;
     RECT  0.156 29.112 0.278 29.184 ;
     RECT  0.192 29.184 0.278 29.208 ;
     RECT  0.156 29.208 0.278 29.28 ;
     RECT  0.192 29.28 0.278 29.304 ;
     RECT  0.156 29.304 0.278 29.376 ;
     RECT  0.192 29.376 0.278 29.4 ;
     RECT  0.156 29.4 0.278 29.472 ;
     RECT  0.192 29.472 0.278 29.496 ;
     RECT  0.156 29.496 0.278 29.616 ;
     RECT  0.192 29.616 0.278 29.64 ;
     RECT  0.156 29.64 0.278 29.712 ;
     RECT  0.192 29.712 0.278 29.736 ;
     RECT  0.156 29.736 0.278 29.808 ;
     RECT  0.192 29.808 0.278 29.832 ;
     RECT  0.156 29.832 0.278 29.904 ;
     RECT  0.192 29.904 0.278 29.928 ;
     RECT  0.156 29.928 0.278 30 ;
     RECT  0.192 30 0.278 30.024 ;
     RECT  0.156 30.024 0.278 30.096 ;
     RECT  0.192 30.096 0.278 30.12 ;
     RECT  0.156 30.12 0.278 30.192 ;
     RECT  0.192 30.192 0.278 30.216 ;
     RECT  0.278 2.208 2.408 30.168 ;
     RECT  2.408 2.148 2.512 30.252 ;
     RECT  2.512 2.418 2.704 30.168 ;
     RECT  2.704 2.544 3.625 30.168 ;
     RECT  3.625 2.544 3.737 30.408 ;
     RECT  3.737 2.736 3.881 30.408 ;
     RECT  3.881 2.832 5.108 30.408 ;
     RECT  5.108 2.148 5.212 30.408 ;
     RECT  5.212 2.418 5.404 30.408 ;
     RECT  5.389 32.16 5.677 32.184 ;
     RECT  5.677 32.16 5.717 32.28 ;
     RECT  5.404 12.48 5.929 30.408 ;
     RECT  5.929 12.48 6.073 30.456 ;
     RECT  5.404 7.152 6.38 8.04 ;
     RECT  5.404 2.832 6.757 5.592 ;
     RECT  6.38 6.816 6.757 8.04 ;
     RECT  6.757 2.832 6.793 8.04 ;
     RECT  5.404 9.072 6.793 11.16 ;
     RECT  6.073 12.48 6.793 30.504 ;
     RECT  6.793 2.832 6.829 30.504 ;
     RECT  6.829 2.592 7.405 30.6 ;
     RECT  7.405 2.352 7.808 30.6 ;
     RECT  7.808 2.148 7.912 30.6 ;
     RECT  7.912 2.304 8.245 30.6 ;
     RECT  8.245 2.304 8.885 30.648 ;
     RECT  8.885 2.304 9.281 30.6 ;
     RECT  5.717 32.256 9.491 32.28 ;
     RECT  9.281 2.352 10.508 30.6 ;
     RECT  10.508 2.148 10.612 30.6 ;
     RECT  10.612 2.304 11.891 30.6 ;
     RECT  11.891 2.304 12.089 30.552 ;
     RECT  12.089 2.304 13.208 30.504 ;
     RECT  13.208 2.148 13.312 30.504 ;
     RECT  13.312 2.352 13.565 30.504 ;
     RECT  13.565 2.592 13.745 30.504 ;
     RECT  13.745 2.592 14.821 30.12 ;
     RECT  14.821 2.208 17.088 2.232 ;
     RECT  14.821 2.232 17.1 2.304 ;
     RECT  14.821 2.304 17.088 2.328 ;
     RECT  14.821 2.328 17.1 2.448 ;
     RECT  14.821 2.448 17.088 2.472 ;
     RECT  14.821 2.472 17.1 2.544 ;
     RECT  14.821 2.544 17.088 2.568 ;
     RECT  14.821 2.568 17.1 2.64 ;
     RECT  14.821 2.64 17.088 2.664 ;
     RECT  14.821 2.664 17.1 2.736 ;
     RECT  14.821 2.736 17.088 2.76 ;
     RECT  14.821 2.76 17.1 2.832 ;
     RECT  14.821 2.832 17.088 2.856 ;
     RECT  14.821 2.856 17.1 2.928 ;
     RECT  14.821 2.928 17.088 2.952 ;
     RECT  14.821 2.952 17.1 3.024 ;
     RECT  14.821 3.024 17.088 3.048 ;
     RECT  14.821 3.048 17.1 3.12 ;
     RECT  14.821 3.12 17.088 3.144 ;
     RECT  14.821 3.144 17.1 3.264 ;
     RECT  14.821 3.264 17.088 3.288 ;
     RECT  14.821 3.288 17.1 3.36 ;
     RECT  14.821 3.36 17.088 3.384 ;
     RECT  14.821 3.384 17.1 3.456 ;
     RECT  14.821 3.456 17.088 3.48 ;
     RECT  14.821 3.48 17.1 3.552 ;
     RECT  14.821 3.552 17.088 3.576 ;
     RECT  14.821 3.576 17.1 3.648 ;
     RECT  14.821 3.648 17.088 3.672 ;
     RECT  14.821 3.672 17.1 3.744 ;
     RECT  14.821 3.744 17.088 3.768 ;
     RECT  14.821 3.768 17.1 3.84 ;
     RECT  14.821 3.84 17.088 3.864 ;
     RECT  14.821 3.864 17.1 3.936 ;
     RECT  14.821 3.936 17.088 3.96 ;
     RECT  14.821 3.96 17.1 4.032 ;
     RECT  14.821 4.032 17.088 4.056 ;
     RECT  14.821 4.056 17.1 4.176 ;
     RECT  14.821 4.176 17.088 4.2 ;
     RECT  14.821 4.2 17.1 4.272 ;
     RECT  14.821 4.272 17.088 4.296 ;
     RECT  14.821 4.296 17.1 4.368 ;
     RECT  14.821 4.368 17.088 4.392 ;
     RECT  14.821 4.392 17.1 4.464 ;
     RECT  14.821 4.464 17.088 4.488 ;
     RECT  14.821 4.488 17.1 4.56 ;
     RECT  14.821 4.56 17.088 4.584 ;
     RECT  14.821 4.584 17.1 4.656 ;
     RECT  14.821 4.656 17.088 4.68 ;
     RECT  14.821 4.68 17.1 4.752 ;
     RECT  14.821 4.752 17.088 4.776 ;
     RECT  14.821 4.776 17.1 4.848 ;
     RECT  14.821 4.848 17.088 4.872 ;
     RECT  14.821 4.872 17.1 4.992 ;
     RECT  14.821 4.992 17.088 5.016 ;
     RECT  14.821 5.016 17.1 5.088 ;
     RECT  14.821 5.088 17.088 5.112 ;
     RECT  14.821 5.112 17.1 5.184 ;
     RECT  14.821 5.184 17.088 5.208 ;
     RECT  14.821 5.208 17.1 5.28 ;
     RECT  14.821 5.28 17.088 5.304 ;
     RECT  14.821 5.304 17.1 5.376 ;
     RECT  14.821 5.376 17.088 5.4 ;
     RECT  14.821 5.4 17.1 5.472 ;
     RECT  14.821 5.472 17.088 5.496 ;
     RECT  14.821 5.496 17.1 5.568 ;
     RECT  14.821 5.568 17.088 5.592 ;
     RECT  14.821 5.592 17.1 5.664 ;
     RECT  14.821 5.664 17.088 5.688 ;
     RECT  14.821 5.688 17.1 5.76 ;
     RECT  14.821 5.76 17.088 5.784 ;
     RECT  14.821 5.784 17.1 5.904 ;
     RECT  14.821 5.904 17.088 5.928 ;
     RECT  14.821 5.928 17.1 6 ;
     RECT  14.821 6 17.088 6.024 ;
     RECT  14.821 6.024 17.1 6.096 ;
     RECT  14.821 6.096 17.088 6.12 ;
     RECT  14.821 6.12 17.1 6.192 ;
     RECT  14.821 6.192 17.088 6.216 ;
     RECT  14.821 6.216 17.1 6.288 ;
     RECT  14.821 6.288 17.088 6.312 ;
     RECT  14.821 6.312 17.1 6.384 ;
     RECT  14.821 6.384 17.088 6.408 ;
     RECT  14.821 6.408 17.1 6.48 ;
     RECT  14.821 6.48 17.088 6.504 ;
     RECT  14.821 6.504 17.1 6.576 ;
     RECT  14.821 6.576 17.088 6.6 ;
     RECT  14.821 6.6 17.1 6.72 ;
     RECT  14.821 6.72 17.088 6.744 ;
     RECT  14.821 6.744 17.1 6.816 ;
     RECT  14.821 6.816 17.088 6.84 ;
     RECT  14.821 6.84 17.1 6.912 ;
     RECT  14.821 6.912 17.088 6.936 ;
     RECT  14.821 6.936 17.1 7.008 ;
     RECT  14.821 7.008 17.088 7.032 ;
     RECT  14.821 7.032 17.1 7.104 ;
     RECT  14.821 7.104 17.088 7.128 ;
     RECT  14.821 7.128 17.1 7.2 ;
     RECT  14.821 7.2 17.088 7.224 ;
     RECT  14.821 7.224 17.1 7.296 ;
     RECT  14.821 7.296 17.088 7.32 ;
     RECT  14.821 7.32 17.1 7.392 ;
     RECT  14.821 7.392 17.088 7.416 ;
     RECT  14.821 7.416 17.1 7.536 ;
     RECT  14.821 7.536 17.088 7.56 ;
     RECT  14.821 7.56 17.1 7.632 ;
     RECT  14.821 7.632 17.088 7.656 ;
     RECT  14.821 7.656 17.1 7.728 ;
     RECT  14.821 7.728 17.088 7.752 ;
     RECT  14.821 7.752 17.1 7.824 ;
     RECT  14.821 7.824 17.088 7.848 ;
     RECT  14.821 7.848 17.1 7.92 ;
     RECT  14.821 7.92 17.088 7.944 ;
     RECT  14.821 7.944 17.1 8.016 ;
     RECT  14.821 8.016 17.088 8.04 ;
     RECT  14.821 8.04 17.1 8.112 ;
     RECT  14.821 8.112 17.088 8.136 ;
     RECT  14.821 8.136 17.1 8.208 ;
     RECT  14.821 8.208 17.088 8.232 ;
     RECT  14.821 8.232 17.1 8.304 ;
     RECT  14.821 8.304 17.088 8.328 ;
     RECT  14.821 8.328 17.1 8.448 ;
     RECT  14.821 8.448 17.088 8.472 ;
     RECT  14.821 8.472 17.1 8.544 ;
     RECT  14.821 8.544 17.088 8.568 ;
     RECT  14.821 8.568 17.1 8.64 ;
     RECT  14.821 8.64 17.088 8.664 ;
     RECT  14.821 8.664 17.1 8.736 ;
     RECT  14.821 8.736 17.088 8.76 ;
     RECT  14.821 8.76 17.1 8.832 ;
     RECT  14.821 8.832 17.088 8.856 ;
     RECT  14.821 8.856 17.1 8.928 ;
     RECT  14.821 8.928 17.088 8.952 ;
     RECT  14.821 8.952 17.1 9.024 ;
     RECT  14.821 9.024 17.088 9.048 ;
     RECT  14.821 9.048 17.1 9.12 ;
     RECT  14.821 9.12 17.088 9.144 ;
     RECT  14.821 9.144 17.1 9.264 ;
     RECT  14.821 9.264 17.088 9.288 ;
     RECT  14.821 9.288 17.1 9.36 ;
     RECT  14.821 9.36 17.088 9.384 ;
     RECT  14.821 9.384 17.1 9.456 ;
     RECT  14.821 9.456 17.088 9.48 ;
     RECT  14.821 9.48 17.1 9.552 ;
     RECT  14.821 9.552 17.088 9.576 ;
     RECT  14.821 9.576 17.1 9.648 ;
     RECT  14.821 9.648 17.088 9.672 ;
     RECT  14.821 9.672 17.1 9.744 ;
     RECT  14.821 9.744 17.088 9.768 ;
     RECT  14.821 9.768 17.1 9.84 ;
     RECT  14.821 9.84 17.088 9.864 ;
     RECT  14.821 9.864 17.1 9.936 ;
     RECT  14.821 9.936 17.088 9.96 ;
     RECT  14.821 9.96 17.1 10.08 ;
     RECT  14.821 10.08 17.088 10.104 ;
     RECT  14.821 10.104 17.1 10.176 ;
     RECT  14.821 10.176 17.088 10.2 ;
     RECT  14.821 10.2 17.1 10.272 ;
     RECT  14.821 10.272 17.088 10.296 ;
     RECT  14.821 10.296 17.1 10.368 ;
     RECT  14.821 10.368 17.088 10.392 ;
     RECT  14.821 10.392 17.1 10.464 ;
     RECT  14.821 10.464 17.088 10.488 ;
     RECT  14.821 10.488 17.1 10.56 ;
     RECT  14.821 10.56 17.088 10.584 ;
     RECT  14.821 10.584 17.1 10.656 ;
     RECT  14.821 10.656 17.088 10.68 ;
     RECT  14.821 10.68 17.1 10.752 ;
     RECT  14.821 10.752 17.088 10.776 ;
     RECT  14.821 10.776 17.1 10.848 ;
     RECT  14.821 10.848 17.088 10.872 ;
     RECT  14.821 10.872 17.1 10.992 ;
     RECT  14.821 10.992 17.088 11.016 ;
     RECT  14.821 11.016 17.1 11.088 ;
     RECT  14.821 11.088 17.088 11.112 ;
     RECT  14.821 11.112 17.1 11.184 ;
     RECT  14.821 11.184 17.088 11.208 ;
     RECT  14.821 11.208 17.1 11.28 ;
     RECT  14.821 11.28 17.088 11.304 ;
     RECT  14.821 11.304 17.1 11.376 ;
     RECT  14.821 11.376 17.088 11.4 ;
     RECT  14.821 11.4 17.1 11.472 ;
     RECT  14.821 11.472 17.088 11.496 ;
     RECT  14.821 11.496 17.1 11.568 ;
     RECT  14.821 11.568 17.088 11.592 ;
     RECT  14.821 11.592 17.1 11.664 ;
     RECT  14.821 11.664 17.088 11.688 ;
     RECT  14.821 11.688 17.1 11.808 ;
     RECT  14.821 11.808 17.088 11.832 ;
     RECT  14.821 11.832 17.1 11.904 ;
     RECT  14.821 11.904 17.088 11.928 ;
     RECT  14.821 11.928 17.1 12 ;
     RECT  14.821 12 17.088 12.024 ;
     RECT  14.821 12.024 17.1 12.096 ;
     RECT  14.821 12.096 17.088 12.12 ;
     RECT  14.821 12.12 17.1 12.192 ;
     RECT  14.821 12.192 17.088 12.216 ;
     RECT  14.821 12.216 17.1 12.288 ;
     RECT  14.821 12.288 17.088 12.312 ;
     RECT  14.821 12.312 17.1 12.384 ;
     RECT  14.821 12.384 17.088 12.408 ;
     RECT  14.821 12.408 17.1 12.48 ;
     RECT  14.821 12.48 17.088 12.504 ;
     RECT  14.821 12.504 17.1 12.624 ;
     RECT  14.821 12.624 17.088 12.648 ;
     RECT  14.821 12.648 17.1 12.72 ;
     RECT  14.821 12.72 17.088 12.744 ;
     RECT  14.821 12.744 17.1 12.816 ;
     RECT  14.821 12.816 17.088 12.84 ;
     RECT  14.821 12.84 17.1 12.912 ;
     RECT  14.821 12.912 17.088 12.936 ;
     RECT  14.821 12.936 17.1 13.008 ;
     RECT  14.821 13.008 17.088 13.032 ;
     RECT  14.821 13.032 17.1 13.104 ;
     RECT  14.821 13.104 17.088 13.128 ;
     RECT  14.821 13.128 17.1 13.2 ;
     RECT  14.821 13.2 17.088 13.224 ;
     RECT  14.821 13.224 17.1 13.296 ;
     RECT  14.821 13.296 17.088 13.32 ;
     RECT  14.821 13.32 17.1 13.392 ;
     RECT  14.821 13.392 17.088 13.416 ;
     RECT  14.821 13.416 17.1 13.536 ;
     RECT  14.821 13.536 17.088 13.56 ;
     RECT  14.821 13.56 17.1 13.632 ;
     RECT  14.821 13.632 17.088 13.656 ;
     RECT  14.821 13.656 17.1 13.728 ;
     RECT  14.821 13.728 17.088 13.752 ;
     RECT  14.821 13.752 17.1 13.824 ;
     RECT  14.821 13.824 17.088 13.848 ;
     RECT  14.821 13.848 17.1 13.92 ;
     RECT  14.821 13.92 17.088 13.944 ;
     RECT  14.821 13.944 17.1 14.016 ;
     RECT  14.821 14.016 17.088 14.04 ;
     RECT  14.821 14.04 17.1 14.112 ;
     RECT  14.821 14.112 17.088 14.136 ;
     RECT  14.821 14.136 17.1 14.208 ;
     RECT  14.821 14.208 17.088 14.232 ;
     RECT  14.821 14.232 17.1 14.352 ;
     RECT  14.821 14.352 17.088 14.376 ;
     RECT  14.821 14.376 17.1 14.448 ;
     RECT  14.821 14.448 17.088 14.472 ;
     RECT  14.821 14.472 17.1 14.544 ;
     RECT  14.821 14.544 17.088 14.568 ;
     RECT  14.821 14.568 17.1 14.64 ;
     RECT  14.821 14.64 17.088 14.664 ;
     RECT  14.821 14.664 17.1 14.736 ;
     RECT  14.821 14.736 17.088 14.76 ;
     RECT  14.821 14.76 17.1 14.832 ;
     RECT  14.821 14.832 17.088 14.856 ;
     RECT  14.821 14.856 17.1 14.928 ;
     RECT  14.821 14.928 17.088 14.952 ;
     RECT  14.821 14.952 17.1 15.024 ;
     RECT  14.821 15.024 17.088 15.048 ;
     RECT  14.821 15.048 17.1 15.12 ;
     RECT  14.821 15.12 17.088 15.144 ;
     RECT  14.821 15.144 17.1 15.264 ;
     RECT  14.821 15.264 17.088 15.288 ;
     RECT  14.821 15.288 17.1 15.36 ;
     RECT  14.821 15.36 17.088 15.384 ;
     RECT  14.821 15.384 17.1 15.456 ;
     RECT  14.821 15.456 17.088 15.48 ;
     RECT  14.821 15.48 17.1 15.552 ;
     RECT  14.821 15.552 17.088 15.576 ;
     RECT  14.821 15.576 17.1 15.648 ;
     RECT  14.821 15.648 17.088 15.672 ;
     RECT  14.821 15.672 17.1 15.744 ;
     RECT  14.821 15.744 17.088 15.768 ;
     RECT  14.821 15.768 17.1 15.84 ;
     RECT  14.821 15.84 17.088 15.864 ;
     RECT  14.821 15.864 17.1 15.936 ;
     RECT  14.821 15.936 17.088 15.96 ;
     RECT  14.821 15.96 17.1 16.08 ;
     RECT  14.821 16.08 17.088 16.104 ;
     RECT  14.821 16.104 17.1 16.176 ;
     RECT  14.821 16.176 17.088 16.2 ;
     RECT  14.821 16.2 17.1 16.272 ;
     RECT  14.821 16.272 17.088 16.296 ;
     RECT  14.821 16.296 17.1 16.368 ;
     RECT  14.821 16.368 17.088 16.392 ;
     RECT  14.821 16.392 17.1 16.464 ;
     RECT  14.821 16.464 17.088 16.488 ;
     RECT  14.821 16.488 17.1 16.56 ;
     RECT  14.821 16.56 17.088 16.584 ;
     RECT  14.821 16.584 17.1 16.656 ;
     RECT  14.821 16.656 17.088 16.68 ;
     RECT  14.821 16.68 17.1 16.752 ;
     RECT  14.821 16.752 17.088 16.776 ;
     RECT  14.821 16.776 17.1 16.896 ;
     RECT  14.821 16.896 17.088 16.92 ;
     RECT  14.821 16.92 17.1 16.992 ;
     RECT  14.821 16.992 17.088 17.016 ;
     RECT  14.821 17.016 17.1 17.088 ;
     RECT  14.821 17.088 17.088 17.112 ;
     RECT  14.821 17.112 17.1 17.184 ;
     RECT  14.821 17.184 17.088 17.208 ;
     RECT  14.821 17.208 17.1 17.28 ;
     RECT  14.821 17.28 17.088 17.304 ;
     RECT  14.821 17.304 17.1 17.376 ;
     RECT  14.821 17.376 17.088 17.4 ;
     RECT  14.821 17.4 17.1 17.472 ;
     RECT  14.821 17.472 17.088 17.496 ;
     RECT  14.821 17.496 17.1 17.568 ;
     RECT  14.821 17.568 17.088 17.592 ;
     RECT  14.821 17.592 17.1 17.664 ;
     RECT  14.821 17.664 17.088 17.688 ;
     RECT  14.821 17.688 17.1 17.808 ;
     RECT  14.821 17.808 17.088 17.832 ;
     RECT  14.821 17.832 17.1 17.904 ;
     RECT  14.821 17.904 17.088 17.928 ;
     RECT  14.821 17.928 17.1 18 ;
     RECT  14.821 18 17.088 18.024 ;
     RECT  14.821 18.024 17.1 18.096 ;
     RECT  14.821 18.096 17.088 18.12 ;
     RECT  14.821 18.12 17.1 18.192 ;
     RECT  14.821 18.192 17.088 18.216 ;
     RECT  14.821 18.216 17.1 18.288 ;
     RECT  14.821 18.288 17.088 18.312 ;
     RECT  14.821 18.312 17.1 18.384 ;
     RECT  14.821 18.384 17.088 18.408 ;
     RECT  14.821 18.408 17.1 18.48 ;
     RECT  14.821 18.48 17.088 18.504 ;
     RECT  14.821 18.504 17.1 18.624 ;
     RECT  14.821 18.624 17.088 18.648 ;
     RECT  14.821 18.648 17.1 18.72 ;
     RECT  14.821 18.72 17.088 18.744 ;
     RECT  14.821 18.744 17.1 18.816 ;
     RECT  14.821 18.816 17.088 18.84 ;
     RECT  14.821 18.84 17.1 18.912 ;
     RECT  14.821 18.912 17.088 18.936 ;
     RECT  14.821 18.936 17.1 19.008 ;
     RECT  14.821 19.008 17.088 19.032 ;
     RECT  14.821 19.032 17.1 19.104 ;
     RECT  14.821 19.104 17.088 19.128 ;
     RECT  14.821 19.128 17.1 19.2 ;
     RECT  14.821 19.2 17.088 19.224 ;
     RECT  14.821 19.224 17.1 19.296 ;
     RECT  14.821 19.296 17.088 19.32 ;
     RECT  14.821 19.32 17.1 19.44 ;
     RECT  14.821 19.44 17.088 19.464 ;
     RECT  14.821 19.464 17.1 19.536 ;
     RECT  14.821 19.536 17.088 19.56 ;
     RECT  14.821 19.56 17.1 19.632 ;
     RECT  14.821 19.632 17.088 19.656 ;
     RECT  14.821 19.656 17.1 19.728 ;
     RECT  14.821 19.728 17.088 19.752 ;
     RECT  14.821 19.752 17.1 19.824 ;
     RECT  14.821 19.824 17.088 19.848 ;
     RECT  14.821 19.848 17.1 19.92 ;
     RECT  14.821 19.92 17.088 19.944 ;
     RECT  14.821 19.944 17.1 20.016 ;
     RECT  14.821 20.016 17.088 20.04 ;
     RECT  14.821 20.04 17.1 20.112 ;
     RECT  14.821 20.112 17.088 20.136 ;
     RECT  14.821 20.136 17.1 20.208 ;
     RECT  14.821 20.208 17.088 20.232 ;
     RECT  14.821 20.232 17.1 20.352 ;
     RECT  14.821 20.352 17.088 20.376 ;
     RECT  14.821 20.376 17.1 20.448 ;
     RECT  14.821 20.448 17.088 20.472 ;
     RECT  14.821 20.472 17.1 20.544 ;
     RECT  14.821 20.544 17.088 20.568 ;
     RECT  14.821 20.568 17.1 20.64 ;
     RECT  14.821 20.64 17.088 20.664 ;
     RECT  14.821 20.664 17.1 20.736 ;
     RECT  14.821 20.736 17.088 20.76 ;
     RECT  14.821 20.76 17.1 20.832 ;
     RECT  14.821 20.832 17.088 20.856 ;
     RECT  14.821 20.856 17.1 20.928 ;
     RECT  14.821 20.928 17.088 20.952 ;
     RECT  14.821 20.952 17.1 21.024 ;
     RECT  14.821 21.024 17.088 21.048 ;
     RECT  14.821 21.048 17.1 21.168 ;
     RECT  14.821 21.168 17.088 21.192 ;
     RECT  14.821 21.192 17.1 21.264 ;
     RECT  14.821 21.264 17.088 21.288 ;
     RECT  14.821 21.288 17.1 21.36 ;
     RECT  14.821 21.36 17.088 21.384 ;
     RECT  14.821 21.384 17.1 21.456 ;
     RECT  14.821 21.456 17.088 21.48 ;
     RECT  14.821 21.48 17.1 21.552 ;
     RECT  14.821 21.552 17.088 21.576 ;
     RECT  14.821 21.576 17.1 21.648 ;
     RECT  14.821 21.648 17.088 21.672 ;
     RECT  14.821 21.672 17.1 21.744 ;
     RECT  14.821 21.744 17.088 21.768 ;
     RECT  14.821 21.768 17.1 21.84 ;
     RECT  14.821 21.84 17.088 21.864 ;
     RECT  14.821 21.864 17.1 21.984 ;
     RECT  14.821 21.984 17.088 22.008 ;
     RECT  14.821 22.008 17.1 22.08 ;
     RECT  14.821 22.08 17.088 22.104 ;
     RECT  14.821 22.104 17.1 22.176 ;
     RECT  14.821 22.176 17.088 22.2 ;
     RECT  14.821 22.2 17.1 22.272 ;
     RECT  14.821 22.272 17.088 22.296 ;
     RECT  14.821 22.296 17.1 22.368 ;
     RECT  14.821 22.368 17.088 22.392 ;
     RECT  14.821 22.392 17.1 22.464 ;
     RECT  14.821 22.464 17.088 22.488 ;
     RECT  14.821 22.488 17.1 22.56 ;
     RECT  14.821 22.56 17.088 22.584 ;
     RECT  14.821 22.584 17.1 22.656 ;
     RECT  14.821 22.656 17.088 22.68 ;
     RECT  14.821 22.68 17.1 22.752 ;
     RECT  14.821 22.752 17.088 22.776 ;
     RECT  14.821 22.776 17.1 22.896 ;
     RECT  14.821 22.896 17.088 22.92 ;
     RECT  14.821 22.92 17.1 22.992 ;
     RECT  14.821 22.992 17.088 23.016 ;
     RECT  14.821 23.016 17.1 23.088 ;
     RECT  14.821 23.088 17.088 23.112 ;
     RECT  14.821 23.112 17.1 23.184 ;
     RECT  14.821 23.184 17.088 23.208 ;
     RECT  14.821 23.208 17.1 23.28 ;
     RECT  14.821 23.28 17.088 23.304 ;
     RECT  14.821 23.304 17.1 23.376 ;
     RECT  14.821 23.376 17.088 23.4 ;
     RECT  14.821 23.4 17.1 23.472 ;
     RECT  14.821 23.472 17.088 23.496 ;
     RECT  14.821 23.496 17.1 23.568 ;
     RECT  14.821 23.568 17.088 23.592 ;
     RECT  14.821 23.592 17.1 23.712 ;
     RECT  14.821 23.712 17.088 23.736 ;
     RECT  14.821 23.736 17.1 23.808 ;
     RECT  14.821 23.808 17.088 23.832 ;
     RECT  14.821 23.832 17.1 23.904 ;
     RECT  14.821 23.904 17.088 23.928 ;
     RECT  14.821 23.928 17.1 24 ;
     RECT  14.821 24 17.088 24.024 ;
     RECT  14.821 24.024 17.1 24.096 ;
     RECT  14.821 24.096 17.088 24.12 ;
     RECT  14.821 24.12 17.1 24.192 ;
     RECT  14.821 24.192 17.088 24.216 ;
     RECT  14.821 24.216 17.1 24.288 ;
     RECT  14.821 24.288 17.088 24.312 ;
     RECT  14.821 24.312 17.1 24.384 ;
     RECT  14.821 24.384 17.088 24.408 ;
     RECT  14.821 24.408 17.1 24.48 ;
     RECT  14.821 24.48 17.088 24.504 ;
     RECT  14.821 24.504 17.1 24.624 ;
     RECT  14.821 24.624 17.088 24.648 ;
     RECT  14.821 24.648 17.1 24.72 ;
     RECT  14.821 24.72 17.088 24.744 ;
     RECT  14.821 24.744 17.1 24.816 ;
     RECT  14.821 24.816 17.088 24.84 ;
     RECT  14.821 24.84 17.1 24.912 ;
     RECT  14.821 24.912 17.088 24.936 ;
     RECT  14.821 24.936 17.1 25.008 ;
     RECT  14.821 25.008 17.088 25.032 ;
     RECT  14.821 25.032 17.1 25.104 ;
     RECT  14.821 25.104 17.088 25.128 ;
     RECT  14.821 25.128 17.1 25.2 ;
     RECT  14.821 25.2 17.088 25.224 ;
     RECT  14.821 25.224 17.1 25.296 ;
     RECT  14.821 25.296 17.088 25.32 ;
     RECT  14.821 25.32 17.1 25.44 ;
     RECT  14.821 25.44 17.088 25.464 ;
     RECT  14.821 25.464 17.1 25.536 ;
     RECT  14.821 25.536 17.088 25.56 ;
     RECT  14.821 25.56 17.1 25.632 ;
     RECT  14.821 25.632 17.088 25.656 ;
     RECT  14.821 25.656 17.1 25.728 ;
     RECT  14.821 25.728 17.088 25.752 ;
     RECT  14.821 25.752 17.1 25.824 ;
     RECT  14.821 25.824 17.088 25.848 ;
     RECT  14.821 25.848 17.1 25.92 ;
     RECT  14.821 25.92 17.088 25.944 ;
     RECT  14.821 25.944 17.1 26.016 ;
     RECT  14.821 26.016 17.088 26.04 ;
     RECT  14.821 26.04 17.1 26.112 ;
     RECT  14.821 26.112 17.088 26.136 ;
     RECT  14.821 26.136 17.1 26.256 ;
     RECT  14.821 26.256 17.088 26.28 ;
     RECT  14.821 26.28 17.1 26.352 ;
     RECT  14.821 26.352 17.088 26.376 ;
     RECT  14.821 26.376 17.1 26.448 ;
     RECT  14.821 26.448 17.088 26.472 ;
     RECT  14.821 26.472 17.1 26.544 ;
     RECT  14.821 26.544 17.088 26.568 ;
     RECT  14.821 26.568 17.1 26.64 ;
     RECT  14.821 26.64 17.088 26.664 ;
     RECT  14.821 26.664 17.1 26.736 ;
     RECT  14.821 26.736 17.088 26.76 ;
     RECT  14.821 26.76 17.1 26.832 ;
     RECT  14.821 26.832 17.088 26.856 ;
     RECT  14.821 26.856 17.1 26.928 ;
     RECT  14.821 26.928 17.088 26.952 ;
     RECT  14.821 26.952 17.1 27.024 ;
     RECT  14.821 27.024 17.088 27.048 ;
     RECT  14.821 27.048 17.1 27.168 ;
     RECT  14.821 27.168 17.088 27.192 ;
     RECT  14.821 27.192 17.1 27.264 ;
     RECT  14.821 27.264 17.088 27.288 ;
     RECT  14.821 27.288 17.1 27.36 ;
     RECT  14.821 27.36 17.088 27.384 ;
     RECT  14.821 27.384 17.1 27.456 ;
     RECT  14.821 27.456 17.088 27.48 ;
     RECT  14.821 27.48 17.1 27.552 ;
     RECT  14.821 27.552 17.088 27.576 ;
     RECT  14.821 27.576 17.1 27.648 ;
     RECT  14.821 27.648 17.088 27.672 ;
     RECT  14.821 27.672 17.1 27.744 ;
     RECT  14.821 27.744 17.088 27.768 ;
     RECT  14.821 27.768 17.1 27.84 ;
     RECT  14.821 27.84 17.088 27.864 ;
     RECT  14.821 27.864 17.1 27.984 ;
     RECT  14.821 27.984 17.088 28.008 ;
     RECT  14.821 28.008 17.1 28.08 ;
     RECT  14.821 28.08 17.088 28.104 ;
     RECT  14.821 28.104 17.1 28.176 ;
     RECT  14.821 28.176 17.088 28.2 ;
     RECT  14.821 28.2 17.1 28.272 ;
     RECT  14.821 28.272 17.088 28.296 ;
     RECT  14.821 28.296 17.1 28.368 ;
     RECT  14.821 28.368 17.088 28.392 ;
     RECT  14.821 28.392 17.1 28.464 ;
     RECT  14.821 28.464 17.088 28.488 ;
     RECT  14.821 28.488 17.1 28.56 ;
     RECT  14.821 28.56 17.088 28.584 ;
     RECT  14.821 28.584 17.1 28.656 ;
     RECT  14.821 28.656 17.088 28.68 ;
     RECT  14.821 28.68 17.1 28.8 ;
     RECT  14.821 28.8 17.088 28.824 ;
     RECT  14.821 28.824 17.1 28.896 ;
     RECT  14.821 28.896 17.088 28.92 ;
     RECT  14.821 28.92 17.1 28.992 ;
     RECT  14.821 28.992 17.088 29.016 ;
     RECT  14.821 29.016 17.1 29.088 ;
     RECT  14.821 29.088 17.088 29.112 ;
     RECT  14.821 29.112 17.1 29.184 ;
     RECT  14.821 29.184 17.088 29.208 ;
     RECT  14.821 29.208 17.1 29.28 ;
     RECT  14.821 29.28 17.088 29.304 ;
     RECT  14.821 29.304 17.1 29.376 ;
     RECT  14.821 29.376 17.088 29.4 ;
     RECT  14.821 29.4 17.1 29.472 ;
     RECT  14.821 29.472 17.088 29.496 ;
     RECT  14.821 29.496 17.1 29.568 ;
     RECT  14.821 29.568 17.088 29.592 ;
     RECT  14.821 29.592 17.1 29.712 ;
     RECT  14.821 29.712 17.088 29.736 ;
     RECT  14.821 29.736 17.1 29.808 ;
     RECT  14.821 29.808 17.088 29.832 ;
     RECT  14.821 29.832 17.1 29.904 ;
     RECT  14.821 29.904 17.088 29.928 ;
     RECT  14.821 29.928 17.1 30 ;
     RECT  14.821 30 17.088 30.024 ;
     RECT  14.821 30.024 17.1 30.096 ;
     RECT  14.821 30.096 17.088 30.12 ;
     RECT  14.821 30.12 17.1 30.192 ;
     RECT  14.821 30.192 17.088 30.216 ;
     RECT  17.1 3.888 17.165 3.912 ;
     RECT  17.1 8.16 17.165 8.208 ;
     RECT  17.1 8.232 17.165 8.304 ;
     RECT  17.1 8.328 17.165 8.448 ;
     RECT  17.1 8.472 17.165 8.544 ;
     RECT  17.1 8.568 17.165 8.64 ;
     RECT  17.1 8.664 17.165 8.736 ;
     RECT  17.1 8.76 17.165 8.832 ;
     RECT  17.1 8.856 17.165 8.928 ;
     RECT  17.1 8.952 17.165 9 ;
     RECT  17.1 10.128 17.165 10.152 ;
     RECT  17.1 14.976 17.165 15 ;
     RECT  17.1 16.608 17.165 16.656 ;
     RECT  17.1 16.68 17.165 16.752 ;
     RECT  17.1 16.776 17.165 16.896 ;
     RECT  17.1 16.92 17.165 16.968 ;
     RECT  17.1 18.144 17.165 18.168 ;
     RECT  17.1 20.976 17.165 21.024 ;
     RECT  17.1 21.048 17.165 21.168 ;
     RECT  17.1 21.192 17.165 21.264 ;
     RECT  17.1 21.288 17.165 21.36 ;
     RECT  17.1 21.384 17.165 21.456 ;
     RECT  17.1 21.48 17.165 21.552 ;
     RECT  17.1 21.576 17.165 21.648 ;
     RECT  17.1 21.672 17.165 21.744 ;
     RECT  17.1 21.768 17.165 21.84 ;
     RECT  17.1 21.864 17.165 21.984 ;
     RECT  17.1 22.008 17.165 22.056 ;
     RECT  17.1 27.312 17.165 27.36 ;
     RECT  17.1 27.384 17.165 27.456 ;
     RECT  17.1 27.48 17.165 27.552 ;
     RECT  17.1 27.576 17.165 27.648 ;
     RECT  17.1 27.672 17.165 27.744 ;
     RECT  17.1 27.768 17.165 27.84 ;
     RECT  17.1 27.864 17.165 27.984 ;
     RECT  17.1 28.008 17.165 28.08 ;
     RECT  17.1 28.104 17.165 28.176 ;
     RECT  17.1 28.2 17.165 28.272 ;
     RECT  17.1 28.296 17.165 28.368 ;
     RECT  17.1 28.392 17.165 28.44 ;
     RECT  17.1 29.52 17.165 29.568 ;
     RECT  17.1 29.592 17.165 29.712 ;
     RECT  17.1 29.736 17.165 29.808 ;
     RECT  17.1 29.832 17.165 29.904 ;
     RECT  17.1 29.928 17.165 30 ;
     RECT  17.1 30.024 17.165 30.072 ;
    LAYER M5 ;
     RECT  2.4 2.137 2.52 2.151 ;
     RECT  5.1 2.137 5.22 2.151 ;
     RECT  7.8 2.137 7.92 2.151 ;
     RECT  10.5 2.137 10.62 2.151 ;
     RECT  13.2 2.137 13.32 2.151 ;
     RECT  10.5 2.151 10.812 3.925 ;
     RECT  7.8 2.151 8.112 5.605 ;
     RECT  7.8 5.605 8.904 6.085 ;
     RECT  14.928 5.989 14.952 6.131 ;
     RECT  7.8 6.085 9 6.181 ;
     RECT  7.8 6.181 9.096 6.229 ;
     RECT  10.08 3.925 10.812 6.229 ;
     RECT  12.048 6.325 12.072 6.659 ;
     RECT  7.8 6.229 10.812 6.995 ;
     RECT  7.8 6.995 8.856 7.043 ;
     RECT  14.832 6.901 14.856 7.235 ;
     RECT  9.936 6.995 10.812 7.525 ;
     RECT  9.936 7.525 10.92 7.811 ;
     RECT  2.4 2.151 2.712 7.957 ;
     RECT  2.304 7.957 2.712 8.195 ;
     RECT  7.8 7.043 8.424 8.485 ;
     RECT  9.936 7.811 10.812 8.485 ;
     RECT  7.8 8.485 10.812 8.675 ;
     RECT  6.432 4.453 6.456 9.109 ;
     RECT  6.432 9.109 6.696 9.155 ;
     RECT  13.2 2.151 13.512 9.301 ;
     RECT  14.928 9.349 14.952 9.493 ;
     RECT  13.2 9.301 13.848 9.587 ;
     RECT  14.832 9.493 14.952 9.683 ;
     RECT  7.8 8.675 8.616 10.357 ;
     RECT  9.936 8.675 10.812 10.357 ;
     RECT  7.8 10.357 10.812 10.595 ;
     RECT  9.12 10.595 10.812 10.933 ;
     RECT  9.12 10.933 11.304 11.507 ;
     RECT  9.12 11.507 11.208 11.699 ;
     RECT  9.264 11.699 11.208 11.891 ;
     RECT  9.936 11.891 11.208 12.565 ;
     RECT  6.672 9.155 6.696 12.757 ;
     RECT  7.8 10.595 8.112 12.757 ;
     RECT  9.936 12.565 11.352 13.091 ;
     RECT  9.936 13.091 10.812 13.429 ;
     RECT  2.4 8.195 2.712 13.477 ;
     RECT  2.304 13.477 2.712 13.619 ;
     RECT  6.672 12.757 8.112 13.811 ;
     RECT  9.552 13.429 10.812 13.861 ;
     RECT  9.312 13.861 10.812 14.147 ;
     RECT  6.816 13.811 8.112 14.291 ;
     RECT  7.8 14.291 8.112 15.061 ;
     RECT  7.8 15.061 8.328 15.203 ;
     RECT  7.8 15.203 8.232 15.301 ;
     RECT  14.832 15.733 14.856 15.875 ;
     RECT  7.44 15.301 8.232 16.165 ;
     RECT  7.44 16.165 9 16.501 ;
     RECT  10.032 14.147 10.812 16.501 ;
     RECT  7.44 16.501 10.812 17.219 ;
     RECT  13.2 9.587 13.512 17.701 ;
     RECT  12.624 17.701 13.512 17.987 ;
     RECT  7.8 17.219 10.812 18.179 ;
     RECT  9.216 18.179 10.812 18.659 ;
     RECT  9.312 18.659 10.812 18.755 ;
     RECT  12.048 18.853 12.072 19.091 ;
     RECT  7.8 18.179 8.112 19.333 ;
     RECT  14.832 17.845 14.856 19.667 ;
     RECT  9.456 18.755 10.812 19.717 ;
     RECT  9.216 19.717 10.812 19.861 ;
     RECT  7.68 19.333 8.112 20.389 ;
     RECT  9.12 19.861 10.812 20.389 ;
     RECT  14.832 20.629 14.856 20.771 ;
     RECT  7.68 20.389 10.812 20.819 ;
     RECT  7.68 20.819 8.232 21.829 ;
     RECT  9.456 20.819 10.812 21.829 ;
     RECT  13.2 17.987 13.512 21.925 ;
     RECT  13.2 21.925 13.944 22.787 ;
     RECT  5.1 2.151 5.412 24.181 ;
     RECT  14.832 24.709 14.856 24.851 ;
     RECT  7.68 21.829 10.812 24.947 ;
     RECT  1.248 24.901 1.272 25.043 ;
     RECT  7.68 24.947 9.48 25.043 ;
     RECT  13.2 22.787 13.512 25.237 ;
     RECT  13.2 25.237 13.944 25.523 ;
     RECT  14.976 25.525 15 25.715 ;
     RECT  2.4 13.619 2.712 26.101 ;
     RECT  2.304 26.101 2.712 26.291 ;
     RECT  13.2 25.523 13.512 26.629 ;
     RECT  13.2 26.629 13.608 26.771 ;
     RECT  7.8 25.043 9.48 27.349 ;
     RECT  10.5 24.947 10.812 27.349 ;
     RECT  4.992 24.181 5.412 27.395 ;
     RECT  7.8 27.349 10.812 27.923 ;
     RECT  13.2 26.771 13.512 27.973 ;
     RECT  9.456 27.923 10.812 28.067 ;
     RECT  12.768 27.973 13.512 28.211 ;
     RECT  10.5 28.067 10.812 28.645 ;
     RECT  10.5 28.645 11.496 28.787 ;
     RECT  7.8 27.923 8.28 28.933 ;
     RECT  9.456 28.067 9.48 28.933 ;
     RECT  14.832 29.317 14.856 29.459 ;
     RECT  2.4 26.291 2.712 30.249 ;
     RECT  5.1 27.395 5.412 30.249 ;
     RECT  10.5 28.787 10.812 30.249 ;
     RECT  13.2 28.211 13.512 30.249 ;
     RECT  2.4 30.249 2.52 30.263 ;
     RECT  5.1 30.249 5.22 30.263 ;
     RECT  7.8 28.933 9.48 30.263 ;
     RECT  10.5 30.249 10.62 30.263 ;
     RECT  13.2 30.249 13.32 30.263 ;
     RECT  8.256 30.263 9.48 30.323 ;
     RECT  8.256 30.323 8.28 30.659 ;
     RECT  9.456 30.323 9.48 32.291 ;
     RECT  5.412 4.453 6.432 9.155 ;
     RECT  6.456 4.453 7.8 9.109 ;
     RECT  8.904 5.605 10.08 6.085 ;
     RECT  13.512 5.989 14.928 6.131 ;
     RECT  9 6.085 10.08 6.181 ;
     RECT  13.512 6.131 14.856 6.901 ;
     RECT  9.096 6.181 10.08 6.229 ;
     RECT  10.812 6.325 12.048 6.659 ;
     RECT  12.072 6.325 13.2 6.659 ;
     RECT  10.812 6.659 10.92 7.525 ;
     RECT  13.512 6.901 14.832 7.235 ;
     RECT  8.856 6.995 9.936 7.043 ;
     RECT  8.424 7.043 9.936 8.485 ;
     RECT  8.616 8.675 9.936 10.357 ;
     RECT  6.696 9.109 7.8 12.757 ;
     RECT  5.412 9.155 6.672 13.811 ;
     RECT  13.848 9.349 14.928 9.493 ;
     RECT  13.848 9.493 14.832 9.587 ;
     RECT  13.512 9.587 14.832 9.683 ;
     RECT  8.112 10.595 9.12 11.699 ;
     RECT  11.208 11.507 11.304 12.565 ;
     RECT  8.112 11.699 9.264 11.891 ;
     RECT  8.112 13.429 9.552 13.861 ;
     RECT  5.412 13.811 6.816 14.291 ;
     RECT  8.112 13.861 9.312 14.147 ;
     RECT  8.112 14.147 8.328 15.061 ;
     RECT  7.44 14.291 7.8 15.301 ;
     RECT  8.232 15.203 8.328 16.165 ;
     RECT  13.512 15.733 14.832 15.875 ;
     RECT  9 16.165 10.032 16.501 ;
     RECT  13.512 17.845 14.832 19.667 ;
     RECT  12.624 17.987 13.2 18.853 ;
     RECT  8.112 18.179 9.216 18.659 ;
     RECT  8.112 18.659 9.312 18.755 ;
     RECT  8.112 18.755 9.456 19.717 ;
     RECT  10.812 18.853 12.048 19.091 ;
     RECT  12.072 18.853 13.2 19.091 ;
     RECT  13.512 19.667 14.856 20.629 ;
     RECT  8.112 19.717 9.216 19.861 ;
     RECT  8.112 19.861 9.12 20.389 ;
     RECT  13.512 20.629 14.832 20.771 ;
     RECT  13.512 20.771 13.944 21.925 ;
     RECT  8.232 20.819 9.456 21.829 ;
     RECT  13.512 24.709 14.832 24.851 ;
     RECT  13.512 24.851 14.856 25.237 ;
     RECT  1.272 24.901 2.4 25.043 ;
     RECT  9.48 24.947 10.5 27.349 ;
     RECT  2.304 25.043 2.4 26.101 ;
     RECT  13.944 25.237 14.856 25.523 ;
     RECT  13.512 25.523 14.856 25.525 ;
     RECT  13.512 25.525 14.976 25.715 ;
     RECT  13.512 25.715 13.608 26.629 ;
     RECT  8.28 27.923 9.456 28.933 ;
     RECT  9.48 28.067 10.5 30.263 ;
     RECT  13.512 29.317 14.832 29.459 ;
     RECT  8.28 30.323 9.456 30.659 ;
  END
END dsfd_dvrlyh_276_EW
END LIBRARY
